###############################################################
#  Generated by:      Cadence Innovus 20.13-s083_1
#  OS:                Linux x86_64(Host ID caddy10)
#  Generated on:      Sun Jun 13 01:40:49 2021
#  Design:            user_proj_example
#  Command:           write_lef_abstract -specifyTopLayer 6 -PGPinLayers {5 6} -noCutObs -stripePin results/user_proj_example.lef
###############################################################

VERSION 5.8 ;

BUSBITCHARS "[]" ;
DIVIDERCHAR "/" ;

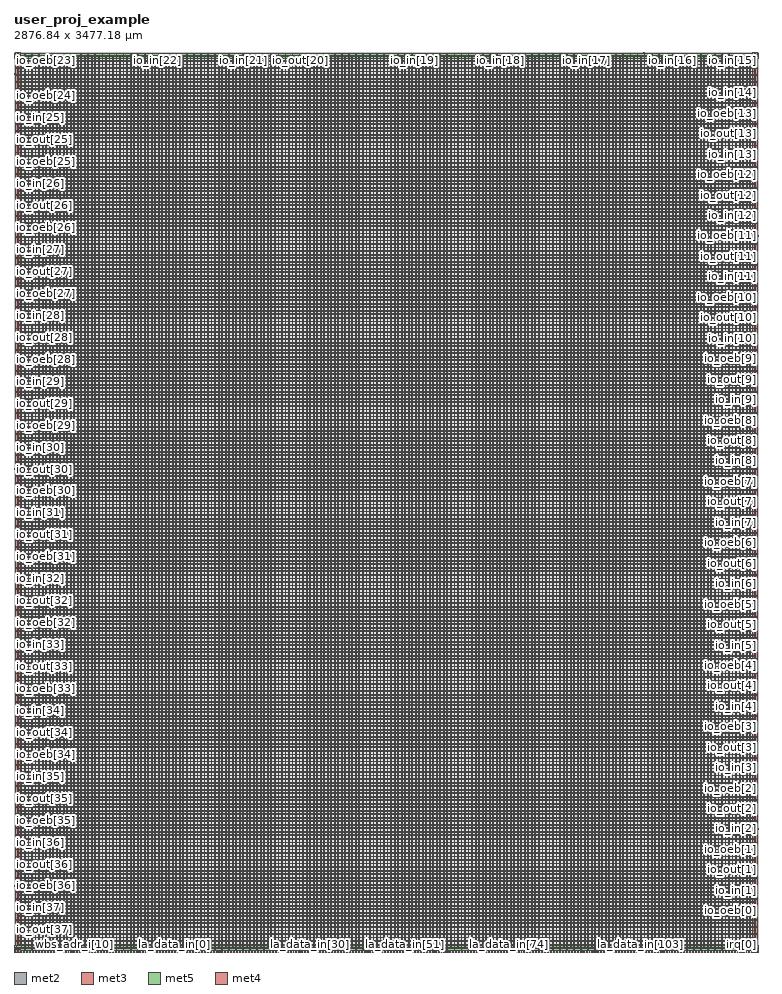
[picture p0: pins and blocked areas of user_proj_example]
MACRO user_proj_example
  CLASS BLOCK ;
  SIZE 2876.840000 BY 3477.180000 ;
  FOREIGN user_proj_example 0.000000 0.000000 ;
  ORIGIN 0 0 ;
  SYMMETRY X Y R90 ;
  PIN user_clock2
    DIRECTION INPUT ;
    USE SIGNAL ;
    PORT
      LAYER met2 ;
        RECT 2859.060000 0.000000 2859.200000 0.485000 ;
    END
  END user_clock2
  PIN wb_clk_i
    DIRECTION INPUT ;
    USE SIGNAL ;
    ANTENNAPARTIALMETALAREA 0.2744 LAYER met2  ;
    ANTENNAPARTIALMETALSIDEAREA 1.211 LAYER met2  ;
    ANTENNAPARTIALCUTAREA 0.04 LAYER via2  ;
    ANTENNAPARTIALMETALAREA 9.5028 LAYER met3  ;
    ANTENNAPARTIALMETALSIDEAREA 51.152 LAYER met3  ;
    ANTENNAMODEL OXIDE1 ;
    ANTENNAGATEAREA 0.576 LAYER met3  ;
    ANTENNAMAXAREACAR 24.1977 LAYER met3  ;
    ANTENNAMAXSIDEAREACAR 125.109 LAYER met3  ;
    ANTENNAMAXCUTCAR 0.158681 LAYER via3  ;
    PORT
      LAYER met2 ;
        RECT 0.620000 0.000000 0.760000 0.485000 ;
    END
  END wb_clk_i
  PIN wb_rst_i
    DIRECTION INPUT ;
    USE SIGNAL ;
    ANTENNAPARTIALMETALAREA 14.1803 LAYER met2  ;
    ANTENNAPARTIALMETALSIDEAREA 70.6755 LAYER met2  ;
    ANTENNAMODEL OXIDE1 ;
    ANTENNAGATEAREA 1.152 LAYER met2  ;
    ANTENNAMAXAREACAR 16.849 LAYER met2  ;
    ANTENNAMAXSIDEAREACAR 82.2422 LAYER met2  ;
    ANTENNAMAXCUTCAR 0.0446181 LAYER via2  ;
    PORT
      LAYER met2 ;
        RECT 6.140000 0.000000 6.280000 0.485000 ;
    END
  END wb_rst_i
  PIN wbs_stb_i
    DIRECTION INPUT ;
    USE SIGNAL ;
    ANTENNAPARTIALMETALAREA 12.5407 LAYER met2  ;
    ANTENNAPARTIALMETALSIDEAREA 62.3595 LAYER met2  ;
    ANTENNAMODEL OXIDE1 ;
    ANTENNAGATEAREA 0.747 LAYER met2  ;
    ANTENNAMAXAREACAR 51.6972 LAYER met2  ;
    ANTENNAMAXSIDEAREACAR 255.943 LAYER met2  ;
    ANTENNAMAXCUTCAR 0.407937 LAYER via2  ;
    PORT
      LAYER met2 ;
        RECT 23.620000 0.000000 23.760000 0.485000 ;
    END
  END wbs_stb_i
  PIN wbs_cyc_i
    DIRECTION INPUT ;
    USE SIGNAL ;
    PORT
      LAYER met2 ;
        RECT 18.100000 0.000000 18.240000 0.485000 ;
    END
  END wbs_cyc_i
  PIN wbs_we_i
    DIRECTION INPUT ;
    USE SIGNAL ;
    ANTENNAPARTIALMETALAREA 12.8503 LAYER met2  ;
    ANTENNAPARTIALMETALSIDEAREA 64.0255 LAYER met2  ;
    ANTENNAMODEL OXIDE1 ;
    ANTENNAGATEAREA 0.495 LAYER met2  ;
    ANTENNAMAXAREACAR 30.2657 LAYER met2  ;
    ANTENNAMAXSIDEAREACAR 149.204 LAYER met2  ;
    ANTENNAMAXCUTCAR 0.103838 LAYER via2  ;
    PORT
      LAYER met2 ;
        RECT 29.600000 0.000000 29.740000 0.485000 ;
    END
  END wbs_we_i
  PIN wbs_sel_i[3]
    DIRECTION INPUT ;
    USE SIGNAL ;
    PORT
      LAYER met2 ;
        RECT 122.980000 0.000000 123.120000 0.485000 ;
    END
  END wbs_sel_i[3]
  PIN wbs_sel_i[2]
    DIRECTION INPUT ;
    USE SIGNAL ;
    PORT
      LAYER met2 ;
        RECT 99.520000 0.000000 99.660000 0.485000 ;
    END
  END wbs_sel_i[2]
  PIN wbs_sel_i[1]
    DIRECTION INPUT ;
    USE SIGNAL ;
    PORT
      LAYER met2 ;
        RECT 76.060000 0.000000 76.200000 0.485000 ;
    END
  END wbs_sel_i[1]
  PIN wbs_sel_i[0]
    DIRECTION INPUT ;
    USE SIGNAL ;
    PORT
      LAYER met2 ;
        RECT 53.060000 0.000000 53.200000 0.485000 ;
    END
  END wbs_sel_i[0]
  PIN wbs_dat_i[31]
    DIRECTION INPUT ;
    USE SIGNAL ;
    ANTENNAPARTIALMETALAREA 9.9099 LAYER met2  ;
    ANTENNAPARTIALMETALSIDEAREA 49.3885 LAYER met2  ;
    ANTENNAPARTIALCUTAREA 0.04 LAYER via2  ;
    ANTENNAPARTIALMETALAREA 3.16 LAYER met3  ;
    ANTENNAPARTIALMETALSIDEAREA 17.32 LAYER met3  ;
    ANTENNAPARTIALCUTAREA 0.04 LAYER via3  ;
    ANTENNAPARTIALMETALAREA 72.1438 LAYER met4  ;
    ANTENNAPARTIALMETALSIDEAREA 381.112 LAYER met4  ;
    ANTENNAPARTIALCUTAREA 0.64 LAYER via4  ;
    ANTENNADIFFAREA 1.3041 LAYER met5  ;
    ANTENNAPARTIALMETALAREA 28.784 LAYER met5  ;
    ANTENNAPARTIALMETALSIDEAREA 58.536 LAYER met5  ;
    ANTENNAMODEL OXIDE1 ;
    ANTENNAGATEAREA 1.9926 LAYER met5  ;
    ANTENNAMAXAREACAR 130.13 LAYER met5  ;
    ANTENNAMAXSIDEAREACAR 622.528 LAYER met5  ;
    PORT
      LAYER met2 ;
        RECT 607.360000 0.000000 607.500000 0.485000 ;
    END
  END wbs_dat_i[31]
  PIN wbs_dat_i[30]
    DIRECTION INPUT ;
    USE SIGNAL ;
    ANTENNAPARTIALMETALAREA 6.1684 LAYER met2  ;
    ANTENNAPARTIALMETALSIDEAREA 30.681 LAYER met2  ;
    ANTENNAPARTIALCUTAREA 0.04 LAYER via2  ;
    ANTENNAPARTIALMETALAREA 0.952 LAYER met3  ;
    ANTENNAPARTIALMETALSIDEAREA 5.544 LAYER met3  ;
    ANTENNAPARTIALCUTAREA 0.04 LAYER via3  ;
    ANTENNAPARTIALMETALAREA 47.7568 LAYER met4  ;
    ANTENNAPARTIALMETALSIDEAREA 251.048 LAYER met4  ;
    ANTENNAPARTIALCUTAREA 0.64 LAYER via4  ;
    ANTENNADIFFAREA 0.8694 LAYER met5  ;
    ANTENNAPARTIALMETALAREA 32.128 LAYER met5  ;
    ANTENNAPARTIALMETALSIDEAREA 59.712 LAYER met5  ;
    ANTENNAMODEL OXIDE1 ;
    ANTENNAGATEAREA 1.5579 LAYER met5  ;
    ANTENNAMAXAREACAR 136.066 LAYER met5  ;
    ANTENNAMAXSIDEAREACAR 629.718 LAYER met5  ;
    PORT
      LAYER met2 ;
        RECT 589.880000 0.000000 590.020000 0.485000 ;
    END
  END wbs_dat_i[30]
  PIN wbs_dat_i[29]
    DIRECTION INPUT ;
    USE SIGNAL ;
    ANTENNAPARTIALMETALAREA 7.5558 LAYER met2  ;
    ANTENNAPARTIALMETALSIDEAREA 37.618 LAYER met2  ;
    ANTENNAPARTIALCUTAREA 0.04 LAYER via2  ;
    ANTENNAPARTIALMETALAREA 0.814 LAYER met3  ;
    ANTENNAPARTIALMETALSIDEAREA 4.808 LAYER met3  ;
    ANTENNAPARTIALCUTAREA 0.04 LAYER via3  ;
    ANTENNAPARTIALMETALAREA 4.6168 LAYER met4  ;
    ANTENNAPARTIALMETALSIDEAREA 20.968 LAYER met4  ;
    ANTENNAPARTIALCUTAREA 0.64 LAYER via4  ;
    ANTENNADIFFAREA 1.3041 LAYER met5  ;
    ANTENNAPARTIALMETALAREA 34.688 LAYER met5  ;
    ANTENNAPARTIALMETALSIDEAREA 67.392 LAYER met5  ;
    ANTENNAMODEL OXIDE1 ;
    ANTENNAGATEAREA 1.9926 LAYER met5  ;
    ANTENNAMAXAREACAR 122.263 LAYER met5  ;
    ANTENNAMAXSIDEAREACAR 568.279 LAYER met5  ;
    PORT
      LAYER met2 ;
        RECT 571.940000 0.000000 572.080000 0.485000 ;
    END
  END wbs_dat_i[29]
  PIN wbs_dat_i[28]
    DIRECTION INPUT ;
    USE SIGNAL ;
    ANTENNAPARTIALMETALAREA 9.9743 LAYER met2  ;
    ANTENNAPARTIALMETALSIDEAREA 49.7105 LAYER met2  ;
    ANTENNAPARTIALCUTAREA 0.04 LAYER via2  ;
    ANTENNAPARTIALMETALAREA 8.542 LAYER met3  ;
    ANTENNAPARTIALMETALSIDEAREA 46.024 LAYER met3  ;
    ANTENNAPARTIALCUTAREA 0.04 LAYER via3  ;
    ANTENNAPARTIALMETALAREA 31.7488 LAYER met4  ;
    ANTENNAPARTIALMETALSIDEAREA 165.672 LAYER met4  ;
    ANTENNAPARTIALCUTAREA 0.64 LAYER via4  ;
    ANTENNADIFFAREA 0.8694 LAYER met5  ;
    ANTENNAPARTIALMETALAREA 28.784 LAYER met5  ;
    ANTENNAPARTIALMETALSIDEAREA 58.536 LAYER met5  ;
    ANTENNAMODEL OXIDE1 ;
    ANTENNAGATEAREA 1.5579 LAYER met5  ;
    ANTENNAMAXAREACAR 82.9943 LAYER met5  ;
    ANTENNAMAXSIDEAREACAR 360.268 LAYER met5  ;
    PORT
      LAYER met2 ;
        RECT 554.460000 0.000000 554.600000 0.485000 ;
    END
  END wbs_dat_i[28]
  PIN wbs_dat_i[27]
    DIRECTION INPUT ;
    USE SIGNAL ;
    ANTENNAPARTIALMETALAREA 9.9099 LAYER met2  ;
    ANTENNAPARTIALMETALSIDEAREA 49.3885 LAYER met2  ;
    ANTENNAPARTIALCUTAREA 0.04 LAYER via2  ;
    ANTENNAPARTIALMETALAREA 1.297 LAYER met3  ;
    ANTENNAPARTIALMETALSIDEAREA 7.384 LAYER met3  ;
    ANTENNAPARTIALCUTAREA 0.04 LAYER via3  ;
    ANTENNAPARTIALMETALAREA 62.0944 LAYER met4  ;
    ANTENNAPARTIALMETALSIDEAREA 328.456 LAYER met4  ;
    ANTENNAPARTIALCUTAREA 0.64 LAYER via4  ;
    ANTENNADIFFAREA 1.3041 LAYER met5  ;
    ANTENNAPARTIALMETALAREA 81.904 LAYER met5  ;
    ANTENNAPARTIALMETALSIDEAREA 138.216 LAYER met5  ;
    ANTENNAMODEL OXIDE1 ;
    ANTENNAGATEAREA 1.9926 LAYER met5  ;
    ANTENNAMAXAREACAR 122.231 LAYER met5  ;
    ANTENNAMAXSIDEAREACAR 480.79 LAYER met5  ;
    PORT
      LAYER met2 ;
        RECT 536.980000 0.000000 537.120000 0.485000 ;
    END
  END wbs_dat_i[27]
  PIN wbs_dat_i[26]
    DIRECTION INPUT ;
    USE SIGNAL ;
    ANTENNAPARTIALMETALAREA 3.8612 LAYER met2  ;
    ANTENNAPARTIALMETALSIDEAREA 19.145 LAYER met2  ;
    ANTENNAPARTIALCUTAREA 0.04 LAYER via2  ;
    ANTENNAPARTIALMETALAREA 4.609 LAYER met3  ;
    ANTENNAPARTIALMETALSIDEAREA 25.048 LAYER met3  ;
    ANTENNAPARTIALCUTAREA 0.04 LAYER via3  ;
    ANTENNAPARTIALMETALAREA 65.3806 LAYER met4  ;
    ANTENNAPARTIALMETALSIDEAREA 345.512 LAYER met4  ;
    ANTENNAPARTIALCUTAREA 0.64 LAYER via4  ;
    ANTENNADIFFAREA 1.3041 LAYER met5  ;
    ANTENNAPARTIALMETALAREA 133.984 LAYER met5  ;
    ANTENNAPARTIALMETALSIDEAREA 208.656 LAYER met5  ;
    ANTENNAMODEL OXIDE1 ;
    ANTENNAGATEAREA 1.9926 LAYER met5  ;
    ANTENNAMAXAREACAR 191.53 LAYER met5  ;
    ANTENNAMAXSIDEAREACAR 743.382 LAYER met5  ;
    PORT
      LAYER met2 ;
        RECT 519.500000 0.000000 519.640000 0.485000 ;
    END
  END wbs_dat_i[26]
  PIN wbs_dat_i[25]
    DIRECTION INPUT ;
    USE SIGNAL ;
    ANTENNAPARTIALMETALAREA 7.791 LAYER met2  ;
    ANTENNAPARTIALMETALSIDEAREA 38.794 LAYER met2  ;
    ANTENNAPARTIALCUTAREA 0.04 LAYER via2  ;
    ANTENNAPARTIALMETALAREA 7.645 LAYER met3  ;
    ANTENNAPARTIALMETALSIDEAREA 41.24 LAYER met3  ;
    ANTENNAPARTIALCUTAREA 0.04 LAYER via3  ;
    ANTENNAPARTIALMETALAREA 40.4848 LAYER met4  ;
    ANTENNAPARTIALMETALSIDEAREA 212.264 LAYER met4  ;
    ANTENNAPARTIALCUTAREA 0.64 LAYER via4  ;
    ANTENNADIFFAREA 0.8694 LAYER met5  ;
    ANTENNAPARTIALMETALAREA 69.904 LAYER met5  ;
    ANTENNAPARTIALMETALSIDEAREA 124.056 LAYER met5  ;
    ANTENNAMODEL OXIDE1 ;
    ANTENNAGATEAREA 1.5579 LAYER met5  ;
    ANTENNAMAXAREACAR 131.547 LAYER met5  ;
    ANTENNAMAXSIDEAREACAR 523.396 LAYER met5  ;
    PORT
      LAYER met2 ;
        RECT 502.020000 0.000000 502.160000 0.485000 ;
    END
  END wbs_dat_i[25]
  PIN wbs_dat_i[24]
    DIRECTION INPUT ;
    USE SIGNAL ;
    ANTENNAPARTIALMETALAREA 10.738 LAYER met2  ;
    ANTENNAPARTIALMETALSIDEAREA 53.529 LAYER met2  ;
    ANTENNAPARTIALCUTAREA 0.04 LAYER via2  ;
    ANTENNAPARTIALMETALAREA 7.921 LAYER met3  ;
    ANTENNAPARTIALMETALSIDEAREA 42.712 LAYER met3  ;
    ANTENNAPARTIALCUTAREA 0.04 LAYER via3  ;
    ANTENNAPARTIALMETALAREA 50.5258 LAYER met4  ;
    ANTENNAPARTIALMETALSIDEAREA 265.816 LAYER met4  ;
    ANTENNAPARTIALCUTAREA 0.64 LAYER via4  ;
    ANTENNADIFFAREA 0.8694 LAYER met5  ;
    ANTENNAPARTIALMETALAREA 45.152 LAYER met5  ;
    ANTENNAPARTIALMETALSIDEAREA 86.928 LAYER met5  ;
    ANTENNAMODEL OXIDE1 ;
    ANTENNAGATEAREA 1.5579 LAYER met5  ;
    ANTENNAMAXAREACAR 113.719 LAYER met5  ;
    ANTENNAMAXSIDEAREACAR 490.9 LAYER met5  ;
    PORT
      LAYER met2 ;
        RECT 484.540000 0.000000 484.680000 0.485000 ;
    END
  END wbs_dat_i[24]
  PIN wbs_dat_i[23]
    DIRECTION INPUT ;
    USE SIGNAL ;
    ANTENNAPARTIALMETALAREA 7.053 LAYER met2  ;
    ANTENNAPARTIALMETALSIDEAREA 34.986 LAYER met2  ;
    ANTENNAPARTIALCUTAREA 0.04 LAYER via2  ;
    ANTENNAPARTIALMETALAREA 3.643 LAYER met3  ;
    ANTENNAPARTIALMETALSIDEAREA 19.896 LAYER met3  ;
    ANTENNAPARTIALCUTAREA 0.04 LAYER via3  ;
    ANTENNAPARTIALMETALAREA 70.4968 LAYER met4  ;
    ANTENNAPARTIALMETALSIDEAREA 372.328 LAYER met4  ;
    ANTENNAPARTIALCUTAREA 0.64 LAYER via4  ;
    ANTENNADIFFAREA 0.4347 LAYER met5  ;
    ANTENNAPARTIALMETALAREA 23.296 LAYER met5  ;
    ANTENNAPARTIALMETALSIDEAREA 46.464 LAYER met5  ;
    ANTENNAMODEL OXIDE1 ;
    ANTENNAGATEAREA 1.1232 LAYER met5  ;
    ANTENNAMAXAREACAR 170.738 LAYER met5  ;
    ANTENNAMAXSIDEAREACAR 789.227 LAYER met5  ;
    PORT
      LAYER met2 ;
        RECT 467.060000 0.000000 467.200000 0.485000 ;
    END
  END wbs_dat_i[23]
  PIN wbs_dat_i[22]
    DIRECTION INPUT ;
    USE SIGNAL ;
    ANTENNAPARTIALMETALAREA 3.2634 LAYER met2  ;
    ANTENNAPARTIALMETALSIDEAREA 16.156 LAYER met2  ;
    ANTENNAPARTIALCUTAREA 0.04 LAYER via2  ;
    ANTENNAPARTIALMETALAREA 22.894 LAYER met3  ;
    ANTENNAPARTIALMETALSIDEAREA 122.568 LAYER met3  ;
    ANTENNAPARTIALCUTAREA 0.04 LAYER via3  ;
    ANTENNAPARTIALMETALAREA 65.9218 LAYER met4  ;
    ANTENNAPARTIALMETALSIDEAREA 347.928 LAYER met4  ;
    ANTENNAPARTIALCUTAREA 0.64 LAYER via4  ;
    ANTENNADIFFAREA 0.8694 LAYER met5  ;
    ANTENNAPARTIALMETALAREA 107.84 LAYER met5  ;
    ANTENNAPARTIALMETALSIDEAREA 173.28 LAYER met5  ;
    ANTENNAMODEL OXIDE1 ;
    ANTENNAGATEAREA 1.5579 LAYER met5  ;
    ANTENNAMAXAREACAR 177.438 LAYER met5  ;
    ANTENNAMAXSIDEAREACAR 665.246 LAYER met5  ;
    PORT
      LAYER met2 ;
        RECT 449.580000 0.000000 449.720000 0.485000 ;
    END
  END wbs_dat_i[22]
  PIN wbs_dat_i[21]
    DIRECTION INPUT ;
    USE SIGNAL ;
    ANTENNAPARTIALMETALAREA 9.4976 LAYER met2  ;
    ANTENNAPARTIALMETALSIDEAREA 47.327 LAYER met2  ;
    ANTENNAPARTIALCUTAREA 0.04 LAYER via2  ;
    ANTENNAPARTIALMETALAREA 23.791 LAYER met3  ;
    ANTENNAPARTIALMETALSIDEAREA 127.352 LAYER met3  ;
    ANTENNAPARTIALCUTAREA 0.04 LAYER via3  ;
    ANTENNAPARTIALMETALAREA 16.9018 LAYER met4  ;
    ANTENNAPARTIALMETALSIDEAREA 86.488 LAYER met4  ;
    ANTENNAPARTIALCUTAREA 0.64 LAYER via4  ;
    ANTENNADIFFAREA 1.3041 LAYER met5  ;
    ANTENNAPARTIALMETALAREA 22.96 LAYER met5  ;
    ANTENNAPARTIALMETALSIDEAREA 45.96 LAYER met5  ;
    ANTENNAMODEL OXIDE1 ;
    ANTENNAGATEAREA 1.9926 LAYER met5  ;
    ANTENNAMAXAREACAR 93.4912 LAYER met5  ;
    ANTENNAMAXSIDEAREACAR 435.548 LAYER met5  ;
    PORT
      LAYER met2 ;
        RECT 432.100000 0.000000 432.240000 0.485000 ;
    END
  END wbs_dat_i[21]
  PIN wbs_dat_i[20]
    DIRECTION INPUT ;
    USE SIGNAL ;
    ANTENNAPARTIALMETALAREA 8.729 LAYER met2  ;
    ANTENNAPARTIALMETALSIDEAREA 43.484 LAYER met2  ;
    ANTENNAPARTIALCUTAREA 0.04 LAYER via2  ;
    ANTENNAPARTIALMETALAREA 30.277 LAYER met3  ;
    ANTENNAPARTIALMETALSIDEAREA 161.944 LAYER met3  ;
    ANTENNAPARTIALCUTAREA 0.04 LAYER via3  ;
    ANTENNAPARTIALMETALAREA 71.2126 LAYER met4  ;
    ANTENNAPARTIALMETALSIDEAREA 376.616 LAYER met4  ;
    ANTENNAPARTIALCUTAREA 0.64 LAYER via4  ;
    ANTENNADIFFAREA 0.8694 LAYER met5  ;
    ANTENNAPARTIALMETALAREA 38 LAYER met5  ;
    ANTENNAPARTIALMETALSIDEAREA 72.36 LAYER met5  ;
    ANTENNAMODEL OXIDE1 ;
    ANTENNAGATEAREA 1.5579 LAYER met5  ;
    ANTENNAMAXAREACAR 86.1611 LAYER met5  ;
    ANTENNAMAXSIDEAREACAR 348.053 LAYER met5  ;
    PORT
      LAYER met2 ;
        RECT 414.620000 0.000000 414.760000 0.485000 ;
    END
  END wbs_dat_i[20]
  PIN wbs_dat_i[19]
    DIRECTION INPUT ;
    USE SIGNAL ;
    ANTENNAPARTIALMETALAREA 5.0148 LAYER met2  ;
    ANTENNAPARTIALMETALSIDEAREA 24.913 LAYER met2  ;
    ANTENNAPARTIALCUTAREA 0.04 LAYER via2  ;
    ANTENNAPARTIALMETALAREA 45.802 LAYER met3  ;
    ANTENNAPARTIALMETALSIDEAREA 244.744 LAYER met3  ;
    ANTENNAPARTIALCUTAREA 0.04 LAYER via3  ;
    ANTENNAPARTIALMETALAREA 45.9508 LAYER met4  ;
    ANTENNAPARTIALMETALSIDEAREA 241.416 LAYER met4  ;
    ANTENNAPARTIALCUTAREA 0.64 LAYER via4  ;
    ANTENNADIFFAREA 1.3041 LAYER met5  ;
    ANTENNAPARTIALMETALAREA 7.44 LAYER met5  ;
    ANTENNAPARTIALMETALSIDEAREA 15 LAYER met5  ;
    ANTENNAMODEL OXIDE1 ;
    ANTENNAGATEAREA 1.9926 LAYER met5  ;
    ANTENNAMAXAREACAR 89.1782 LAYER met5  ;
    ANTENNAMAXSIDEAREACAR 442.671 LAYER met5  ;
    PORT
      LAYER met2 ;
        RECT 397.140000 0.000000 397.280000 0.485000 ;
    END
  END wbs_dat_i[19]
  PIN wbs_dat_i[18]
    DIRECTION INPUT ;
    USE SIGNAL ;
    ANTENNAPARTIALMETALAREA 2.5802 LAYER met2  ;
    ANTENNAPARTIALMETALSIDEAREA 12.74 LAYER met2  ;
    ANTENNAPARTIALCUTAREA 0.04 LAYER via2  ;
    ANTENNAPARTIALMETALAREA 22.135 LAYER met3  ;
    ANTENNAPARTIALMETALSIDEAREA 118.52 LAYER met3  ;
    ANTENNAPARTIALCUTAREA 0.04 LAYER via3  ;
    ANTENNAPARTIALMETALAREA 59.4928 LAYER met4  ;
    ANTENNAPARTIALMETALSIDEAREA 313.64 LAYER met4  ;
    ANTENNAPARTIALCUTAREA 0.64 LAYER via4  ;
    ANTENNADIFFAREA 1.3041 LAYER met5  ;
    ANTENNAPARTIALMETALAREA 258.384 LAYER met5  ;
    ANTENNAPARTIALMETALSIDEAREA 406.776 LAYER met5  ;
    ANTENNAMODEL OXIDE1 ;
    ANTENNAGATEAREA 1.9926 LAYER met5  ;
    ANTENNAMAXAREACAR 236.023 LAYER met5  ;
    ANTENNAMAXSIDEAREACAR 747.267 LAYER met5  ;
    PORT
      LAYER met2 ;
        RECT 379.660000 0.000000 379.800000 0.485000 ;
    END
  END wbs_dat_i[18]
  PIN wbs_dat_i[17]
    DIRECTION INPUT ;
    USE SIGNAL ;
    ANTENNAPARTIALMETALAREA 7.1918 LAYER met2  ;
    ANTENNAPARTIALMETALSIDEAREA 35.798 LAYER met2  ;
    ANTENNAPARTIALCUTAREA 0.04 LAYER via2  ;
    ANTENNAPARTIALMETALAREA 28.621 LAYER met3  ;
    ANTENNAPARTIALMETALSIDEAREA 153.112 LAYER met3  ;
    ANTENNAPARTIALCUTAREA 0.04 LAYER via3  ;
    ANTENNAPARTIALMETALAREA 41.2168 LAYER met4  ;
    ANTENNAPARTIALMETALSIDEAREA 216.168 LAYER met4  ;
    ANTENNAPARTIALCUTAREA 0.64 LAYER via4  ;
    ANTENNADIFFAREA 1.3041 LAYER met5  ;
    ANTENNAPARTIALMETALAREA 15.856 LAYER met5  ;
    ANTENNAPARTIALMETALSIDEAREA 31.464 LAYER met5  ;
    ANTENNAMODEL OXIDE1 ;
    ANTENNAGATEAREA 1.9926 LAYER met5  ;
    ANTENNAMAXAREACAR 112.744 LAYER met5  ;
    ANTENNAMAXSIDEAREACAR 556.147 LAYER met5  ;
    PORT
      LAYER met2 ;
        RECT 362.180000 0.000000 362.320000 0.485000 ;
    END
  END wbs_dat_i[17]
  PIN wbs_dat_i[16]
    DIRECTION INPUT ;
    USE SIGNAL ;
    ANTENNAPARTIALMETALAREA 4.2028 LAYER met2  ;
    ANTENNAPARTIALMETALSIDEAREA 20.853 LAYER met2  ;
    ANTENNAPARTIALCUTAREA 0.04 LAYER via2  ;
    ANTENNAPARTIALMETALAREA 61.603 LAYER met3  ;
    ANTENNAPARTIALMETALSIDEAREA 329.016 LAYER met3  ;
    ANTENNAPARTIALCUTAREA 0.04 LAYER via3  ;
    ANTENNAPARTIALMETALAREA 51.4168 LAYER met4  ;
    ANTENNAPARTIALMETALSIDEAREA 270.568 LAYER met4  ;
    ANTENNAPARTIALCUTAREA 0.64 LAYER via4  ;
    ANTENNADIFFAREA 1.3041 LAYER met5  ;
    ANTENNAPARTIALMETALAREA 15.856 LAYER met5  ;
    ANTENNAPARTIALMETALSIDEAREA 31.464 LAYER met5  ;
    ANTENNAMODEL OXIDE1 ;
    ANTENNAGATEAREA 1.9926 LAYER met5  ;
    ANTENNAMAXAREACAR 105.419 LAYER met5  ;
    ANTENNAMAXSIDEAREACAR 511.765 LAYER met5  ;
    PORT
      LAYER met2 ;
        RECT 344.700000 0.000000 344.840000 0.485000 ;
    END
  END wbs_dat_i[16]
  PIN wbs_dat_i[15]
    DIRECTION INPUT ;
    USE SIGNAL ;
    ANTENNAPARTIALMETALAREA 3.8612 LAYER met2  ;
    ANTENNAPARTIALMETALSIDEAREA 19.145 LAYER met2  ;
    ANTENNAPARTIALCUTAREA 0.04 LAYER via2  ;
    ANTENNAPARTIALMETALAREA 38.488 LAYER met3  ;
    ANTENNAPARTIALMETALSIDEAREA 205.736 LAYER met3  ;
    ANTENNAPARTIALCUTAREA 0.04 LAYER via3  ;
    ANTENNAPARTIALMETALAREA 90.9298 LAYER met4  ;
    ANTENNAPARTIALMETALSIDEAREA 481.304 LAYER met4  ;
    ANTENNAPARTIALCUTAREA 0.64 LAYER via4  ;
    ANTENNADIFFAREA 1.3041 LAYER met5  ;
    ANTENNAPARTIALMETALAREA 230.448 LAYER met5  ;
    ANTENNAPARTIALMETALSIDEAREA 364.872 LAYER met5  ;
    ANTENNAMODEL OXIDE1 ;
    ANTENNAGATEAREA 1.9926 LAYER met5  ;
    ANTENNAMAXAREACAR 213.099 LAYER met5  ;
    ANTENNAMAXSIDEAREACAR 679.011 LAYER met5  ;
    PORT
      LAYER met2 ;
        RECT 327.220000 0.000000 327.360000 0.485000 ;
    END
  END wbs_dat_i[15]
  PIN wbs_dat_i[14]
    DIRECTION INPUT ;
    USE SIGNAL ;
    ANTENNAPARTIALMETALAREA 8.302 LAYER met2  ;
    ANTENNAPARTIALMETALSIDEAREA 41.349 LAYER met2  ;
    ANTENNAPARTIALCUTAREA 0.04 LAYER via2  ;
    ANTENNAPARTIALMETALAREA 41.248 LAYER met3  ;
    ANTENNAPARTIALMETALSIDEAREA 220.456 LAYER met3  ;
    ANTENNAPARTIALCUTAREA 0.04 LAYER via3  ;
    ANTENNAPARTIALMETALAREA 83.8798 LAYER met4  ;
    ANTENNAPARTIALMETALSIDEAREA 443.704 LAYER met4  ;
    ANTENNAPARTIALCUTAREA 0.64 LAYER via4  ;
    ANTENNADIFFAREA 1.3041 LAYER met5  ;
    ANTENNAPARTIALMETALAREA 208.912 LAYER met5  ;
    ANTENNAPARTIALMETALSIDEAREA 328.728 LAYER met5  ;
    ANTENNAMODEL OXIDE1 ;
    ANTENNAGATEAREA 1.9926 LAYER met5  ;
    ANTENNAMAXAREACAR 174.787 LAYER met5  ;
    ANTENNAMAXSIDEAREACAR 516.392 LAYER met5  ;
    PORT
      LAYER met2 ;
        RECT 309.740000 0.000000 309.880000 0.485000 ;
    END
  END wbs_dat_i[14]
  PIN wbs_dat_i[13]
    DIRECTION INPUT ;
    USE SIGNAL ;
    ANTENNAPARTIALMETALAREA 7.5334 LAYER met2  ;
    ANTENNAPARTIALMETALSIDEAREA 37.506 LAYER met2  ;
    ANTENNAPARTIALCUTAREA 0.04 LAYER via2  ;
    ANTENNAPARTIALMETALAREA 54.565 LAYER met3  ;
    ANTENNAPARTIALMETALSIDEAREA 291.48 LAYER met3  ;
    ANTENNAPARTIALCUTAREA 0.04 LAYER via3  ;
    ANTENNAPARTIALMETALAREA 77.453 LAYER met4  ;
    ANTENNAPARTIALMETALSIDEAREA 410.344 LAYER met4  ;
    ANTENNAPARTIALCUTAREA 0.64 LAYER via4  ;
    ANTENNADIFFAREA 0.8694 LAYER met5  ;
    ANTENNAPARTIALMETALAREA 117.744 LAYER met5  ;
    ANTENNAPARTIALMETALSIDEAREA 191.976 LAYER met5  ;
    ANTENNAMODEL OXIDE1 ;
    ANTENNAGATEAREA 1.5579 LAYER met5  ;
    ANTENNAMAXAREACAR 192.091 LAYER met5  ;
    ANTENNAMAXSIDEAREACAR 715.65 LAYER met5  ;
    PORT
      LAYER met2 ;
        RECT 292.260000 0.000000 292.400000 0.485000 ;
    END
  END wbs_dat_i[13]
  PIN wbs_dat_i[12]
    DIRECTION INPUT ;
    USE SIGNAL ;
    ANTENNAPARTIALMETALAREA 3.5196 LAYER met2  ;
    ANTENNAPARTIALMETALSIDEAREA 17.437 LAYER met2  ;
    ANTENNAPARTIALCUTAREA 0.04 LAYER via2  ;
    ANTENNAPARTIALMETALAREA 63.121 LAYER met3  ;
    ANTENNAPARTIALMETALSIDEAREA 337.112 LAYER met3  ;
    ANTENNAPARTIALCUTAREA 0.04 LAYER via3  ;
    ANTENNAPARTIALMETALAREA 100.653 LAYER met4  ;
    ANTENNAPARTIALMETALSIDEAREA 533.16 LAYER met4  ;
    ANTENNAPARTIALCUTAREA 0.64 LAYER via4  ;
    ANTENNADIFFAREA 0.8694 LAYER met5  ;
    ANTENNAPARTIALMETALAREA 143.472 LAYER met5  ;
    ANTENNAPARTIALMETALSIDEAREA 230.568 LAYER met5  ;
    ANTENNAMODEL OXIDE1 ;
    ANTENNAGATEAREA 1.5579 LAYER met5  ;
    ANTENNAMAXAREACAR 183.925 LAYER met5  ;
    ANTENNAMAXSIDEAREACAR 613.988 LAYER met5  ;
    PORT
      LAYER met2 ;
        RECT 274.780000 0.000000 274.920000 0.485000 ;
    END
  END wbs_dat_i[12]
  PIN wbs_dat_i[11]
    DIRECTION INPUT ;
    USE SIGNAL ;
    ANTENNAPARTIALMETALAREA 5.933 LAYER met2  ;
    ANTENNAPARTIALMETALSIDEAREA 29.386 LAYER met2  ;
    ANTENNAPARTIALCUTAREA 0.04 LAYER via2  ;
    ANTENNAPARTIALMETALAREA 1.849 LAYER met3  ;
    ANTENNAPARTIALMETALSIDEAREA 10.328 LAYER met3  ;
    ANTENNAPARTIALCUTAREA 0.04 LAYER via3  ;
    ANTENNADIFFAREA 1.3041 LAYER met4  ;
    ANTENNAPARTIALMETALAREA 187.383 LAYER met4  ;
    ANTENNAPARTIALMETALSIDEAREA 1001.73 LAYER met4  ;
    ANTENNAMODEL OXIDE1 ;
    ANTENNAGATEAREA 1.9926 LAYER met4  ;
    ANTENNAMAXAREACAR 114.916 LAYER met4  ;
    ANTENNAMAXSIDEAREACAR 601.342 LAYER met4  ;
    ANTENNAMAXCUTCAR 0.377029 LAYER via4  ;
    PORT
      LAYER met2 ;
        RECT 257.300000 0.000000 257.440000 0.485000 ;
    END
  END wbs_dat_i[11]
  PIN wbs_dat_i[10]
    DIRECTION INPUT ;
    USE SIGNAL ;
    ANTENNAPARTIALMETALAREA 2.2386 LAYER met2  ;
    ANTENNAPARTIALMETALSIDEAREA 11.032 LAYER met2  ;
    ANTENNAPARTIALCUTAREA 0.04 LAYER via2  ;
    ANTENNAPARTIALMETALAREA 69.676 LAYER met3  ;
    ANTENNAPARTIALMETALSIDEAREA 372.072 LAYER met3  ;
    ANTENNAPARTIALCUTAREA 0.04 LAYER via3  ;
    ANTENNAPARTIALMETALAREA 113.096 LAYER met4  ;
    ANTENNAPARTIALMETALSIDEAREA 599.992 LAYER met4  ;
    ANTENNAPARTIALCUTAREA 0.64 LAYER via4  ;
    ANTENNADIFFAREA 0.4347 LAYER met5  ;
    ANTENNAPARTIALMETALAREA 107.712 LAYER met5  ;
    ANTENNAPARTIALMETALSIDEAREA 173.088 LAYER met5  ;
    ANTENNAMODEL OXIDE1 ;
    ANTENNAGATEAREA 1.1232 LAYER met5  ;
    ANTENNAMAXAREACAR 203.327 LAYER met5  ;
    ANTENNAMAXSIDEAREACAR 711.058 LAYER met5  ;
    PORT
      LAYER met2 ;
        RECT 239.820000 0.000000 239.960000 0.485000 ;
    END
  END wbs_dat_i[10]
  PIN wbs_dat_i[9]
    DIRECTION INPUT ;
    USE SIGNAL ;
    ANTENNAPARTIALMETALAREA 0.2744 LAYER met2  ;
    ANTENNAPARTIALMETALSIDEAREA 1.211 LAYER met2  ;
    ANTENNAPARTIALCUTAREA 0.04 LAYER via2  ;
    ANTENNAPARTIALMETALAREA 69.676 LAYER met3  ;
    ANTENNAPARTIALMETALSIDEAREA 372.072 LAYER met3  ;
    ANTENNAPARTIALCUTAREA 0.04 LAYER via3  ;
    ANTENNAPARTIALMETALAREA 76.9258 LAYER met4  ;
    ANTENNAPARTIALMETALSIDEAREA 406.616 LAYER met4  ;
    ANTENNAPARTIALCUTAREA 0.64 LAYER via4  ;
    ANTENNADIFFAREA 0.8694 LAYER met5  ;
    ANTENNAPARTIALMETALAREA 175.824 LAYER met5  ;
    ANTENNAPARTIALMETALSIDEAREA 275.256 LAYER met5  ;
    ANTENNAMODEL OXIDE1 ;
    ANTENNAGATEAREA 1.5579 LAYER met5  ;
    ANTENNAMAXAREACAR 210.38 LAYER met5  ;
    ANTENNAMAXSIDEAREACAR 674.009 LAYER met5  ;
    PORT
      LAYER met2 ;
        RECT 221.880000 0.000000 222.020000 0.485000 ;
    END
  END wbs_dat_i[9]
  PIN wbs_dat_i[8]
    DIRECTION INPUT ;
    USE SIGNAL ;
    ANTENNAPARTIALMETALAREA 25.4056 LAYER met2  ;
    ANTENNAPARTIALMETALSIDEAREA 126.749 LAYER met2  ;
    ANTENNAPARTIALCUTAREA 0.04 LAYER via2  ;
    ANTENNAPARTIALMETALAREA 1.504 LAYER met3  ;
    ANTENNAPARTIALMETALSIDEAREA 8.488 LAYER met3  ;
    ANTENNAPARTIALCUTAREA 0.04 LAYER via3  ;
    ANTENNAPARTIALMETALAREA 69.0808 LAYER met4  ;
    ANTENNAPARTIALMETALSIDEAREA 364.776 LAYER met4  ;
    ANTENNAPARTIALCUTAREA 0.64 LAYER via4  ;
    ANTENNADIFFAREA 0.4347 LAYER met5  ;
    ANTENNAPARTIALMETALAREA 20.752 LAYER met5  ;
    ANTENNAPARTIALMETALSIDEAREA 42.648 LAYER met5  ;
    ANTENNAMODEL OXIDE1 ;
    ANTENNAGATEAREA 1.1232 LAYER met5  ;
    ANTENNAMAXAREACAR 136.782 LAYER met5  ;
    ANTENNAMAXSIDEAREACAR 627.256 LAYER met5  ;
    PORT
      LAYER met2 ;
        RECT 204.400000 0.000000 204.540000 0.485000 ;
    END
  END wbs_dat_i[8]
  PIN wbs_dat_i[7]
    DIRECTION INPUT ;
    USE SIGNAL ;
    ANTENNAPARTIALMETALAREA 8.5384 LAYER met2  ;
    ANTENNAPARTIALMETALSIDEAREA 42.413 LAYER met2  ;
    ANTENNAPARTIALCUTAREA 0.04 LAYER via2  ;
    ANTENNAPARTIALMETALAREA 0.676 LAYER met3  ;
    ANTENNAPARTIALMETALSIDEAREA 4.072 LAYER met3  ;
    ANTENNAPARTIALCUTAREA 0.04 LAYER via3  ;
    ANTENNAPARTIALMETALAREA 109.41 LAYER met4  ;
    ANTENNAPARTIALMETALSIDEAREA 575.736 LAYER met4  ;
    ANTENNAPARTIALCUTAREA 1.28 LAYER via4  ;
    ANTENNADIFFAREA 0.8694 LAYER met5  ;
    ANTENNAPARTIALMETALAREA 123.632 LAYER met5  ;
    ANTENNAPARTIALMETALSIDEAREA 196.968 LAYER met5  ;
    ANTENNAMODEL OXIDE1 ;
    ANTENNAGATEAREA 1.5579 LAYER met5  ;
    ANTENNAMAXAREACAR 174.185 LAYER met5  ;
    ANTENNAMAXSIDEAREACAR 583.773 LAYER met5  ;
    PORT
      LAYER met2 ;
        RECT 186.920000 0.000000 187.060000 0.485000 ;
    END
  END wbs_dat_i[7]
  PIN wbs_dat_i[6]
    DIRECTION INPUT ;
    USE SIGNAL ;
    ANTENNAPARTIALMETALAREA 8.0874 LAYER met2  ;
    ANTENNAPARTIALMETALSIDEAREA 40.257 LAYER met2  ;
    ANTENNAPARTIALCUTAREA 0.04 LAYER via2  ;
    ANTENNAPARTIALMETALAREA 0.255 LAYER met3  ;
    ANTENNAPARTIALMETALSIDEAREA 1.808 LAYER met3  ;
    ANTENNAPARTIALCUTAREA 0.04 LAYER via3  ;
    ANTENNAPARTIALMETALAREA 63.9796 LAYER met4  ;
    ANTENNAPARTIALMETALSIDEAREA 338.04 LAYER met4  ;
    ANTENNAPARTIALCUTAREA 0.64 LAYER via4  ;
    ANTENNADIFFAREA 0.8694 LAYER met5  ;
    ANTENNAPARTIALMETALAREA 5.872 LAYER met5  ;
    ANTENNAPARTIALMETALSIDEAREA 12.648 LAYER met5  ;
    ANTENNAMODEL OXIDE1 ;
    ANTENNAGATEAREA 1.1919 LAYER met5  ;
    ANTENNAMAXAREACAR 47.7849 LAYER met5  ;
    ANTENNAMAXSIDEAREACAR 217.541 LAYER met5  ;
    PORT
      LAYER met2 ;
        RECT 169.440000 0.000000 169.580000 0.485000 ;
    END
  END wbs_dat_i[6]
  PIN wbs_dat_i[5]
    DIRECTION INPUT ;
    USE SIGNAL ;
    ANTENNAPARTIALMETALAREA 9.167 LAYER met2  ;
    ANTENNAPARTIALMETALSIDEAREA 45.556 LAYER met2  ;
    ANTENNAPARTIALCUTAREA 0.04 LAYER via2  ;
    ANTENNAPARTIALMETALAREA 0.4 LAYER met3  ;
    ANTENNAPARTIALMETALSIDEAREA 2.6 LAYER met3  ;
    ANTENNAPARTIALCUTAREA 0.04 LAYER via3  ;
    ANTENNAPARTIALMETALAREA 87.7306 LAYER met4  ;
    ANTENNAPARTIALMETALSIDEAREA 464.712 LAYER met4  ;
    ANTENNAPARTIALCUTAREA 0.64 LAYER via4  ;
    ANTENNAPARTIALMETALAREA 17.248 LAYER met5  ;
    ANTENNAPARTIALMETALSIDEAREA 29.712 LAYER met5  ;
    ANTENNAMODEL OXIDE1 ;
    ANTENNAGATEAREA 0.3225 LAYER met5  ;
    ANTENNAMAXAREACAR 148.151 LAYER met5  ;
    ANTENNAMAXSIDEAREACAR 568.086 LAYER met5  ;
    PORT
      LAYER met2 ;
        RECT 151.960000 0.000000 152.100000 0.485000 ;
    END
  END wbs_dat_i[5]
  PIN wbs_dat_i[4]
    DIRECTION INPUT ;
    USE SIGNAL ;
    ANTENNAPARTIALMETALAREA 1.9311 LAYER met2  ;
    ANTENNAPARTIALMETALSIDEAREA 9.3765 LAYER met2  ;
    ANTENNAPARTIALCUTAREA 0.04 LAYER via2  ;
    ANTENNAPARTIALMETALAREA 89.065 LAYER met3  ;
    ANTENNAPARTIALMETALSIDEAREA 475.48 LAYER met3  ;
    ANTENNAPARTIALCUTAREA 0.04 LAYER via3  ;
    ANTENNAPARTIALMETALAREA 82.4158 LAYER met4  ;
    ANTENNAPARTIALMETALSIDEAREA 435.896 LAYER met4  ;
    ANTENNAPARTIALCUTAREA 0.64 LAYER via4  ;
    ANTENNADIFFAREA 0.8694 LAYER met5  ;
    ANTENNAPARTIALMETALAREA 207.616 LAYER met5  ;
    ANTENNAPARTIALMETALSIDEAREA 319.104 LAYER met5  ;
    ANTENNAMODEL OXIDE1 ;
    ANTENNAGATEAREA 1.1919 LAYER met5  ;
    ANTENNAMAXAREACAR 251.22 LAYER met5  ;
    ANTENNAMAXSIDEAREACAR 647.485 LAYER met5  ;
    PORT
      LAYER met2 ;
        RECT 134.480000 0.000000 134.620000 0.485000 ;
    END
  END wbs_dat_i[4]
  PIN wbs_dat_i[3]
    DIRECTION INPUT ;
    USE SIGNAL ;
    ANTENNAPARTIALMETALAREA 1.897 LAYER met2  ;
    ANTENNAPARTIALMETALSIDEAREA 9.324 LAYER met2  ;
    ANTENNAPARTIALCUTAREA 0.04 LAYER via2  ;
    ANTENNAPARTIALMETALAREA 134.254 LAYER met3  ;
    ANTENNAPARTIALMETALSIDEAREA 716.488 LAYER met3  ;
    ANTENNAPARTIALCUTAREA 0.04 LAYER via3  ;
    ANTENNAPARTIALMETALAREA 98.2258 LAYER met4  ;
    ANTENNAPARTIALMETALSIDEAREA 520.216 LAYER met4  ;
    ANTENNAPARTIALCUTAREA 0.64 LAYER via4  ;
    ANTENNAPARTIALMETALAREA 10.368 LAYER met5  ;
    ANTENNAPARTIALMETALSIDEAREA 19.392 LAYER met5  ;
    ANTENNAMODEL OXIDE1 ;
    ANTENNAGATEAREA 0.3225 LAYER met5  ;
    ANTENNAMAXAREACAR 162.473 LAYER met5  ;
    ANTENNAMAXSIDEAREACAR 694.117 LAYER met5  ;
    PORT
      LAYER met2 ;
        RECT 111.020000 0.000000 111.160000 0.485000 ;
    END
  END wbs_dat_i[3]
  PIN wbs_dat_i[2]
    DIRECTION INPUT ;
    USE SIGNAL ;
    ANTENNAPARTIALMETALAREA 7.9604 LAYER met2  ;
    ANTENNAPARTIALMETALSIDEAREA 39.641 LAYER met2  ;
    ANTENNAPARTIALCUTAREA 0.04 LAYER via2  ;
    ANTENNAPARTIALMETALAREA 140.47 LAYER met3  ;
    ANTENNAPARTIALMETALSIDEAREA 749.64 LAYER met3  ;
    ANTENNAPARTIALCUTAREA 0.04 LAYER via3  ;
    ANTENNAPARTIALMETALAREA 39.3628 LAYER met4  ;
    ANTENNAPARTIALMETALSIDEAREA 206.28 LAYER met4  ;
    ANTENNAPARTIALCUTAREA 0.64 LAYER via4  ;
    ANTENNADIFFAREA 0.8694 LAYER met5  ;
    ANTENNAPARTIALMETALAREA 13.904 LAYER met5  ;
    ANTENNAPARTIALMETALSIDEAREA 28.536 LAYER met5  ;
    ANTENNAMODEL OXIDE1 ;
    ANTENNAGATEAREA 1.1919 LAYER met5  ;
    ANTENNAMAXAREACAR 76.2268 LAYER met5  ;
    ANTENNAMAXSIDEAREACAR 346.563 LAYER met5  ;
    PORT
      LAYER met2 ;
        RECT 88.020000 0.000000 88.160000 0.485000 ;
    END
  END wbs_dat_i[2]
  PIN wbs_dat_i[1]
    DIRECTION INPUT ;
    USE SIGNAL ;
    ANTENNAPARTIALMETALAREA 6.8502 LAYER met2  ;
    ANTENNAPARTIALMETALSIDEAREA 34.09 LAYER met2  ;
    ANTENNAPARTIALCUTAREA 0.04 LAYER via2  ;
    ANTENNAPARTIALMETALAREA 142.126 LAYER met3  ;
    ANTENNAPARTIALMETALSIDEAREA 758.472 LAYER met3  ;
    ANTENNAPARTIALCUTAREA 0.04 LAYER via3  ;
    ANTENNAPARTIALMETALAREA 41.5348 LAYER met4  ;
    ANTENNAPARTIALMETALSIDEAREA 217.864 LAYER met4  ;
    ANTENNAPARTIALCUTAREA 0.64 LAYER via4  ;
    ANTENNADIFFAREA 0.8694 LAYER met5  ;
    ANTENNAPARTIALMETALAREA 7.44 LAYER met5  ;
    ANTENNAPARTIALMETALSIDEAREA 15 LAYER met5  ;
    ANTENNAMODEL OXIDE1 ;
    ANTENNAGATEAREA 1.1919 LAYER met5  ;
    ANTENNAMAXAREACAR 82.714 LAYER met5  ;
    ANTENNAMAXSIDEAREACAR 397.012 LAYER met5  ;
    PORT
      LAYER met2 ;
        RECT 64.560000 0.000000 64.700000 0.485000 ;
    END
  END wbs_dat_i[1]
  PIN wbs_dat_i[0]
    DIRECTION INPUT ;
    USE SIGNAL ;
    ANTENNAPARTIALMETALAREA 11.0304 LAYER met2  ;
    ANTENNAPARTIALMETALSIDEAREA 54.873 LAYER met2  ;
    ANTENNAPARTIALCUTAREA 0.04 LAYER via2  ;
    ANTENNAPARTIALMETALAREA 13.993 LAYER met3  ;
    ANTENNAPARTIALMETALSIDEAREA 75.096 LAYER met3  ;
    ANTENNAPARTIALCUTAREA 0.04 LAYER via3  ;
    ANTENNAPARTIALMETALAREA 62.1508 LAYER met4  ;
    ANTENNAPARTIALMETALSIDEAREA 327.816 LAYER met4  ;
    ANTENNAPARTIALCUTAREA 0.64 LAYER via4  ;
    ANTENNAPARTIALMETALAREA 15.856 LAYER met5  ;
    ANTENNAPARTIALMETALSIDEAREA 31.464 LAYER met5  ;
    ANTENNAMODEL OXIDE1 ;
    ANTENNAGATEAREA 1.0385 LAYER met5  ;
    ANTENNAMAXAREACAR 112.99 LAYER met5  ;
    ANTENNAMAXSIDEAREACAR 517.471 LAYER met5  ;
    PORT
      LAYER met2 ;
        RECT 41.100000 0.000000 41.240000 0.485000 ;
    END
  END wbs_dat_i[0]
  PIN wbs_adr_i[31]
    DIRECTION INPUT ;
    USE SIGNAL ;
    ANTENNAPARTIALMETALAREA 5.9723 LAYER met2  ;
    ANTENNAPARTIALMETALSIDEAREA 29.7535 LAYER met2  ;
    ANTENNAMODEL OXIDE1 ;
    ANTENNAGATEAREA 0.2475 LAYER met2  ;
    ANTENNAMAXAREACAR 103.872 LAYER met2  ;
    ANTENNAMAXSIDEAREACAR 516.352 LAYER met2  ;
    ANTENNAMAXCUTCAR 0.207677 LAYER via2  ;
    PORT
      LAYER met2 ;
        RECT 601.380000 0.000000 601.520000 0.485000 ;
    END
  END wbs_adr_i[31]
  PIN wbs_adr_i[30]
    DIRECTION INPUT ;
    USE SIGNAL ;
    ANTENNAPARTIALMETALAREA 6.0267 LAYER met2  ;
    ANTENNAPARTIALMETALSIDEAREA 29.9075 LAYER met2  ;
    ANTENNAMODEL OXIDE1 ;
    ANTENNAGATEAREA 0.2475 LAYER met2  ;
    ANTENNAMAXAREACAR 47.8506 LAYER met2  ;
    ANTENNAMAXSIDEAREACAR 231.527 LAYER met2  ;
    ANTENNAMAXCUTCAR 0.207677 LAYER via2  ;
    PORT
      LAYER met2 ;
        RECT 583.900000 0.000000 584.040000 0.485000 ;
    END
  END wbs_adr_i[30]
  PIN wbs_adr_i[29]
    DIRECTION INPUT ;
    USE SIGNAL ;
    ANTENNAPARTIALMETALAREA 8.4111 LAYER met2  ;
    ANTENNAPARTIALMETALSIDEAREA 41.9475 LAYER met2  ;
    ANTENNAMODEL OXIDE1 ;
    ANTENNAGATEAREA 0.2475 LAYER met2  ;
    ANTENNAMAXAREACAR 53.9495 LAYER met2  ;
    ANTENNAMAXSIDEAREACAR 265.511 LAYER met2  ;
    ANTENNAMAXCUTCAR 0.207677 LAYER via2  ;
    PORT
      LAYER met2 ;
        RECT 566.420000 0.000000 566.560000 0.485000 ;
    END
  END wbs_adr_i[29]
  PIN wbs_adr_i[28]
    DIRECTION INPUT ;
    USE SIGNAL ;
    ANTENNAPARTIALMETALAREA 8.2515 LAYER met2  ;
    ANTENNAPARTIALMETALSIDEAREA 41.1495 LAYER met2  ;
    ANTENNAMODEL OXIDE1 ;
    ANTENNAGATEAREA 0.2475 LAYER met2  ;
    ANTENNAMAXAREACAR 42.943 LAYER met2  ;
    ANTENNAMAXSIDEAREACAR 209.58 LAYER met2  ;
    ANTENNAMAXCUTCAR 0.207677 LAYER via2  ;
    PORT
      LAYER met2 ;
        RECT 548.940000 0.000000 549.080000 0.485000 ;
    END
  END wbs_adr_i[28]
  PIN wbs_adr_i[27]
    DIRECTION INPUT ;
    USE SIGNAL ;
    ANTENNAPARTIALMETALAREA 7.8763 LAYER met2  ;
    ANTENNAPARTIALMETALSIDEAREA 39.2735 LAYER met2  ;
    ANTENNAMODEL OXIDE1 ;
    ANTENNAGATEAREA 0.2475 LAYER met2  ;
    ANTENNAMAXAREACAR 40.7297 LAYER met2  ;
    ANTENNAMAXSIDEAREACAR 195.588 LAYER met2  ;
    ANTENNAMAXCUTCAR 0.207677 LAYER via2  ;
    PORT
      LAYER met2 ;
        RECT 531.460000 0.000000 531.600000 0.485000 ;
    END
  END wbs_adr_i[27]
  PIN wbs_adr_i[26]
    DIRECTION INPUT ;
    USE SIGNAL ;
    ANTENNAPARTIALMETALAREA 4.8719 LAYER met2  ;
    ANTENNAPARTIALMETALSIDEAREA 24.2515 LAYER met2  ;
    ANTENNAMODEL OXIDE1 ;
    ANTENNAGATEAREA 0.2475 LAYER met2  ;
    ANTENNAMAXAREACAR 41.7119 LAYER met2  ;
    ANTENNAMAXSIDEAREACAR 205.552 LAYER met2  ;
    ANTENNAMAXCUTCAR 0.207677 LAYER via2  ;
    PORT
      LAYER met2 ;
        RECT 513.980000 0.000000 514.120000 0.485000 ;
    END
  END wbs_adr_i[26]
  PIN wbs_adr_i[25]
    DIRECTION INPUT ;
    USE SIGNAL ;
    ANTENNAPARTIALMETALAREA 4.9195 LAYER met2  ;
    ANTENNAPARTIALMETALSIDEAREA 24.4895 LAYER met2  ;
    ANTENNAMODEL OXIDE1 ;
    ANTENNAGATEAREA 0.2475 LAYER met2  ;
    ANTENNAMAXAREACAR 33.9589 LAYER met2  ;
    ANTENNAMAXSIDEAREACAR 162.545 LAYER met2  ;
    ANTENNAMAXCUTCAR 0.207677 LAYER via2  ;
    PORT
      LAYER met2 ;
        RECT 496.500000 0.000000 496.640000 0.485000 ;
    END
  END wbs_adr_i[25]
  PIN wbs_adr_i[24]
    DIRECTION INPUT ;
    USE SIGNAL ;
    ANTENNAPARTIALMETALAREA 5.0483 LAYER met2  ;
    ANTENNAPARTIALMETALSIDEAREA 25.1335 LAYER met2  ;
    ANTENNAMODEL OXIDE1 ;
    ANTENNAGATEAREA 0.2475 LAYER met2  ;
    ANTENNAMAXAREACAR 24.6497 LAYER met2  ;
    ANTENNAMAXSIDEAREACAR 116.586 LAYER met2  ;
    ANTENNAMAXCUTCAR 0.207677 LAYER via2  ;
    PORT
      LAYER met2 ;
        RECT 479.020000 0.000000 479.160000 0.485000 ;
    END
  END wbs_adr_i[24]
  PIN wbs_adr_i[23]
    DIRECTION INPUT ;
    USE SIGNAL ;
    ANTENNAPARTIALMETALAREA 4.8243 LAYER met2  ;
    ANTENNAPARTIALMETALSIDEAREA 24.0135 LAYER met2  ;
    ANTENNAMODEL OXIDE1 ;
    ANTENNAGATEAREA 0.2475 LAYER met2  ;
    ANTENNAMAXAREACAR 29.8097 LAYER met2  ;
    ANTENNAMAXSIDEAREACAR 142.077 LAYER met2  ;
    ANTENNAMAXCUTCAR 0.207677 LAYER via2  ;
    PORT
      LAYER met2 ;
        RECT 461.540000 0.000000 461.680000 0.485000 ;
    END
  END wbs_adr_i[23]
  PIN wbs_adr_i[22]
    DIRECTION INPUT ;
    USE SIGNAL ;
    ANTENNAPARTIALMETALAREA 5.2051 LAYER met2  ;
    ANTENNAPARTIALMETALSIDEAREA 25.9175 LAYER met2  ;
    ANTENNAMODEL OXIDE1 ;
    ANTENNAGATEAREA 0.2475 LAYER met2  ;
    ANTENNAMAXAREACAR 34.0792 LAYER met2  ;
    ANTENNAMAXSIDEAREACAR 163.733 LAYER met2  ;
    ANTENNAMAXCUTCAR 0.207677 LAYER via2  ;
    PORT
      LAYER met2 ;
        RECT 443.600000 0.000000 443.740000 0.485000 ;
    END
  END wbs_adr_i[22]
  PIN wbs_adr_i[21]
    DIRECTION INPUT ;
    USE SIGNAL ;
    ANTENNAPARTIALMETALAREA 5.2051 LAYER met2  ;
    ANTENNAPARTIALMETALSIDEAREA 25.9175 LAYER met2  ;
    ANTENNAMODEL OXIDE1 ;
    ANTENNAGATEAREA 0.2475 LAYER met2  ;
    ANTENNAMAXAREACAR 23.0836 LAYER met2  ;
    ANTENNAMAXSIDEAREACAR 108.954 LAYER met2  ;
    ANTENNAMAXCUTCAR 0.207677 LAYER via2  ;
    PORT
      LAYER met2 ;
        RECT 426.120000 0.000000 426.260000 0.485000 ;
    END
  END wbs_adr_i[21]
  PIN wbs_adr_i[20]
    DIRECTION INPUT ;
    USE SIGNAL ;
    ANTENNAPARTIALMETALAREA 5.3381 LAYER met2  ;
    ANTENNAPARTIALMETALSIDEAREA 26.5825 LAYER met2  ;
    ANTENNAMODEL OXIDE1 ;
    ANTENNAGATEAREA 0.2475 LAYER met2  ;
    ANTENNAMAXAREACAR 33.6365 LAYER met2  ;
    ANTENNAMAXSIDEAREACAR 160.933 LAYER met2  ;
    ANTENNAMAXCUTCAR 0.207677 LAYER via2  ;
    PORT
      LAYER met2 ;
        RECT 408.640000 0.000000 408.780000 0.485000 ;
    END
  END wbs_adr_i[20]
  PIN wbs_adr_i[19]
    DIRECTION INPUT ;
    USE SIGNAL ;
    ANTENNAPARTIALMETALAREA 7.6325 LAYER met2  ;
    ANTENNAPARTIALMETALSIDEAREA 37.9365 LAYER met2  ;
    ANTENNAMODEL OXIDE1 ;
    ANTENNAGATEAREA 0.2475 LAYER met2  ;
    ANTENNAMAXAREACAR 34.3103 LAYER met2  ;
    ANTENNAMAXSIDEAREACAR 164.412 LAYER met2  ;
    ANTENNAMAXCUTCAR 0.207677 LAYER via2  ;
    PORT
      LAYER met2 ;
        RECT 391.160000 0.000000 391.300000 0.485000 ;
    END
  END wbs_adr_i[19]
  PIN wbs_adr_i[18]
    DIRECTION INPUT ;
    USE SIGNAL ;
    ANTENNAPARTIALMETALAREA 7.6061 LAYER met2  ;
    ANTENNAPARTIALMETALSIDEAREA 37.9225 LAYER met2  ;
    ANTENNAMODEL OXIDE1 ;
    ANTENNAGATEAREA 0.2475 LAYER met2  ;
    ANTENNAMAXAREACAR 42.8263 LAYER met2  ;
    ANTENNAMAXSIDEAREACAR 209.103 LAYER met2  ;
    ANTENNAMAXCUTCAR 0.207677 LAYER via2  ;
    PORT
      LAYER met2 ;
        RECT 373.680000 0.000000 373.820000 0.485000 ;
    END
  END wbs_adr_i[18]
  PIN wbs_adr_i[17]
    DIRECTION INPUT ;
    USE SIGNAL ;
    ANTENNAPARTIALMETALAREA 6.8571 LAYER met2  ;
    ANTENNAPARTIALMETALSIDEAREA 34.1775 LAYER met2  ;
    ANTENNAMODEL OXIDE1 ;
    ANTENNAGATEAREA 0.2475 LAYER met2  ;
    ANTENNAMAXAREACAR 39.2365 LAYER met2  ;
    ANTENNAMAXSIDEAREACAR 188.933 LAYER met2  ;
    ANTENNAMAXCUTCAR 0.207677 LAYER via2  ;
    PORT
      LAYER met2 ;
        RECT 356.200000 0.000000 356.340000 0.485000 ;
    END
  END wbs_adr_i[17]
  PIN wbs_adr_i[16]
    DIRECTION INPUT ;
    USE SIGNAL ;
    ANTENNAPARTIALMETALAREA 6.7283 LAYER met2  ;
    ANTENNAPARTIALMETALSIDEAREA 33.5335 LAYER met2  ;
    ANTENNAMODEL OXIDE1 ;
    ANTENNAGATEAREA 0.2475 LAYER met2  ;
    ANTENNAMAXAREACAR 30.1366 LAYER met2  ;
    ANTENNAMAXSIDEAREACAR 144.02 LAYER met2  ;
    ANTENNAMAXCUTCAR 0.207677 LAYER via2  ;
    PORT
      LAYER met2 ;
        RECT 338.720000 0.000000 338.860000 0.485000 ;
    END
  END wbs_adr_i[16]
  PIN wbs_adr_i[15]
    DIRECTION INPUT ;
    USE SIGNAL ;
    ANTENNAPARTIALMETALAREA 6.9187 LAYER met2  ;
    ANTENNAPARTIALMETALSIDEAREA 34.4855 LAYER met2  ;
    ANTENNAMODEL OXIDE1 ;
    ANTENNAGATEAREA 0.2475 LAYER met2  ;
    ANTENNAMAXAREACAR 40.6824 LAYER met2  ;
    ANTENNAMAXSIDEAREACAR 200.404 LAYER met2  ;
    ANTENNAMAXCUTCAR 0.207677 LAYER via2  ;
    PORT
      LAYER met2 ;
        RECT 321.240000 0.000000 321.380000 0.485000 ;
    END
  END wbs_adr_i[15]
  PIN wbs_adr_i[14]
    DIRECTION INPUT ;
    USE SIGNAL ;
    ANTENNAPARTIALMETALAREA 6.8445 LAYER met2  ;
    ANTENNAPARTIALMETALSIDEAREA 34.1145 LAYER met2  ;
    ANTENNAMODEL OXIDE1 ;
    ANTENNAGATEAREA 0.2475 LAYER met2  ;
    ANTENNAMAXAREACAR 49.6368 LAYER met2  ;
    ANTENNAMAXSIDEAREACAR 243.156 LAYER met2  ;
    ANTENNAMAXCUTCAR 0.207677 LAYER via2  ;
    PORT
      LAYER met2 ;
        RECT 303.760000 0.000000 303.900000 0.485000 ;
    END
  END wbs_adr_i[14]
  PIN wbs_adr_i[13]
    DIRECTION INPUT ;
    USE SIGNAL ;
    ANTENNAPARTIALMETALAREA 6.3027 LAYER met2  ;
    ANTENNAPARTIALMETALSIDEAREA 31.4055 LAYER met2  ;
    ANTENNAMODEL OXIDE1 ;
    ANTENNAGATEAREA 0.2475 LAYER met2  ;
    ANTENNAMAXAREACAR 29.8949 LAYER met2  ;
    ANTENNAMAXSIDEAREACAR 147.442 LAYER met2  ;
    ANTENNAMAXCUTCAR 0.207677 LAYER via2  ;
    PORT
      LAYER met2 ;
        RECT 286.280000 0.000000 286.420000 0.485000 ;
    END
  END wbs_adr_i[13]
  PIN wbs_adr_i[12]
    DIRECTION INPUT ;
    USE SIGNAL ;
    ANTENNAPARTIALMETALAREA 5.9667 LAYER met2  ;
    ANTENNAPARTIALMETALSIDEAREA 29.7255 LAYER met2  ;
    ANTENNAMODEL OXIDE1 ;
    ANTENNAGATEAREA 0.2475 LAYER met2  ;
    ANTENNAMAXAREACAR 31.3228 LAYER met2  ;
    ANTENNAMAXSIDEAREACAR 150.853 LAYER met2  ;
    ANTENNAMAXCUTCAR 0.207677 LAYER via2  ;
    PORT
      LAYER met2 ;
        RECT 268.800000 0.000000 268.940000 0.485000 ;
    END
  END wbs_adr_i[12]
  PIN wbs_adr_i[11]
    DIRECTION INPUT ;
    USE SIGNAL ;
    ANTENNAPARTIALMETALAREA 5.6599 LAYER met2  ;
    ANTENNAPARTIALMETALSIDEAREA 28.0735 LAYER met2  ;
    ANTENNAMODEL OXIDE1 ;
    ANTENNAGATEAREA 0.2475 LAYER met2  ;
    ANTENNAMAXAREACAR 28.2352 LAYER met2  ;
    ANTENNAMAXSIDEAREACAR 134.036 LAYER met2  ;
    ANTENNAMAXCUTCAR 0.207677 LAYER via2  ;
    PORT
      LAYER met2 ;
        RECT 251.320000 0.000000 251.460000 0.485000 ;
    END
  END wbs_adr_i[11]
  PIN wbs_adr_i[10]
    DIRECTION INPUT ;
    USE SIGNAL ;
    ANTENNAPARTIALMETALAREA 6.1987 LAYER met2  ;
    ANTENNAPARTIALMETALSIDEAREA 30.6495 LAYER met2  ;
    ANTENNAMODEL OXIDE1 ;
    ANTENNAGATEAREA 0.2475 LAYER met2  ;
    ANTENNAMAXAREACAR 27.0598 LAYER met2  ;
    ANTENNAMAXSIDEAREACAR 129.317 LAYER met2  ;
    ANTENNAMAXCUTCAR 0.207677 LAYER via2  ;
    PORT
      LAYER met2 ;
        RECT 233.840000 0.000000 233.980000 0.485000 ;
    END
  END wbs_adr_i[10]
  PIN wbs_adr_i[9]
    DIRECTION INPUT ;
    USE SIGNAL ;
    ANTENNAPARTIALMETALAREA 4.4435 LAYER met2  ;
    ANTENNAPARTIALMETALSIDEAREA 22.1095 LAYER met2  ;
    ANTENNAMODEL OXIDE1 ;
    ANTENNAGATEAREA 0.2475 LAYER met2  ;
    ANTENNAMAXAREACAR 25.3442 LAYER met2  ;
    ANTENNAMAXSIDEAREACAR 119.984 LAYER met2  ;
    ANTENNAMAXCUTCAR 0.207677 LAYER via2  ;
    PORT
      LAYER met2 ;
        RECT 216.360000 0.000000 216.500000 0.485000 ;
    END
  END wbs_adr_i[9]
  PIN wbs_adr_i[8]
    DIRECTION INPUT ;
    USE SIGNAL ;
    ANTENNAPARTIALMETALAREA 4.4435 LAYER met2  ;
    ANTENNAPARTIALMETALSIDEAREA 22.1095 LAYER met2  ;
    ANTENNAMODEL OXIDE1 ;
    ANTENNAGATEAREA 0.2475 LAYER met2  ;
    ANTENNAMAXAREACAR 24.2975 LAYER met2  ;
    ANTENNAMAXSIDEAREACAR 114.238 LAYER met2  ;
    ANTENNAMAXCUTCAR 0.207677 LAYER via2  ;
    PORT
      LAYER met2 ;
        RECT 198.880000 0.000000 199.020000 0.485000 ;
    END
  END wbs_adr_i[8]
  PIN wbs_adr_i[7]
    DIRECTION INPUT ;
    USE SIGNAL ;
    ANTENNAPARTIALMETALAREA 4.5651 LAYER met2  ;
    ANTENNAPARTIALMETALSIDEAREA 22.5995 LAYER met2  ;
    ANTENNAMODEL OXIDE1 ;
    ANTENNAGATEAREA 0.2475 LAYER met2  ;
    ANTENNAMAXAREACAR 20.4141 LAYER met2  ;
    ANTENNAMAXSIDEAREACAR 95.204 LAYER met2  ;
    ANTENNAMAXCUTCAR 0.207677 LAYER via2  ;
    PORT
      LAYER met2 ;
        RECT 181.400000 0.000000 181.540000 0.485000 ;
    END
  END wbs_adr_i[7]
  PIN wbs_adr_i[6]
    DIRECTION INPUT ;
    USE SIGNAL ;
    ANTENNAPARTIALMETALAREA 4.7795 LAYER met2  ;
    ANTENNAPARTIALMETALSIDEAREA 23.7895 LAYER met2  ;
    ANTENNAMODEL OXIDE1 ;
    ANTENNAGATEAREA 0.2475 LAYER met2  ;
    ANTENNAMAXAREACAR 44.9362 LAYER met2  ;
    ANTENNAMAXSIDEAREACAR 219.653 LAYER met2  ;
    ANTENNAMAXCUTCAR 0.207677 LAYER via2  ;
    PORT
      LAYER met2 ;
        RECT 163.920000 0.000000 164.060000 0.485000 ;
    END
  END wbs_adr_i[6]
  PIN wbs_adr_i[5]
    DIRECTION INPUT ;
    USE SIGNAL ;
    ANTENNAPARTIALMETALAREA 7.8229 LAYER met2  ;
    ANTENNAPARTIALMETALSIDEAREA 38.8885 LAYER met2  ;
    ANTENNAMODEL OXIDE1 ;
    ANTENNAGATEAREA 0.2475 LAYER met2  ;
    ANTENNAMAXAREACAR 32.6853 LAYER met2  ;
    ANTENNAMAXSIDEAREACAR 160.214 LAYER met2  ;
    ANTENNAMAXCUTCAR 0.207677 LAYER via2  ;
    PORT
      LAYER met2 ;
        RECT 146.440000 0.000000 146.580000 0.485000 ;
    END
  END wbs_adr_i[5]
  PIN wbs_adr_i[4]
    DIRECTION INPUT ;
    USE SIGNAL ;
    ANTENNAPARTIALMETALAREA 17.9433 LAYER met2  ;
    ANTENNAPARTIALMETALSIDEAREA 89.3725 LAYER met2  ;
    ANTENNAMODEL OXIDE1 ;
    ANTENNAGATEAREA 0.495 LAYER met2  ;
    ANTENNAMAXAREACAR 39.7335 LAYER met2  ;
    ANTENNAMAXSIDEAREACAR 195.94 LAYER met2  ;
    ANTENNAMAXCUTCAR 0.298586 LAYER via2  ;
    PORT
      LAYER met2 ;
        RECT 128.960000 0.000000 129.100000 0.485000 ;
    END
  END wbs_adr_i[4]
  PIN wbs_adr_i[3]
    DIRECTION INPUT ;
    USE SIGNAL ;
    ANTENNAPARTIALMETALAREA 2.9218 LAYER met2  ;
    ANTENNAPARTIALMETALSIDEAREA 14.448 LAYER met2  ;
    ANTENNAPARTIALCUTAREA 0.04 LAYER via2  ;
    ANTENNAPARTIALMETALAREA 114.94 LAYER met3  ;
    ANTENNAPARTIALMETALSIDEAREA 613.48 LAYER met3  ;
    ANTENNAPARTIALCUTAREA 0.04 LAYER via3  ;
    ANTENNAPARTIALMETALAREA 70.8366 LAYER met4  ;
    ANTENNAPARTIALMETALSIDEAREA 378.736 LAYER met4  ;
    ANTENNAMODEL OXIDE1 ;
    ANTENNAGATEAREA 2.475 LAYER met4  ;
    ANTENNAMAXAREACAR 55.9655 LAYER met4  ;
    ANTENNAMAXSIDEAREACAR 297.417 LAYER met4  ;
    ANTENNAMAXCUTCAR 0.692525 LAYER via4  ;
    PORT
      LAYER met2 ;
        RECT 105.500000 0.000000 105.640000 0.485000 ;
    END
  END wbs_adr_i[3]
  PIN wbs_adr_i[2]
    DIRECTION INPUT ;
    USE SIGNAL ;
    ANTENNAPARTIALMETALAREA 5.8994 LAYER met2  ;
    ANTENNAPARTIALMETALSIDEAREA 29.218 LAYER met2  ;
    ANTENNAPARTIALCUTAREA 0.04 LAYER via2  ;
    ANTENNAPARTIALMETALAREA 0.745 LAYER met3  ;
    ANTENNAPARTIALMETALSIDEAREA 4.44 LAYER met3  ;
    ANTENNAPARTIALCUTAREA 0.04 LAYER via3  ;
    ANTENNAPARTIALMETALAREA 65.7378 LAYER met4  ;
    ANTENNAPARTIALMETALSIDEAREA 351.072 LAYER met4  ;
    ANTENNAMODEL OXIDE1 ;
    ANTENNAGATEAREA 2.15 LAYER met4  ;
    ANTENNAMAXAREACAR 35.9184 LAYER met4  ;
    ANTENNAMAXSIDEAREACAR 186.053 LAYER met4  ;
    ANTENNAMAXCUTCAR 0.114503 LAYER via4  ;
    PORT
      LAYER met2 ;
        RECT 82.040000 0.000000 82.180000 0.485000 ;
    END
  END wbs_adr_i[2]
  PIN wbs_adr_i[1]
    DIRECTION INPUT ;
    USE SIGNAL ;
    ANTENNAPARTIALMETALAREA 7.9739 LAYER met2  ;
    ANTENNAPARTIALMETALSIDEAREA 39.5255 LAYER met2  ;
    ANTENNAMODEL OXIDE1 ;
    ANTENNAGATEAREA 0.2475 LAYER met2  ;
    ANTENNAMAXAREACAR 35.5581 LAYER met2  ;
    ANTENNAMAXSIDEAREACAR 169.588 LAYER met2  ;
    ANTENNAMAXCUTCAR 0.207677 LAYER via2  ;
    PORT
      LAYER met2 ;
        RECT 58.580000 0.000000 58.720000 0.485000 ;
    END
  END wbs_adr_i[1]
  PIN wbs_adr_i[0]
    DIRECTION INPUT ;
    USE SIGNAL ;
    ANTENNAPARTIALMETALAREA 5.5171 LAYER met2  ;
    ANTENNAPARTIALMETALSIDEAREA 27.3595 LAYER met2  ;
    ANTENNAMODEL OXIDE1 ;
    ANTENNAGATEAREA 0.2475 LAYER met2  ;
    ANTENNAMAXAREACAR 23.844 LAYER met2  ;
    ANTENNAMAXSIDEAREACAR 113.988 LAYER met2  ;
    ANTENNAMAXCUTCAR 0.207677 LAYER via2  ;
    PORT
      LAYER met2 ;
        RECT 35.580000 0.000000 35.720000 0.485000 ;
    END
  END wbs_adr_i[0]
  PIN wbs_ack_o
    DIRECTION OUTPUT ;
    USE SIGNAL ;
    ANTENNADIFFAREA 0.429 LAYER met2  ;
    ANTENNAPARTIALMETALAREA 12.4879 LAYER met2  ;
    ANTENNAPARTIALMETALSIDEAREA 62.3315 LAYER met2  ;
    PORT
      LAYER met2 ;
        RECT 12.120000 0.000000 12.260000 0.485000 ;
    END
  END wbs_ack_o
  PIN wbs_dat_o[31]
    DIRECTION OUTPUT ;
    USE SIGNAL ;
    ANTENNADIFFAREA 0.429 LAYER met2  ;
    ANTENNAPARTIALMETALAREA 12.4191 LAYER met2  ;
    ANTENNAPARTIALMETALSIDEAREA 61.8695 LAYER met2  ;
    PORT
      LAYER met2 ;
        RECT 612.880000 0.000000 613.020000 0.485000 ;
    END
  END wbs_dat_o[31]
  PIN wbs_dat_o[30]
    DIRECTION OUTPUT ;
    USE SIGNAL ;
    ANTENNADIFFAREA 0.429 LAYER met2  ;
    ANTENNAPARTIALMETALAREA 12.0007 LAYER met2  ;
    ANTENNAPARTIALMETALSIDEAREA 59.8955 LAYER met2  ;
    PORT
      LAYER met2 ;
        RECT 595.400000 0.000000 595.540000 0.485000 ;
    END
  END wbs_dat_o[30]
  PIN wbs_dat_o[29]
    DIRECTION OUTPUT ;
    USE SIGNAL ;
    ANTENNADIFFAREA 0.429 LAYER met2  ;
    ANTENNAPARTIALMETALAREA 11.0123 LAYER met2  ;
    ANTENNAPARTIALMETALSIDEAREA 54.9535 LAYER met2  ;
    PORT
      LAYER met2 ;
        RECT 577.920000 0.000000 578.060000 0.485000 ;
    END
  END wbs_dat_o[29]
  PIN wbs_dat_o[28]
    DIRECTION OUTPUT ;
    USE SIGNAL ;
    ANTENNADIFFAREA 0.429 LAYER met2  ;
    ANTENNAPARTIALMETALAREA 11.8271 LAYER met2  ;
    ANTENNAPARTIALMETALSIDEAREA 59.0275 LAYER met2  ;
    PORT
      LAYER met2 ;
        RECT 560.440000 0.000000 560.580000 0.485000 ;
    END
  END wbs_dat_o[28]
  PIN wbs_dat_o[27]
    DIRECTION OUTPUT ;
    USE SIGNAL ;
    ANTENNADIFFAREA 0.429 LAYER met2  ;
    ANTENNAPARTIALMETALAREA 12.5619 LAYER met2  ;
    ANTENNAPARTIALMETALSIDEAREA 62.5835 LAYER met2  ;
    PORT
      LAYER met2 ;
        RECT 542.960000 0.000000 543.100000 0.485000 ;
    END
  END wbs_dat_o[27]
  PIN wbs_dat_o[26]
    DIRECTION OUTPUT ;
    USE SIGNAL ;
    ANTENNADIFFAREA 0.429 LAYER met2  ;
    ANTENNAPARTIALMETALAREA 14.0291 LAYER met2  ;
    ANTENNAPARTIALMETALSIDEAREA 69.9195 LAYER met2  ;
    PORT
      LAYER met2 ;
        RECT 525.480000 0.000000 525.620000 0.485000 ;
    END
  END wbs_dat_o[26]
  PIN wbs_dat_o[25]
    DIRECTION OUTPUT ;
    USE SIGNAL ;
    ANTENNADIFFAREA 0.429 LAYER met2  ;
    ANTENNAPARTIALMETALAREA 12.7593 LAYER met2  ;
    ANTENNAPARTIALMETALSIDEAREA 63.5705 LAYER met2  ;
    PORT
      LAYER met2 ;
        RECT 508.000000 0.000000 508.140000 0.485000 ;
    END
  END wbs_dat_o[25]
  PIN wbs_dat_o[24]
    DIRECTION OUTPUT ;
    USE SIGNAL ;
    ANTENNADIFFAREA 0.429 LAYER met2  ;
    ANTENNAPARTIALMETALAREA 12.8671 LAYER met2  ;
    ANTENNAPARTIALMETALSIDEAREA 64.1095 LAYER met2  ;
    PORT
      LAYER met2 ;
        RECT 490.520000 0.000000 490.660000 0.485000 ;
    END
  END wbs_dat_o[24]
  PIN wbs_dat_o[23]
    DIRECTION OUTPUT ;
    USE SIGNAL ;
    ANTENNADIFFAREA 0.429 LAYER met2  ;
    ANTENNAPARTIALMETALAREA 14.7368 LAYER met2  ;
    ANTENNAPARTIALMETALSIDEAREA 73.458 LAYER met2  ;
    PORT
      LAYER met2 ;
        RECT 473.040000 0.000000 473.180000 0.485000 ;
    END
  END wbs_dat_o[23]
  PIN wbs_dat_o[22]
    DIRECTION OUTPUT ;
    USE SIGNAL ;
    ANTENNADIFFAREA 0.429 LAYER met2  ;
    ANTENNAPARTIALMETALAREA 14.5807 LAYER met2  ;
    ANTENNAPARTIALMETALSIDEAREA 72.6775 LAYER met2  ;
    PORT
      LAYER met2 ;
        RECT 455.560000 0.000000 455.700000 0.485000 ;
    END
  END wbs_dat_o[22]
  PIN wbs_dat_o[21]
    DIRECTION OUTPUT ;
    USE SIGNAL ;
    ANTENNADIFFAREA 0.429 LAYER met2  ;
    ANTENNAPARTIALMETALAREA 14.0235 LAYER met2  ;
    ANTENNAPARTIALMETALSIDEAREA 69.8915 LAYER met2  ;
    PORT
      LAYER met2 ;
        RECT 438.080000 0.000000 438.220000 0.485000 ;
    END
  END wbs_dat_o[21]
  PIN wbs_dat_o[20]
    DIRECTION OUTPUT ;
    USE SIGNAL ;
    ANTENNADIFFAREA 0.429 LAYER met2  ;
    ANTENNAPARTIALMETALAREA 14.3343 LAYER met2  ;
    ANTENNAPARTIALMETALSIDEAREA 71.4455 LAYER met2  ;
    PORT
      LAYER met2 ;
        RECT 420.600000 0.000000 420.740000 0.485000 ;
    END
  END wbs_dat_o[20]
  PIN wbs_dat_o[19]
    DIRECTION OUTPUT ;
    USE SIGNAL ;
    ANTENNADIFFAREA 0.429 LAYER met2  ;
    ANTENNAPARTIALMETALAREA 13.0925 LAYER met2  ;
    ANTENNAPARTIALMETALSIDEAREA 65.2365 LAYER met2  ;
    PORT
      LAYER met2 ;
        RECT 403.120000 0.000000 403.260000 0.485000 ;
    END
  END wbs_dat_o[19]
  PIN wbs_dat_o[18]
    DIRECTION OUTPUT ;
    USE SIGNAL ;
    ANTENNADIFFAREA 0.429 LAYER met2  ;
    ANTENNAPARTIALMETALAREA 15.9037 LAYER met2  ;
    ANTENNAPARTIALMETALSIDEAREA 79.2925 LAYER met2  ;
    PORT
      LAYER met2 ;
        RECT 385.640000 0.000000 385.780000 0.485000 ;
    END
  END wbs_dat_o[18]
  PIN wbs_dat_o[17]
    DIRECTION OUTPUT ;
    USE SIGNAL ;
    ANTENNADIFFAREA 0.429 LAYER met2  ;
    ANTENNAPARTIALMETALAREA 16.0631 LAYER met2  ;
    ANTENNAPARTIALMETALSIDEAREA 79.9715 LAYER met2  ;
    PORT
      LAYER met2 ;
        RECT 368.160000 0.000000 368.300000 0.485000 ;
    END
  END wbs_dat_o[17]
  PIN wbs_dat_o[16]
    DIRECTION OUTPUT ;
    USE SIGNAL ;
    ANTENNAPARTIALMETALAREA 11.225 LAYER met2  ;
    ANTENNAPARTIALMETALSIDEAREA 55.846 LAYER met2  ;
    ANTENNAPARTIALCUTAREA 0.04 LAYER via2  ;
    ANTENNAPARTIALMETALAREA 0.331 LAYER met3  ;
    ANTENNAPARTIALMETALSIDEAREA 2.232 LAYER met3  ;
    ANTENNAPARTIALCUTAREA 0.04 LAYER via3  ;
    ANTENNADIFFAREA 0.429 LAYER met4  ;
    ANTENNAPARTIALMETALAREA 1.2168 LAYER met4  ;
    ANTENNAPARTIALMETALSIDEAREA 6.96 LAYER met4  ;
    PORT
      LAYER met2 ;
        RECT 350.680000 0.000000 350.820000 0.485000 ;
    END
  END wbs_dat_o[16]
  PIN wbs_dat_o[15]
    DIRECTION OUTPUT ;
    USE SIGNAL ;
    ANTENNADIFFAREA 0.429 LAYER met2  ;
    ANTENNAPARTIALMETALAREA 13.5263 LAYER met2  ;
    ANTENNAPARTIALMETALSIDEAREA 67.2875 LAYER met2  ;
    PORT
      LAYER met2 ;
        RECT 332.740000 0.000000 332.880000 0.485000 ;
    END
  END wbs_dat_o[15]
  PIN wbs_dat_o[14]
    DIRECTION OUTPUT ;
    USE SIGNAL ;
    ANTENNAPARTIALMETALAREA 0.7868 LAYER met2  ;
    ANTENNAPARTIALMETALSIDEAREA 3.773 LAYER met2  ;
    ANTENNAPARTIALCUTAREA 0.04 LAYER via2  ;
    ANTENNADIFFAREA 0.429 LAYER met3  ;
    ANTENNAPARTIALMETALAREA 78.3168 LAYER met3  ;
    ANTENNAPARTIALMETALSIDEAREA 418.16 LAYER met3  ;
    PORT
      LAYER met2 ;
        RECT 315.260000 0.000000 315.400000 0.485000 ;
    END
  END wbs_dat_o[14]
  PIN wbs_dat_o[13]
    DIRECTION OUTPUT ;
    USE SIGNAL ;
    ANTENNAPARTIALMETALAREA 0.4452 LAYER met2  ;
    ANTENNAPARTIALMETALSIDEAREA 2.065 LAYER met2  ;
    ANTENNAPARTIALCUTAREA 0.04 LAYER via2  ;
    ANTENNAPARTIALMETALAREA 85.312 LAYER met3  ;
    ANTENNAPARTIALMETALSIDEAREA 455.464 LAYER met3  ;
    ANTENNAPARTIALCUTAREA 0.04 LAYER via3  ;
    ANTENNADIFFAREA 0.429 LAYER met4  ;
    ANTENNAPARTIALMETALAREA 33.0828 LAYER met4  ;
    ANTENNAPARTIALMETALSIDEAREA 176.912 LAYER met4  ;
    PORT
      LAYER met2 ;
        RECT 297.780000 0.000000 297.920000 0.485000 ;
    END
  END wbs_dat_o[13]
  PIN wbs_dat_o[12]
    DIRECTION OUTPUT ;
    USE SIGNAL ;
    ANTENNAPARTIALMETALAREA 0.616 LAYER met2  ;
    ANTENNAPARTIALMETALSIDEAREA 2.919 LAYER met2  ;
    ANTENNAPARTIALCUTAREA 0.04 LAYER via2  ;
    ANTENNAPARTIALMETALAREA 90.811 LAYER met3  ;
    ANTENNAPARTIALMETALSIDEAREA 484.792 LAYER met3  ;
    ANTENNAPARTIALCUTAREA 0.04 LAYER via3  ;
    ANTENNADIFFAREA 0.429 LAYER met4  ;
    ANTENNAPARTIALMETALAREA 28.6908 LAYER met4  ;
    ANTENNAPARTIALMETALSIDEAREA 153.488 LAYER met4  ;
    PORT
      LAYER met2 ;
        RECT 280.300000 0.000000 280.440000 0.485000 ;
    END
  END wbs_dat_o[12]
  PIN wbs_dat_o[11]
    DIRECTION OUTPUT ;
    USE SIGNAL ;
    ANTENNAPARTIALMETALAREA 1.022 LAYER met2  ;
    ANTENNAPARTIALMETALSIDEAREA 4.949 LAYER met2  ;
    ANTENNAPARTIALCUTAREA 0.04 LAYER via2  ;
    ANTENNADIFFAREA 0.429 LAYER met3  ;
    ANTENNAPARTIALMETALAREA 86.1348 LAYER met3  ;
    ANTENNAPARTIALMETALSIDEAREA 459.856 LAYER met3  ;
    PORT
      LAYER met2 ;
        RECT 262.820000 0.000000 262.960000 0.485000 ;
    END
  END wbs_dat_o[11]
  PIN wbs_dat_o[10]
    DIRECTION OUTPUT ;
    USE SIGNAL ;
    ANTENNAPARTIALMETALAREA 0.1099 LAYER met2  ;
    ANTENNAPARTIALMETALSIDEAREA 0.3885 LAYER met2  ;
    ANTENNAPARTIALCUTAREA 0.04 LAYER via2  ;
    ANTENNAPARTIALMETALAREA 92.638 LAYER met3  ;
    ANTENNAPARTIALMETALSIDEAREA 494.536 LAYER met3  ;
    ANTENNAPARTIALCUTAREA 0.04 LAYER via3  ;
    ANTENNADIFFAREA 0.429 LAYER met4  ;
    ANTENNAPARTIALMETALAREA 29.9958 LAYER met4  ;
    ANTENNAPARTIALMETALSIDEAREA 160.448 LAYER met4  ;
    PORT
      LAYER met2 ;
        RECT 245.340000 0.000000 245.480000 0.485000 ;
    END
  END wbs_dat_o[10]
  PIN wbs_dat_o[9]
    DIRECTION OUTPUT ;
    USE SIGNAL ;
    ANTENNADIFFAREA 0.429 LAYER met2  ;
    ANTENNAPARTIALMETALAREA 14.5947 LAYER met2  ;
    ANTENNAPARTIALMETALSIDEAREA 72.7475 LAYER met2  ;
    PORT
      LAYER met2 ;
        RECT 227.860000 0.000000 228.000000 0.485000 ;
    END
  END wbs_dat_o[9]
  PIN wbs_dat_o[8]
    DIRECTION OUTPUT ;
    USE SIGNAL ;
    ANTENNADIFFAREA 0.429 LAYER met2  ;
    ANTENNAPARTIALMETALAREA 15.7595 LAYER met2  ;
    ANTENNAPARTIALMETALSIDEAREA 78.5715 LAYER met2  ;
    PORT
      LAYER met2 ;
        RECT 210.380000 0.000000 210.520000 0.485000 ;
    END
  END wbs_dat_o[8]
  PIN wbs_dat_o[7]
    DIRECTION OUTPUT ;
    USE SIGNAL ;
    ANTENNADIFFAREA 0.429 LAYER met2  ;
    ANTENNAPARTIALMETALAREA 14.6801 LAYER met2  ;
    ANTENNAPARTIALMETALSIDEAREA 73.1745 LAYER met2  ;
    PORT
      LAYER met2 ;
        RECT 192.900000 0.000000 193.040000 0.485000 ;
    END
  END wbs_dat_o[7]
  PIN wbs_dat_o[6]
    DIRECTION OUTPUT ;
    USE SIGNAL ;
    ANTENNAPARTIALMETALAREA 1.1074 LAYER met2  ;
    ANTENNAPARTIALMETALSIDEAREA 5.376 LAYER met2  ;
    ANTENNAPARTIALCUTAREA 0.04 LAYER via2  ;
    ANTENNADIFFAREA 0.429 LAYER met3  ;
    ANTENNAPARTIALMETALAREA 130.802 LAYER met3  ;
    ANTENNAPARTIALMETALSIDEAREA 698.08 LAYER met3  ;
    PORT
      LAYER met2 ;
        RECT 175.420000 0.000000 175.560000 0.485000 ;
    END
  END wbs_dat_o[6]
  PIN wbs_dat_o[5]
    DIRECTION OUTPUT ;
    USE SIGNAL ;
    ANTENNAPARTIALMETALAREA 1.47 LAYER met2  ;
    ANTENNAPARTIALMETALSIDEAREA 7.189 LAYER met2  ;
    ANTENNAPARTIALCUTAREA 0.04 LAYER via2  ;
    ANTENNADIFFAREA 0.429 LAYER met3  ;
    ANTENNAPARTIALMETALAREA 109.001 LAYER met3  ;
    ANTENNAPARTIALMETALSIDEAREA 581.808 LAYER met3  ;
    PORT
      LAYER met2 ;
        RECT 157.940000 0.000000 158.080000 0.485000 ;
    END
  END wbs_dat_o[5]
  PIN wbs_dat_o[4]
    DIRECTION OUTPUT ;
    USE SIGNAL ;
    ANTENNAPARTIALMETALAREA 1.2992 LAYER met2  ;
    ANTENNAPARTIALMETALSIDEAREA 6.335 LAYER met2  ;
    ANTENNAPARTIALCUTAREA 0.04 LAYER via2  ;
    ANTENNAPARTIALMETALAREA 137.683 LAYER met3  ;
    ANTENNAPARTIALMETALSIDEAREA 734.776 LAYER met3  ;
    ANTENNAPARTIALCUTAREA 0.04 LAYER via3  ;
    ANTENNADIFFAREA 0.429 LAYER met4  ;
    ANTENNAPARTIALMETALAREA 29.6298 LAYER met4  ;
    ANTENNAPARTIALMETALSIDEAREA 158.496 LAYER met4  ;
    PORT
      LAYER met2 ;
        RECT 140.460000 0.000000 140.600000 0.485000 ;
    END
  END wbs_dat_o[4]
  PIN wbs_dat_o[3]
    DIRECTION OUTPUT ;
    USE SIGNAL ;
    ANTENNADIFFAREA 0.429 LAYER met2  ;
    ANTENNAPARTIALMETALAREA 14.9683 LAYER met2  ;
    ANTENNAPARTIALMETALSIDEAREA 74.4975 LAYER met2  ;
    PORT
      LAYER met2 ;
        RECT 117.000000 0.000000 117.140000 0.485000 ;
    END
  END wbs_dat_o[3]
  PIN wbs_dat_o[2]
    DIRECTION OUTPUT ;
    USE SIGNAL ;
    ANTENNADIFFAREA 0.429 LAYER met2  ;
    ANTENNAPARTIALMETALAREA 15.0441 LAYER met2  ;
    ANTENNAPARTIALMETALSIDEAREA 74.9945 LAYER met2  ;
    PORT
      LAYER met2 ;
        RECT 93.540000 0.000000 93.680000 0.485000 ;
    END
  END wbs_dat_o[2]
  PIN wbs_dat_o[1]
    DIRECTION OUTPUT ;
    USE SIGNAL ;
    ANTENNAPARTIALMETALAREA 1.6408 LAYER met2  ;
    ANTENNAPARTIALMETALSIDEAREA 8.043 LAYER met2  ;
    ANTENNAPARTIALCUTAREA 0.04 LAYER via2  ;
    ANTENNAPARTIALMETALAREA 161.653 LAYER met3  ;
    ANTENNAPARTIALMETALSIDEAREA 862.616 LAYER met3  ;
    ANTENNAPARTIALCUTAREA 0.04 LAYER via3  ;
    ANTENNADIFFAREA 0.429 LAYER met4  ;
    ANTENNAPARTIALMETALAREA 28.1418 LAYER met4  ;
    ANTENNAPARTIALMETALSIDEAREA 150.56 LAYER met4  ;
    PORT
      LAYER met2 ;
        RECT 70.540000 0.000000 70.680000 0.485000 ;
    END
  END wbs_dat_o[1]
  PIN wbs_dat_o[0]
    DIRECTION OUTPUT ;
    USE SIGNAL ;
    ANTENNADIFFAREA 0.429 LAYER met2  ;
    ANTENNAPARTIALMETALAREA 13.8499 LAYER met2  ;
    ANTENNAPARTIALMETALSIDEAREA 69.0235 LAYER met2  ;
    PORT
      LAYER met2 ;
        RECT 47.080000 0.000000 47.220000 0.485000 ;
    END
  END wbs_dat_o[0]
  PIN la_data_in[127]
    DIRECTION INPUT ;
    USE SIGNAL ;
    PORT
      LAYER met2 ;
        RECT 2841.580000 0.000000 2841.720000 0.485000 ;
    END
  END la_data_in[127]
  PIN la_data_in[126]
    DIRECTION INPUT ;
    USE SIGNAL ;
    PORT
      LAYER met2 ;
        RECT 2824.100000 0.000000 2824.240000 0.485000 ;
    END
  END la_data_in[126]
  PIN la_data_in[125]
    DIRECTION INPUT ;
    USE SIGNAL ;
    PORT
      LAYER met2 ;
        RECT 2806.620000 0.000000 2806.760000 0.485000 ;
    END
  END la_data_in[125]
  PIN la_data_in[124]
    DIRECTION INPUT ;
    USE SIGNAL ;
    PORT
      LAYER met2 ;
        RECT 2789.140000 0.000000 2789.280000 0.485000 ;
    END
  END la_data_in[124]
  PIN la_data_in[123]
    DIRECTION INPUT ;
    USE SIGNAL ;
    PORT
      LAYER met2 ;
        RECT 2771.660000 0.000000 2771.800000 0.485000 ;
    END
  END la_data_in[123]
  PIN la_data_in[122]
    DIRECTION INPUT ;
    USE SIGNAL ;
    PORT
      LAYER met2 ;
        RECT 2754.180000 0.000000 2754.320000 0.485000 ;
    END
  END la_data_in[122]
  PIN la_data_in[121]
    DIRECTION INPUT ;
    USE SIGNAL ;
    PORT
      LAYER met2 ;
        RECT 2736.700000 0.000000 2736.840000 0.485000 ;
    END
  END la_data_in[121]
  PIN la_data_in[120]
    DIRECTION INPUT ;
    USE SIGNAL ;
    PORT
      LAYER met2 ;
        RECT 2719.220000 0.000000 2719.360000 0.485000 ;
    END
  END la_data_in[120]
  PIN la_data_in[119]
    DIRECTION INPUT ;
    USE SIGNAL ;
    PORT
      LAYER met2 ;
        RECT 2701.740000 0.000000 2701.880000 0.485000 ;
    END
  END la_data_in[119]
  PIN la_data_in[118]
    DIRECTION INPUT ;
    USE SIGNAL ;
    PORT
      LAYER met2 ;
        RECT 2684.260000 0.000000 2684.400000 0.485000 ;
    END
  END la_data_in[118]
  PIN la_data_in[117]
    DIRECTION INPUT ;
    USE SIGNAL ;
    PORT
      LAYER met2 ;
        RECT 2666.780000 0.000000 2666.920000 0.485000 ;
    END
  END la_data_in[117]
  PIN la_data_in[116]
    DIRECTION INPUT ;
    USE SIGNAL ;
    PORT
      LAYER met2 ;
        RECT 2649.300000 0.000000 2649.440000 0.485000 ;
    END
  END la_data_in[116]
  PIN la_data_in[115]
    DIRECTION INPUT ;
    USE SIGNAL ;
    PORT
      LAYER met2 ;
        RECT 2631.820000 0.000000 2631.960000 0.485000 ;
    END
  END la_data_in[115]
  PIN la_data_in[114]
    DIRECTION INPUT ;
    USE SIGNAL ;
    PORT
      LAYER met2 ;
        RECT 2614.340000 0.000000 2614.480000 0.485000 ;
    END
  END la_data_in[114]
  PIN la_data_in[113]
    DIRECTION INPUT ;
    USE SIGNAL ;
    PORT
      LAYER met2 ;
        RECT 2596.860000 0.000000 2597.000000 0.485000 ;
    END
  END la_data_in[113]
  PIN la_data_in[112]
    DIRECTION INPUT ;
    USE SIGNAL ;
    PORT
      LAYER met2 ;
        RECT 2579.380000 0.000000 2579.520000 0.485000 ;
    END
  END la_data_in[112]
  PIN la_data_in[111]
    DIRECTION INPUT ;
    USE SIGNAL ;
    PORT
      LAYER met2 ;
        RECT 2561.900000 0.000000 2562.040000 0.485000 ;
    END
  END la_data_in[111]
  PIN la_data_in[110]
    DIRECTION INPUT ;
    USE SIGNAL ;
    PORT
      LAYER met2 ;
        RECT 2544.420000 0.000000 2544.560000 0.485000 ;
    END
  END la_data_in[110]
  PIN la_data_in[109]
    DIRECTION INPUT ;
    USE SIGNAL ;
    PORT
      LAYER met2 ;
        RECT 2526.480000 0.000000 2526.620000 0.485000 ;
    END
  END la_data_in[109]
  PIN la_data_in[108]
    DIRECTION INPUT ;
    USE SIGNAL ;
    PORT
      LAYER met2 ;
        RECT 2509.000000 0.000000 2509.140000 0.485000 ;
    END
  END la_data_in[108]
  PIN la_data_in[107]
    DIRECTION INPUT ;
    USE SIGNAL ;
    PORT
      LAYER met2 ;
        RECT 2491.520000 0.000000 2491.660000 0.485000 ;
    END
  END la_data_in[107]
  PIN la_data_in[106]
    DIRECTION INPUT ;
    USE SIGNAL ;
    PORT
      LAYER met2 ;
        RECT 2474.040000 0.000000 2474.180000 0.485000 ;
    END
  END la_data_in[106]
  PIN la_data_in[105]
    DIRECTION INPUT ;
    USE SIGNAL ;
    PORT
      LAYER met2 ;
        RECT 2456.560000 0.000000 2456.700000 0.485000 ;
    END
  END la_data_in[105]
  PIN la_data_in[104]
    DIRECTION INPUT ;
    USE SIGNAL ;
    PORT
      LAYER met2 ;
        RECT 2439.080000 0.000000 2439.220000 0.485000 ;
    END
  END la_data_in[104]
  PIN la_data_in[103]
    DIRECTION INPUT ;
    USE SIGNAL ;
    PORT
      LAYER met2 ;
        RECT 2421.600000 0.000000 2421.740000 0.485000 ;
    END
  END la_data_in[103]
  PIN la_data_in[102]
    DIRECTION INPUT ;
    USE SIGNAL ;
    PORT
      LAYER met2 ;
        RECT 2404.120000 0.000000 2404.260000 0.485000 ;
    END
  END la_data_in[102]
  PIN la_data_in[101]
    DIRECTION INPUT ;
    USE SIGNAL ;
    PORT
      LAYER met2 ;
        RECT 2386.640000 0.000000 2386.780000 0.485000 ;
    END
  END la_data_in[101]
  PIN la_data_in[100]
    DIRECTION INPUT ;
    USE SIGNAL ;
    PORT
      LAYER met2 ;
        RECT 2369.160000 0.000000 2369.300000 0.485000 ;
    END
  END la_data_in[100]
  PIN la_data_in[99]
    DIRECTION INPUT ;
    USE SIGNAL ;
    PORT
      LAYER met2 ;
        RECT 2351.680000 0.000000 2351.820000 0.485000 ;
    END
  END la_data_in[99]
  PIN la_data_in[98]
    DIRECTION INPUT ;
    USE SIGNAL ;
    PORT
      LAYER met2 ;
        RECT 2334.200000 0.000000 2334.340000 0.485000 ;
    END
  END la_data_in[98]
  PIN la_data_in[97]
    DIRECTION INPUT ;
    USE SIGNAL ;
    PORT
      LAYER met2 ;
        RECT 2316.720000 0.000000 2316.860000 0.485000 ;
    END
  END la_data_in[97]
  PIN la_data_in[96]
    DIRECTION INPUT ;
    USE SIGNAL ;
    PORT
      LAYER met2 ;
        RECT 2299.240000 0.000000 2299.380000 0.485000 ;
    END
  END la_data_in[96]
  PIN la_data_in[95]
    DIRECTION INPUT ;
    USE SIGNAL ;
    PORT
      LAYER met2 ;
        RECT 2281.760000 0.000000 2281.900000 0.485000 ;
    END
  END la_data_in[95]
  PIN la_data_in[94]
    DIRECTION INPUT ;
    USE SIGNAL ;
    PORT
      LAYER met2 ;
        RECT 2264.280000 0.000000 2264.420000 0.485000 ;
    END
  END la_data_in[94]
  PIN la_data_in[93]
    DIRECTION INPUT ;
    USE SIGNAL ;
    PORT
      LAYER met2 ;
        RECT 2246.800000 0.000000 2246.940000 0.485000 ;
    END
  END la_data_in[93]
  PIN la_data_in[92]
    DIRECTION INPUT ;
    USE SIGNAL ;
    PORT
      LAYER met2 ;
        RECT 2229.320000 0.000000 2229.460000 0.485000 ;
    END
  END la_data_in[92]
  PIN la_data_in[91]
    DIRECTION INPUT ;
    USE SIGNAL ;
    PORT
      LAYER met2 ;
        RECT 2211.840000 0.000000 2211.980000 0.485000 ;
    END
  END la_data_in[91]
  PIN la_data_in[90]
    DIRECTION INPUT ;
    USE SIGNAL ;
    PORT
      LAYER met2 ;
        RECT 2194.360000 0.000000 2194.500000 0.485000 ;
    END
  END la_data_in[90]
  PIN la_data_in[89]
    DIRECTION INPUT ;
    USE SIGNAL ;
    PORT
      LAYER met2 ;
        RECT 2176.420000 0.000000 2176.560000 0.485000 ;
    END
  END la_data_in[89]
  PIN la_data_in[88]
    DIRECTION INPUT ;
    USE SIGNAL ;
    PORT
      LAYER met2 ;
        RECT 2158.940000 0.000000 2159.080000 0.485000 ;
    END
  END la_data_in[88]
  PIN la_data_in[87]
    DIRECTION INPUT ;
    USE SIGNAL ;
    PORT
      LAYER met2 ;
        RECT 2141.460000 0.000000 2141.600000 0.485000 ;
    END
  END la_data_in[87]
  PIN la_data_in[86]
    DIRECTION INPUT ;
    USE SIGNAL ;
    PORT
      LAYER met2 ;
        RECT 2123.980000 0.000000 2124.120000 0.485000 ;
    END
  END la_data_in[86]
  PIN la_data_in[85]
    DIRECTION INPUT ;
    USE SIGNAL ;
    PORT
      LAYER met2 ;
        RECT 2106.500000 0.000000 2106.640000 0.485000 ;
    END
  END la_data_in[85]
  PIN la_data_in[84]
    DIRECTION INPUT ;
    USE SIGNAL ;
    PORT
      LAYER met2 ;
        RECT 2089.020000 0.000000 2089.160000 0.485000 ;
    END
  END la_data_in[84]
  PIN la_data_in[83]
    DIRECTION INPUT ;
    USE SIGNAL ;
    PORT
      LAYER met2 ;
        RECT 2071.540000 0.000000 2071.680000 0.485000 ;
    END
  END la_data_in[83]
  PIN la_data_in[82]
    DIRECTION INPUT ;
    USE SIGNAL ;
    PORT
      LAYER met2 ;
        RECT 2054.060000 0.000000 2054.200000 0.485000 ;
    END
  END la_data_in[82]
  PIN la_data_in[81]
    DIRECTION INPUT ;
    USE SIGNAL ;
    PORT
      LAYER met2 ;
        RECT 2036.580000 0.000000 2036.720000 0.485000 ;
    END
  END la_data_in[81]
  PIN la_data_in[80]
    DIRECTION INPUT ;
    USE SIGNAL ;
    PORT
      LAYER met2 ;
        RECT 2019.100000 0.000000 2019.240000 0.485000 ;
    END
  END la_data_in[80]
  PIN la_data_in[79]
    DIRECTION INPUT ;
    USE SIGNAL ;
    PORT
      LAYER met2 ;
        RECT 2001.620000 0.000000 2001.760000 0.485000 ;
    END
  END la_data_in[79]
  PIN la_data_in[78]
    DIRECTION INPUT ;
    USE SIGNAL ;
    PORT
      LAYER met2 ;
        RECT 1984.140000 0.000000 1984.280000 0.485000 ;
    END
  END la_data_in[78]
  PIN la_data_in[77]
    DIRECTION INPUT ;
    USE SIGNAL ;
    PORT
      LAYER met2 ;
        RECT 1966.660000 0.000000 1966.800000 0.485000 ;
    END
  END la_data_in[77]
  PIN la_data_in[76]
    DIRECTION INPUT ;
    USE SIGNAL ;
    PORT
      LAYER met2 ;
        RECT 1949.180000 0.000000 1949.320000 0.485000 ;
    END
  END la_data_in[76]
  PIN la_data_in[75]
    DIRECTION INPUT ;
    USE SIGNAL ;
    PORT
      LAYER met2 ;
        RECT 1931.700000 0.000000 1931.840000 0.485000 ;
    END
  END la_data_in[75]
  PIN la_data_in[74]
    DIRECTION INPUT ;
    USE SIGNAL ;
    PORT
      LAYER met2 ;
        RECT 1914.220000 0.000000 1914.360000 0.485000 ;
    END
  END la_data_in[74]
  PIN la_data_in[73]
    DIRECTION INPUT ;
    USE SIGNAL ;
    PORT
      LAYER met2 ;
        RECT 1896.740000 0.000000 1896.880000 0.485000 ;
    END
  END la_data_in[73]
  PIN la_data_in[72]
    DIRECTION INPUT ;
    USE SIGNAL ;
    PORT
      LAYER met2 ;
        RECT 1879.260000 0.000000 1879.400000 0.485000 ;
    END
  END la_data_in[72]
  PIN la_data_in[71]
    DIRECTION INPUT ;
    USE SIGNAL ;
    PORT
      LAYER met2 ;
        RECT 1861.780000 0.000000 1861.920000 0.485000 ;
    END
  END la_data_in[71]
  PIN la_data_in[70]
    DIRECTION INPUT ;
    USE SIGNAL ;
    PORT
      LAYER met2 ;
        RECT 1844.300000 0.000000 1844.440000 0.485000 ;
    END
  END la_data_in[70]
  PIN la_data_in[69]
    DIRECTION INPUT ;
    USE SIGNAL ;
    PORT
      LAYER met2 ;
        RECT 1826.360000 0.000000 1826.500000 0.485000 ;
    END
  END la_data_in[69]
  PIN la_data_in[68]
    DIRECTION INPUT ;
    USE SIGNAL ;
    PORT
      LAYER met2 ;
        RECT 1808.880000 0.000000 1809.020000 0.485000 ;
    END
  END la_data_in[68]
  PIN la_data_in[67]
    DIRECTION INPUT ;
    USE SIGNAL ;
    PORT
      LAYER met2 ;
        RECT 1791.400000 0.000000 1791.540000 0.485000 ;
    END
  END la_data_in[67]
  PIN la_data_in[66]
    DIRECTION INPUT ;
    USE SIGNAL ;
    PORT
      LAYER met2 ;
        RECT 1773.920000 0.000000 1774.060000 0.485000 ;
    END
  END la_data_in[66]
  PIN la_data_in[65]
    DIRECTION INPUT ;
    USE SIGNAL ;
    PORT
      LAYER met2 ;
        RECT 1756.440000 0.000000 1756.580000 0.485000 ;
    END
  END la_data_in[65]
  PIN la_data_in[64]
    DIRECTION INPUT ;
    USE SIGNAL ;
    PORT
      LAYER met2 ;
        RECT 1738.960000 0.000000 1739.100000 0.485000 ;
    END
  END la_data_in[64]
  PIN la_data_in[63]
    DIRECTION INPUT ;
    USE SIGNAL ;
    PORT
      LAYER met2 ;
        RECT 1721.480000 0.000000 1721.620000 0.485000 ;
    END
  END la_data_in[63]
  PIN la_data_in[62]
    DIRECTION INPUT ;
    USE SIGNAL ;
    PORT
      LAYER met2 ;
        RECT 1704.000000 0.000000 1704.140000 0.485000 ;
    END
  END la_data_in[62]
  PIN la_data_in[61]
    DIRECTION INPUT ;
    USE SIGNAL ;
    PORT
      LAYER met2 ;
        RECT 1686.520000 0.000000 1686.660000 0.485000 ;
    END
  END la_data_in[61]
  PIN la_data_in[60]
    DIRECTION INPUT ;
    USE SIGNAL ;
    PORT
      LAYER met2 ;
        RECT 1669.040000 0.000000 1669.180000 0.485000 ;
    END
  END la_data_in[60]
  PIN la_data_in[59]
    DIRECTION INPUT ;
    USE SIGNAL ;
    PORT
      LAYER met2 ;
        RECT 1651.560000 0.000000 1651.700000 0.485000 ;
    END
  END la_data_in[59]
  PIN la_data_in[58]
    DIRECTION INPUT ;
    USE SIGNAL ;
    PORT
      LAYER met2 ;
        RECT 1634.080000 0.000000 1634.220000 0.485000 ;
    END
  END la_data_in[58]
  PIN la_data_in[57]
    DIRECTION INPUT ;
    USE SIGNAL ;
    PORT
      LAYER met2 ;
        RECT 1616.600000 0.000000 1616.740000 0.485000 ;
    END
  END la_data_in[57]
  PIN la_data_in[56]
    DIRECTION INPUT ;
    USE SIGNAL ;
    PORT
      LAYER met2 ;
        RECT 1599.120000 0.000000 1599.260000 0.485000 ;
    END
  END la_data_in[56]
  PIN la_data_in[55]
    DIRECTION INPUT ;
    USE SIGNAL ;
    PORT
      LAYER met2 ;
        RECT 1581.640000 0.000000 1581.780000 0.485000 ;
    END
  END la_data_in[55]
  PIN la_data_in[54]
    DIRECTION INPUT ;
    USE SIGNAL ;
    PORT
      LAYER met2 ;
        RECT 1564.160000 0.000000 1564.300000 0.485000 ;
    END
  END la_data_in[54]
  PIN la_data_in[53]
    DIRECTION INPUT ;
    USE SIGNAL ;
    PORT
      LAYER met2 ;
        RECT 1546.680000 0.000000 1546.820000 0.485000 ;
    END
  END la_data_in[53]
  PIN la_data_in[52]
    DIRECTION INPUT ;
    USE SIGNAL ;
    PORT
      LAYER met2 ;
        RECT 1529.200000 0.000000 1529.340000 0.485000 ;
    END
  END la_data_in[52]
  PIN la_data_in[51]
    DIRECTION INPUT ;
    USE SIGNAL ;
    PORT
      LAYER met2 ;
        RECT 1511.720000 0.000000 1511.860000 0.485000 ;
    END
  END la_data_in[51]
  PIN la_data_in[50]
    DIRECTION INPUT ;
    USE SIGNAL ;
    PORT
      LAYER met2 ;
        RECT 1493.780000 0.000000 1493.920000 0.485000 ;
    END
  END la_data_in[50]
  PIN la_data_in[49]
    DIRECTION INPUT ;
    USE SIGNAL ;
    PORT
      LAYER met2 ;
        RECT 1476.300000 0.000000 1476.440000 0.485000 ;
    END
  END la_data_in[49]
  PIN la_data_in[48]
    DIRECTION INPUT ;
    USE SIGNAL ;
    PORT
      LAYER met2 ;
        RECT 1458.820000 0.000000 1458.960000 0.485000 ;
    END
  END la_data_in[48]
  PIN la_data_in[47]
    DIRECTION INPUT ;
    USE SIGNAL ;
    PORT
      LAYER met2 ;
        RECT 1441.340000 0.000000 1441.480000 0.485000 ;
    END
  END la_data_in[47]
  PIN la_data_in[46]
    DIRECTION INPUT ;
    USE SIGNAL ;
    PORT
      LAYER met2 ;
        RECT 1423.860000 0.000000 1424.000000 0.485000 ;
    END
  END la_data_in[46]
  PIN la_data_in[45]
    DIRECTION INPUT ;
    USE SIGNAL ;
    PORT
      LAYER met2 ;
        RECT 1406.380000 0.000000 1406.520000 0.485000 ;
    END
  END la_data_in[45]
  PIN la_data_in[44]
    DIRECTION INPUT ;
    USE SIGNAL ;
    PORT
      LAYER met2 ;
        RECT 1388.900000 0.000000 1389.040000 0.485000 ;
    END
  END la_data_in[44]
  PIN la_data_in[43]
    DIRECTION INPUT ;
    USE SIGNAL ;
    PORT
      LAYER met2 ;
        RECT 1371.420000 0.000000 1371.560000 0.485000 ;
    END
  END la_data_in[43]
  PIN la_data_in[42]
    DIRECTION INPUT ;
    USE SIGNAL ;
    PORT
      LAYER met2 ;
        RECT 1353.940000 0.000000 1354.080000 0.485000 ;
    END
  END la_data_in[42]
  PIN la_data_in[41]
    DIRECTION INPUT ;
    USE SIGNAL ;
    PORT
      LAYER met2 ;
        RECT 1336.460000 0.000000 1336.600000 0.485000 ;
    END
  END la_data_in[41]
  PIN la_data_in[40]
    DIRECTION INPUT ;
    USE SIGNAL ;
    PORT
      LAYER met2 ;
        RECT 1318.980000 0.000000 1319.120000 0.485000 ;
    END
  END la_data_in[40]
  PIN la_data_in[39]
    DIRECTION INPUT ;
    USE SIGNAL ;
    PORT
      LAYER met2 ;
        RECT 1301.500000 0.000000 1301.640000 0.485000 ;
    END
  END la_data_in[39]
  PIN la_data_in[38]
    DIRECTION INPUT ;
    USE SIGNAL ;
    PORT
      LAYER met2 ;
        RECT 1284.020000 0.000000 1284.160000 0.485000 ;
    END
  END la_data_in[38]
  PIN la_data_in[37]
    DIRECTION INPUT ;
    USE SIGNAL ;
    PORT
      LAYER met2 ;
        RECT 1266.540000 0.000000 1266.680000 0.485000 ;
    END
  END la_data_in[37]
  PIN la_data_in[36]
    DIRECTION INPUT ;
    USE SIGNAL ;
    PORT
      LAYER met2 ;
        RECT 1249.060000 0.000000 1249.200000 0.485000 ;
    END
  END la_data_in[36]
  PIN la_data_in[35]
    DIRECTION INPUT ;
    USE SIGNAL ;
    PORT
      LAYER met2 ;
        RECT 1231.580000 0.000000 1231.720000 0.485000 ;
    END
  END la_data_in[35]
  PIN la_data_in[34]
    DIRECTION INPUT ;
    USE SIGNAL ;
    PORT
      LAYER met2 ;
        RECT 1214.100000 0.000000 1214.240000 0.485000 ;
    END
  END la_data_in[34]
  PIN la_data_in[33]
    DIRECTION INPUT ;
    USE SIGNAL ;
    PORT
      LAYER met2 ;
        RECT 1196.620000 0.000000 1196.760000 0.485000 ;
    END
  END la_data_in[33]
  PIN la_data_in[32]
    DIRECTION INPUT ;
    USE SIGNAL ;
    PORT
      LAYER met2 ;
        RECT 1179.140000 0.000000 1179.280000 0.485000 ;
    END
  END la_data_in[32]
  PIN la_data_in[31]
    DIRECTION INPUT ;
    USE SIGNAL ;
    PORT
      LAYER met2 ;
        RECT 1161.660000 0.000000 1161.800000 0.485000 ;
    END
  END la_data_in[31]
  PIN la_data_in[30]
    DIRECTION INPUT ;
    USE SIGNAL ;
    PORT
      LAYER met2 ;
        RECT 1143.720000 0.000000 1143.860000 0.485000 ;
    END
  END la_data_in[30]
  PIN la_data_in[29]
    DIRECTION INPUT ;
    USE SIGNAL ;
    PORT
      LAYER met2 ;
        RECT 1126.240000 0.000000 1126.380000 0.485000 ;
    END
  END la_data_in[29]
  PIN la_data_in[28]
    DIRECTION INPUT ;
    USE SIGNAL ;
    PORT
      LAYER met2 ;
        RECT 1108.760000 0.000000 1108.900000 0.485000 ;
    END
  END la_data_in[28]
  PIN la_data_in[27]
    DIRECTION INPUT ;
    USE SIGNAL ;
    PORT
      LAYER met2 ;
        RECT 1091.280000 0.000000 1091.420000 0.485000 ;
    END
  END la_data_in[27]
  PIN la_data_in[26]
    DIRECTION INPUT ;
    USE SIGNAL ;
    PORT
      LAYER met2 ;
        RECT 1073.800000 0.000000 1073.940000 0.485000 ;
    END
  END la_data_in[26]
  PIN la_data_in[25]
    DIRECTION INPUT ;
    USE SIGNAL ;
    PORT
      LAYER met2 ;
        RECT 1056.320000 0.000000 1056.460000 0.485000 ;
    END
  END la_data_in[25]
  PIN la_data_in[24]
    DIRECTION INPUT ;
    USE SIGNAL ;
    PORT
      LAYER met2 ;
        RECT 1038.840000 0.000000 1038.980000 0.485000 ;
    END
  END la_data_in[24]
  PIN la_data_in[23]
    DIRECTION INPUT ;
    USE SIGNAL ;
    PORT
      LAYER met2 ;
        RECT 1021.360000 0.000000 1021.500000 0.485000 ;
    END
  END la_data_in[23]
  PIN la_data_in[22]
    DIRECTION INPUT ;
    USE SIGNAL ;
    PORT
      LAYER met2 ;
        RECT 1003.880000 0.000000 1004.020000 0.485000 ;
    END
  END la_data_in[22]
  PIN la_data_in[21]
    DIRECTION INPUT ;
    USE SIGNAL ;
    PORT
      LAYER met2 ;
        RECT 986.400000 0.000000 986.540000 0.485000 ;
    END
  END la_data_in[21]
  PIN la_data_in[20]
    DIRECTION INPUT ;
    USE SIGNAL ;
    PORT
      LAYER met2 ;
        RECT 968.920000 0.000000 969.060000 0.485000 ;
    END
  END la_data_in[20]
  PIN la_data_in[19]
    DIRECTION INPUT ;
    USE SIGNAL ;
    PORT
      LAYER met2 ;
        RECT 951.440000 0.000000 951.580000 0.485000 ;
    END
  END la_data_in[19]
  PIN la_data_in[18]
    DIRECTION INPUT ;
    USE SIGNAL ;
    PORT
      LAYER met2 ;
        RECT 933.960000 0.000000 934.100000 0.485000 ;
    END
  END la_data_in[18]
  PIN la_data_in[17]
    DIRECTION INPUT ;
    USE SIGNAL ;
    PORT
      LAYER met2 ;
        RECT 916.480000 0.000000 916.620000 0.485000 ;
    END
  END la_data_in[17]
  PIN la_data_in[16]
    DIRECTION INPUT ;
    USE SIGNAL ;
    PORT
      LAYER met2 ;
        RECT 899.000000 0.000000 899.140000 0.485000 ;
    END
  END la_data_in[16]
  PIN la_data_in[15]
    DIRECTION INPUT ;
    USE SIGNAL ;
    PORT
      LAYER met2 ;
        RECT 881.520000 0.000000 881.660000 0.485000 ;
    END
  END la_data_in[15]
  PIN la_data_in[14]
    DIRECTION INPUT ;
    USE SIGNAL ;
    PORT
      LAYER met2 ;
        RECT 864.040000 0.000000 864.180000 0.485000 ;
    END
  END la_data_in[14]
  PIN la_data_in[13]
    DIRECTION INPUT ;
    USE SIGNAL ;
    PORT
      LAYER met2 ;
        RECT 846.560000 0.000000 846.700000 0.485000 ;
    END
  END la_data_in[13]
  PIN la_data_in[12]
    DIRECTION INPUT ;
    USE SIGNAL ;
    PORT
      LAYER met2 ;
        RECT 829.080000 0.000000 829.220000 0.485000 ;
    END
  END la_data_in[12]
  PIN la_data_in[11]
    DIRECTION INPUT ;
    USE SIGNAL ;
    PORT
      LAYER met2 ;
        RECT 811.600000 0.000000 811.740000 0.485000 ;
    END
  END la_data_in[11]
  PIN la_data_in[10]
    DIRECTION INPUT ;
    USE SIGNAL ;
    PORT
      LAYER met2 ;
        RECT 793.660000 0.000000 793.800000 0.485000 ;
    END
  END la_data_in[10]
  PIN la_data_in[9]
    DIRECTION INPUT ;
    USE SIGNAL ;
    PORT
      LAYER met2 ;
        RECT 776.180000 0.000000 776.320000 0.485000 ;
    END
  END la_data_in[9]
  PIN la_data_in[8]
    DIRECTION INPUT ;
    USE SIGNAL ;
    PORT
      LAYER met2 ;
        RECT 758.700000 0.000000 758.840000 0.485000 ;
    END
  END la_data_in[8]
  PIN la_data_in[7]
    DIRECTION INPUT ;
    USE SIGNAL ;
    PORT
      LAYER met2 ;
        RECT 741.220000 0.000000 741.360000 0.485000 ;
    END
  END la_data_in[7]
  PIN la_data_in[6]
    DIRECTION INPUT ;
    USE SIGNAL ;
    PORT
      LAYER met2 ;
        RECT 723.740000 0.000000 723.880000 0.485000 ;
    END
  END la_data_in[6]
  PIN la_data_in[5]
    DIRECTION INPUT ;
    USE SIGNAL ;
    PORT
      LAYER met2 ;
        RECT 706.260000 0.000000 706.400000 0.485000 ;
    END
  END la_data_in[5]
  PIN la_data_in[4]
    DIRECTION INPUT ;
    USE SIGNAL ;
    PORT
      LAYER met2 ;
        RECT 688.780000 0.000000 688.920000 0.485000 ;
    END
  END la_data_in[4]
  PIN la_data_in[3]
    DIRECTION INPUT ;
    USE SIGNAL ;
    PORT
      LAYER met2 ;
        RECT 671.300000 0.000000 671.440000 0.485000 ;
    END
  END la_data_in[3]
  PIN la_data_in[2]
    DIRECTION INPUT ;
    USE SIGNAL ;
    PORT
      LAYER met2 ;
        RECT 653.820000 0.000000 653.960000 0.485000 ;
    END
  END la_data_in[2]
  PIN la_data_in[1]
    DIRECTION INPUT ;
    USE SIGNAL ;
    PORT
      LAYER met2 ;
        RECT 636.340000 0.000000 636.480000 0.485000 ;
    END
  END la_data_in[1]
  PIN la_data_in[0]
    DIRECTION INPUT ;
    USE SIGNAL ;
    PORT
      LAYER met2 ;
        RECT 618.860000 0.000000 619.000000 0.485000 ;
    END
  END la_data_in[0]
  PIN la_data_out[127]
    DIRECTION OUTPUT ;
    USE SIGNAL ;
    ANTENNADIFFAREA 0.43675 LAYER met2  ;
    ANTENNAPARTIALMETALAREA 4.4911 LAYER met2  ;
    ANTENNAPARTIALMETALSIDEAREA 22.3475 LAYER met2  ;
    PORT
      LAYER met2 ;
        RECT 2847.560000 0.000000 2847.700000 0.485000 ;
    END
  END la_data_out[127]
  PIN la_data_out[126]
    DIRECTION OUTPUT ;
    USE SIGNAL ;
    ANTENNADIFFAREA 0.43675 LAYER met2  ;
    ANTENNAPARTIALMETALAREA 4.7655 LAYER met2  ;
    ANTENNAPARTIALMETALSIDEAREA 23.7195 LAYER met2  ;
    PORT
      LAYER met2 ;
        RECT 2830.080000 0.000000 2830.220000 0.485000 ;
    END
  END la_data_out[126]
  PIN la_data_out[125]
    DIRECTION OUTPUT ;
    USE SIGNAL ;
    ANTENNADIFFAREA 0.43675 LAYER met2  ;
    ANTENNAPARTIALMETALAREA 4.4435 LAYER met2  ;
    ANTENNAPARTIALMETALSIDEAREA 22.1095 LAYER met2  ;
    PORT
      LAYER met2 ;
        RECT 2812.600000 0.000000 2812.740000 0.485000 ;
    END
  END la_data_out[125]
  PIN la_data_out[124]
    DIRECTION OUTPUT ;
    USE SIGNAL ;
    ANTENNADIFFAREA 0.43675 LAYER met2  ;
    ANTENNAPARTIALMETALAREA 4.4435 LAYER met2  ;
    ANTENNAPARTIALMETALSIDEAREA 22.1095 LAYER met2  ;
    PORT
      LAYER met2 ;
        RECT 2795.120000 0.000000 2795.260000 0.485000 ;
    END
  END la_data_out[124]
  PIN la_data_out[123]
    DIRECTION OUTPUT ;
    USE SIGNAL ;
    ANTENNADIFFAREA 0.43675 LAYER met2  ;
    ANTENNAPARTIALMETALAREA 4.5079 LAYER met2  ;
    ANTENNAPARTIALMETALSIDEAREA 22.4315 LAYER met2  ;
    PORT
      LAYER met2 ;
        RECT 2777.640000 0.000000 2777.780000 0.485000 ;
    END
  END la_data_out[123]
  PIN la_data_out[122]
    DIRECTION OUTPUT ;
    USE SIGNAL ;
    ANTENNADIFFAREA 0.43675 LAYER met2  ;
    ANTENNAPARTIALMETALAREA 4.4435 LAYER met2  ;
    ANTENNAPARTIALMETALSIDEAREA 22.1095 LAYER met2  ;
    PORT
      LAYER met2 ;
        RECT 2760.160000 0.000000 2760.300000 0.485000 ;
    END
  END la_data_out[122]
  PIN la_data_out[121]
    DIRECTION OUTPUT ;
    USE SIGNAL ;
    ANTENNADIFFAREA 0.43675 LAYER met2  ;
    ANTENNAPARTIALMETALAREA 4.4435 LAYER met2  ;
    ANTENNAPARTIALMETALSIDEAREA 22.1095 LAYER met2  ;
    PORT
      LAYER met2 ;
        RECT 2742.680000 0.000000 2742.820000 0.485000 ;
    END
  END la_data_out[121]
  PIN la_data_out[120]
    DIRECTION OUTPUT ;
    USE SIGNAL ;
    ANTENNADIFFAREA 0.43675 LAYER met2  ;
    ANTENNAPARTIALMETALAREA 4.4435 LAYER met2  ;
    ANTENNAPARTIALMETALSIDEAREA 22.1095 LAYER met2  ;
    PORT
      LAYER met2 ;
        RECT 2725.200000 0.000000 2725.340000 0.485000 ;
    END
  END la_data_out[120]
  PIN la_data_out[119]
    DIRECTION OUTPUT ;
    USE SIGNAL ;
    ANTENNADIFFAREA 0.43675 LAYER met2  ;
    ANTENNAPARTIALMETALAREA 4.79 LAYER met2  ;
    ANTENNAPARTIALMETALSIDEAREA 23.842 LAYER met2  ;
    PORT
      LAYER met2 ;
        RECT 2707.720000 0.000000 2707.860000 0.485000 ;
    END
  END la_data_out[119]
  PIN la_data_out[118]
    DIRECTION OUTPUT ;
    USE SIGNAL ;
    ANTENNADIFFAREA 0.43675 LAYER met2  ;
    ANTENNAPARTIALMETALAREA 4.4435 LAYER met2  ;
    ANTENNAPARTIALMETALSIDEAREA 22.1095 LAYER met2  ;
    PORT
      LAYER met2 ;
        RECT 2690.240000 0.000000 2690.380000 0.485000 ;
    END
  END la_data_out[118]
  PIN la_data_out[117]
    DIRECTION OUTPUT ;
    USE SIGNAL ;
    ANTENNADIFFAREA 0.43675 LAYER met2  ;
    ANTENNAPARTIALMETALAREA 4.4435 LAYER met2  ;
    ANTENNAPARTIALMETALSIDEAREA 22.1095 LAYER met2  ;
    PORT
      LAYER met2 ;
        RECT 2672.760000 0.000000 2672.900000 0.485000 ;
    END
  END la_data_out[117]
  PIN la_data_out[116]
    DIRECTION OUTPUT ;
    USE SIGNAL ;
    ANTENNADIFFAREA 0.43675 LAYER met2  ;
    ANTENNAPARTIALMETALAREA 4.5079 LAYER met2  ;
    ANTENNAPARTIALMETALSIDEAREA 22.4315 LAYER met2  ;
    PORT
      LAYER met2 ;
        RECT 2655.280000 0.000000 2655.420000 0.485000 ;
    END
  END la_data_out[116]
  PIN la_data_out[115]
    DIRECTION OUTPUT ;
    USE SIGNAL ;
    ANTENNADIFFAREA 0.43675 LAYER met2  ;
    ANTENNAPARTIALMETALAREA 4.4435 LAYER met2  ;
    ANTENNAPARTIALMETALSIDEAREA 22.1095 LAYER met2  ;
    PORT
      LAYER met2 ;
        RECT 2637.340000 0.000000 2637.480000 0.485000 ;
    END
  END la_data_out[115]
  PIN la_data_out[114]
    DIRECTION OUTPUT ;
    USE SIGNAL ;
    ANTENNADIFFAREA 0.43675 LAYER met2  ;
    ANTENNAPARTIALMETALAREA 4.4435 LAYER met2  ;
    ANTENNAPARTIALMETALSIDEAREA 22.1095 LAYER met2  ;
    PORT
      LAYER met2 ;
        RECT 2619.860000 0.000000 2620.000000 0.485000 ;
    END
  END la_data_out[114]
  PIN la_data_out[113]
    DIRECTION OUTPUT ;
    USE SIGNAL ;
    ANTENNADIFFAREA 0.43675 LAYER met2  ;
    ANTENNAPARTIALMETALAREA 4.4435 LAYER met2  ;
    ANTENNAPARTIALMETALSIDEAREA 22.1095 LAYER met2  ;
    PORT
      LAYER met2 ;
        RECT 2602.380000 0.000000 2602.520000 0.485000 ;
    END
  END la_data_out[113]
  PIN la_data_out[112]
    DIRECTION OUTPUT ;
    USE SIGNAL ;
    ANTENNADIFFAREA 0.43675 LAYER met2  ;
    ANTENNAPARTIALMETALAREA 4.6612 LAYER met2  ;
    ANTENNAPARTIALMETALSIDEAREA 23.198 LAYER met2  ;
    PORT
      LAYER met2 ;
        RECT 2584.900000 0.000000 2585.040000 0.485000 ;
    END
  END la_data_out[112]
  PIN la_data_out[111]
    DIRECTION OUTPUT ;
    USE SIGNAL ;
    ANTENNADIFFAREA 0.43675 LAYER met2  ;
    ANTENNAPARTIALMETALAREA 4.4435 LAYER met2  ;
    ANTENNAPARTIALMETALSIDEAREA 22.1095 LAYER met2  ;
    PORT
      LAYER met2 ;
        RECT 2567.420000 0.000000 2567.560000 0.485000 ;
    END
  END la_data_out[111]
  PIN la_data_out[110]
    DIRECTION OUTPUT ;
    USE SIGNAL ;
    ANTENNADIFFAREA 0.43675 LAYER met2  ;
    ANTENNAPARTIALMETALAREA 4.4435 LAYER met2  ;
    ANTENNAPARTIALMETALSIDEAREA 22.1095 LAYER met2  ;
    PORT
      LAYER met2 ;
        RECT 2549.940000 0.000000 2550.080000 0.485000 ;
    END
  END la_data_out[110]
  PIN la_data_out[109]
    DIRECTION OUTPUT ;
    USE SIGNAL ;
    ANTENNADIFFAREA 0.43675 LAYER met2  ;
    ANTENNAPARTIALMETALAREA 4.5968 LAYER met2  ;
    ANTENNAPARTIALMETALSIDEAREA 22.876 LAYER met2  ;
    PORT
      LAYER met2 ;
        RECT 2532.460000 0.000000 2532.600000 0.485000 ;
    END
  END la_data_out[109]
  PIN la_data_out[108]
    DIRECTION OUTPUT ;
    USE SIGNAL ;
    ANTENNADIFFAREA 0.43675 LAYER met2  ;
    ANTENNAPARTIALMETALAREA 4.4435 LAYER met2  ;
    ANTENNAPARTIALMETALSIDEAREA 22.1095 LAYER met2  ;
    PORT
      LAYER met2 ;
        RECT 2514.980000 0.000000 2515.120000 0.485000 ;
    END
  END la_data_out[108]
  PIN la_data_out[107]
    DIRECTION OUTPUT ;
    USE SIGNAL ;
    ANTENNADIFFAREA 0.43675 LAYER met2  ;
    ANTENNAPARTIALMETALAREA 4.4435 LAYER met2  ;
    ANTENNAPARTIALMETALSIDEAREA 22.1095 LAYER met2  ;
    PORT
      LAYER met2 ;
        RECT 2497.500000 0.000000 2497.640000 0.485000 ;
    END
  END la_data_out[107]
  PIN la_data_out[106]
    DIRECTION OUTPUT ;
    USE SIGNAL ;
    ANTENNADIFFAREA 0.43675 LAYER met2  ;
    ANTENNAPARTIALMETALAREA 4.4435 LAYER met2  ;
    ANTENNAPARTIALMETALSIDEAREA 22.1095 LAYER met2  ;
    PORT
      LAYER met2 ;
        RECT 2480.020000 0.000000 2480.160000 0.485000 ;
    END
  END la_data_out[106]
  PIN la_data_out[105]
    DIRECTION OUTPUT ;
    USE SIGNAL ;
    ANTENNADIFFAREA 0.43675 LAYER met2  ;
    ANTENNAPARTIALMETALAREA 4.6367 LAYER met2  ;
    ANTENNAPARTIALMETALSIDEAREA 23.0755 LAYER met2  ;
    PORT
      LAYER met2 ;
        RECT 2462.540000 0.000000 2462.680000 0.485000 ;
    END
  END la_data_out[105]
  PIN la_data_out[104]
    DIRECTION OUTPUT ;
    USE SIGNAL ;
    ANTENNADIFFAREA 0.43675 LAYER met2  ;
    ANTENNAPARTIALMETALAREA 4.4435 LAYER met2  ;
    ANTENNAPARTIALMETALSIDEAREA 22.1095 LAYER met2  ;
    PORT
      LAYER met2 ;
        RECT 2445.060000 0.000000 2445.200000 0.485000 ;
    END
  END la_data_out[104]
  PIN la_data_out[103]
    DIRECTION OUTPUT ;
    USE SIGNAL ;
    ANTENNADIFFAREA 0.43675 LAYER met2  ;
    ANTENNAPARTIALMETALAREA 4.4435 LAYER met2  ;
    ANTENNAPARTIALMETALSIDEAREA 22.1095 LAYER met2  ;
    PORT
      LAYER met2 ;
        RECT 2427.580000 0.000000 2427.720000 0.485000 ;
    END
  END la_data_out[103]
  PIN la_data_out[102]
    DIRECTION OUTPUT ;
    USE SIGNAL ;
    ANTENNADIFFAREA 0.43675 LAYER met2  ;
    ANTENNAPARTIALMETALAREA 4.5723 LAYER met2  ;
    ANTENNAPARTIALMETALSIDEAREA 22.7535 LAYER met2  ;
    PORT
      LAYER met2 ;
        RECT 2410.100000 0.000000 2410.240000 0.485000 ;
    END
  END la_data_out[102]
  PIN la_data_out[101]
    DIRECTION OUTPUT ;
    USE SIGNAL ;
    ANTENNADIFFAREA 0.43675 LAYER met2  ;
    ANTENNAPARTIALMETALAREA 4.4435 LAYER met2  ;
    ANTENNAPARTIALMETALSIDEAREA 22.1095 LAYER met2  ;
    PORT
      LAYER met2 ;
        RECT 2392.620000 0.000000 2392.760000 0.485000 ;
    END
  END la_data_out[101]
  PIN la_data_out[100]
    DIRECTION OUTPUT ;
    USE SIGNAL ;
    ANTENNADIFFAREA 0.43675 LAYER met2  ;
    ANTENNAPARTIALMETALAREA 4.4435 LAYER met2  ;
    ANTENNAPARTIALMETALSIDEAREA 22.1095 LAYER met2  ;
    PORT
      LAYER met2 ;
        RECT 2375.140000 0.000000 2375.280000 0.485000 ;
    END
  END la_data_out[100]
  PIN la_data_out[99]
    DIRECTION OUTPUT ;
    USE SIGNAL ;
    ANTENNADIFFAREA 0.43675 LAYER met2  ;
    ANTENNAPARTIALMETALAREA 4.4435 LAYER met2  ;
    ANTENNAPARTIALMETALSIDEAREA 22.1095 LAYER met2  ;
    PORT
      LAYER met2 ;
        RECT 2357.660000 0.000000 2357.800000 0.485000 ;
    END
  END la_data_out[99]
  PIN la_data_out[98]
    DIRECTION OUTPUT ;
    USE SIGNAL ;
    ANTENNADIFFAREA 0.43675 LAYER met2  ;
    ANTENNAPARTIALMETALAREA 4.6612 LAYER met2  ;
    ANTENNAPARTIALMETALSIDEAREA 23.198 LAYER met2  ;
    PORT
      LAYER met2 ;
        RECT 2340.180000 0.000000 2340.320000 0.485000 ;
    END
  END la_data_out[98]
  PIN la_data_out[97]
    DIRECTION OUTPUT ;
    USE SIGNAL ;
    ANTENNADIFFAREA 0.43675 LAYER met2  ;
    ANTENNAPARTIALMETALAREA 4.4435 LAYER met2  ;
    ANTENNAPARTIALMETALSIDEAREA 22.1095 LAYER met2  ;
    PORT
      LAYER met2 ;
        RECT 2322.700000 0.000000 2322.840000 0.485000 ;
    END
  END la_data_out[97]
  PIN la_data_out[96]
    DIRECTION OUTPUT ;
    USE SIGNAL ;
    ANTENNADIFFAREA 0.43675 LAYER met2  ;
    ANTENNAPARTIALMETALAREA 4.4435 LAYER met2  ;
    ANTENNAPARTIALMETALSIDEAREA 22.1095 LAYER met2  ;
    PORT
      LAYER met2 ;
        RECT 2305.220000 0.000000 2305.360000 0.485000 ;
    END
  END la_data_out[96]
  PIN la_data_out[95]
    DIRECTION OUTPUT ;
    USE SIGNAL ;
    ANTENNADIFFAREA 0.43675 LAYER met2  ;
    ANTENNAPARTIALMETALAREA 4.6612 LAYER met2  ;
    ANTENNAPARTIALMETALSIDEAREA 23.198 LAYER met2  ;
    PORT
      LAYER met2 ;
        RECT 2287.280000 0.000000 2287.420000 0.485000 ;
    END
  END la_data_out[95]
  PIN la_data_out[94]
    DIRECTION OUTPUT ;
    USE SIGNAL ;
    ANTENNADIFFAREA 0.43675 LAYER met2  ;
    ANTENNAPARTIALMETALAREA 4.4435 LAYER met2  ;
    ANTENNAPARTIALMETALSIDEAREA 22.1095 LAYER met2  ;
    PORT
      LAYER met2 ;
        RECT 2269.800000 0.000000 2269.940000 0.485000 ;
    END
  END la_data_out[94]
  PIN la_data_out[93]
    DIRECTION OUTPUT ;
    USE SIGNAL ;
    ANTENNADIFFAREA 0.43675 LAYER met2  ;
    ANTENNAPARTIALMETALAREA 4.4435 LAYER met2  ;
    ANTENNAPARTIALMETALSIDEAREA 22.1095 LAYER met2  ;
    PORT
      LAYER met2 ;
        RECT 2252.320000 0.000000 2252.460000 0.485000 ;
    END
  END la_data_out[93]
  PIN la_data_out[92]
    DIRECTION OUTPUT ;
    USE SIGNAL ;
    ANTENNADIFFAREA 0.43675 LAYER met2  ;
    ANTENNAPARTIALMETALAREA 4.4435 LAYER met2  ;
    ANTENNAPARTIALMETALSIDEAREA 22.1095 LAYER met2  ;
    PORT
      LAYER met2 ;
        RECT 2234.840000 0.000000 2234.980000 0.485000 ;
    END
  END la_data_out[92]
  PIN la_data_out[91]
    DIRECTION OUTPUT ;
    USE SIGNAL ;
    ANTENNADIFFAREA 0.43675 LAYER met2  ;
    ANTENNAPARTIALMETALAREA 4.5723 LAYER met2  ;
    ANTENNAPARTIALMETALSIDEAREA 22.7535 LAYER met2  ;
    PORT
      LAYER met2 ;
        RECT 2217.360000 0.000000 2217.500000 0.485000 ;
    END
  END la_data_out[91]
  PIN la_data_out[90]
    DIRECTION OUTPUT ;
    USE SIGNAL ;
    ANTENNADIFFAREA 0.43675 LAYER met2  ;
    ANTENNAPARTIALMETALAREA 4.4435 LAYER met2  ;
    ANTENNAPARTIALMETALSIDEAREA 22.1095 LAYER met2  ;
    PORT
      LAYER met2 ;
        RECT 2199.880000 0.000000 2200.020000 0.485000 ;
    END
  END la_data_out[90]
  PIN la_data_out[89]
    DIRECTION OUTPUT ;
    USE SIGNAL ;
    ANTENNADIFFAREA 0.43675 LAYER met2  ;
    ANTENNAPARTIALMETALAREA 4.4435 LAYER met2  ;
    ANTENNAPARTIALMETALSIDEAREA 22.1095 LAYER met2  ;
    PORT
      LAYER met2 ;
        RECT 2182.400000 0.000000 2182.540000 0.485000 ;
    END
  END la_data_out[89]
  PIN la_data_out[88]
    DIRECTION OUTPUT ;
    USE SIGNAL ;
    ANTENNADIFFAREA 0.43675 LAYER met2  ;
    ANTENNAPARTIALMETALAREA 4.6367 LAYER met2  ;
    ANTENNAPARTIALMETALSIDEAREA 23.0755 LAYER met2  ;
    PORT
      LAYER met2 ;
        RECT 2164.920000 0.000000 2165.060000 0.485000 ;
    END
  END la_data_out[88]
  PIN la_data_out[87]
    DIRECTION OUTPUT ;
    USE SIGNAL ;
    ANTENNADIFFAREA 0.43675 LAYER met2  ;
    ANTENNAPARTIALMETALAREA 4.4435 LAYER met2  ;
    ANTENNAPARTIALMETALSIDEAREA 22.1095 LAYER met2  ;
    PORT
      LAYER met2 ;
        RECT 2147.440000 0.000000 2147.580000 0.485000 ;
    END
  END la_data_out[87]
  PIN la_data_out[86]
    DIRECTION OUTPUT ;
    USE SIGNAL ;
    ANTENNADIFFAREA 0.43675 LAYER met2  ;
    ANTENNAPARTIALMETALAREA 4.4435 LAYER met2  ;
    ANTENNAPARTIALMETALSIDEAREA 22.1095 LAYER met2  ;
    PORT
      LAYER met2 ;
        RECT 2129.960000 0.000000 2130.100000 0.485000 ;
    END
  END la_data_out[86]
  PIN la_data_out[85]
    DIRECTION OUTPUT ;
    USE SIGNAL ;
    ANTENNADIFFAREA 0.43675 LAYER met2  ;
    ANTENNAPARTIALMETALAREA 4.4435 LAYER met2  ;
    ANTENNAPARTIALMETALSIDEAREA 22.1095 LAYER met2  ;
    PORT
      LAYER met2 ;
        RECT 2112.480000 0.000000 2112.620000 0.485000 ;
    END
  END la_data_out[85]
  PIN la_data_out[84]
    DIRECTION OUTPUT ;
    USE SIGNAL ;
    ANTENNADIFFAREA 0.43675 LAYER met2  ;
    ANTENNAPARTIALMETALAREA 4.5723 LAYER met2  ;
    ANTENNAPARTIALMETALSIDEAREA 22.7535 LAYER met2  ;
    PORT
      LAYER met2 ;
        RECT 2095.000000 0.000000 2095.140000 0.485000 ;
    END
  END la_data_out[84]
  PIN la_data_out[83]
    DIRECTION OUTPUT ;
    USE SIGNAL ;
    ANTENNADIFFAREA 0.43675 LAYER met2  ;
    ANTENNAPARTIALMETALAREA 4.4435 LAYER met2  ;
    ANTENNAPARTIALMETALSIDEAREA 22.1095 LAYER met2  ;
    PORT
      LAYER met2 ;
        RECT 2077.520000 0.000000 2077.660000 0.485000 ;
    END
  END la_data_out[83]
  PIN la_data_out[82]
    DIRECTION OUTPUT ;
    USE SIGNAL ;
    ANTENNADIFFAREA 0.43675 LAYER met2  ;
    ANTENNAPARTIALMETALAREA 4.4435 LAYER met2  ;
    ANTENNAPARTIALMETALSIDEAREA 22.1095 LAYER met2  ;
    PORT
      LAYER met2 ;
        RECT 2060.040000 0.000000 2060.180000 0.485000 ;
    END
  END la_data_out[82]
  PIN la_data_out[81]
    DIRECTION OUTPUT ;
    USE SIGNAL ;
    ANTENNADIFFAREA 0.43675 LAYER met2  ;
    ANTENNAPARTIALMETALAREA 4.6367 LAYER met2  ;
    ANTENNAPARTIALMETALSIDEAREA 23.0755 LAYER met2  ;
    PORT
      LAYER met2 ;
        RECT 2042.560000 0.000000 2042.700000 0.485000 ;
    END
  END la_data_out[81]
  PIN la_data_out[80]
    DIRECTION OUTPUT ;
    USE SIGNAL ;
    ANTENNADIFFAREA 0.43675 LAYER met2  ;
    ANTENNAPARTIALMETALAREA 4.4435 LAYER met2  ;
    ANTENNAPARTIALMETALSIDEAREA 22.1095 LAYER met2  ;
    PORT
      LAYER met2 ;
        RECT 2025.080000 0.000000 2025.220000 0.485000 ;
    END
  END la_data_out[80]
  PIN la_data_out[79]
    DIRECTION OUTPUT ;
    USE SIGNAL ;
    ANTENNADIFFAREA 0.43675 LAYER met2  ;
    ANTENNAPARTIALMETALAREA 4.4435 LAYER met2  ;
    ANTENNAPARTIALMETALSIDEAREA 22.1095 LAYER met2  ;
    PORT
      LAYER met2 ;
        RECT 2007.600000 0.000000 2007.740000 0.485000 ;
    END
  END la_data_out[79]
  PIN la_data_out[78]
    DIRECTION OUTPUT ;
    USE SIGNAL ;
    ANTENNADIFFAREA 0.43675 LAYER met2  ;
    ANTENNAPARTIALMETALAREA 4.4435 LAYER met2  ;
    ANTENNAPARTIALMETALSIDEAREA 22.1095 LAYER met2  ;
    PORT
      LAYER met2 ;
        RECT 1990.120000 0.000000 1990.260000 0.485000 ;
    END
  END la_data_out[78]
  PIN la_data_out[77]
    DIRECTION OUTPUT ;
    USE SIGNAL ;
    ANTENNADIFFAREA 0.43675 LAYER met2  ;
    ANTENNAPARTIALMETALAREA 4.5723 LAYER met2  ;
    ANTENNAPARTIALMETALSIDEAREA 22.7535 LAYER met2  ;
    PORT
      LAYER met2 ;
        RECT 1972.640000 0.000000 1972.780000 0.485000 ;
    END
  END la_data_out[77]
  PIN la_data_out[76]
    DIRECTION OUTPUT ;
    USE SIGNAL ;
    ANTENNADIFFAREA 0.43675 LAYER met2  ;
    ANTENNAPARTIALMETALAREA 4.4435 LAYER met2  ;
    ANTENNAPARTIALMETALSIDEAREA 22.1095 LAYER met2  ;
    PORT
      LAYER met2 ;
        RECT 1954.700000 0.000000 1954.840000 0.485000 ;
    END
  END la_data_out[76]
  PIN la_data_out[75]
    DIRECTION OUTPUT ;
    USE SIGNAL ;
    ANTENNADIFFAREA 0.43675 LAYER met2  ;
    ANTENNAPARTIALMETALAREA 4.4435 LAYER met2  ;
    ANTENNAPARTIALMETALSIDEAREA 22.1095 LAYER met2  ;
    PORT
      LAYER met2 ;
        RECT 1937.220000 0.000000 1937.360000 0.485000 ;
    END
  END la_data_out[75]
  PIN la_data_out[74]
    DIRECTION OUTPUT ;
    USE SIGNAL ;
    ANTENNADIFFAREA 0.43675 LAYER met2  ;
    ANTENNAPARTIALMETALAREA 4.6367 LAYER met2  ;
    ANTENNAPARTIALMETALSIDEAREA 23.0755 LAYER met2  ;
    PORT
      LAYER met2 ;
        RECT 1919.740000 0.000000 1919.880000 0.485000 ;
    END
  END la_data_out[74]
  PIN la_data_out[73]
    DIRECTION OUTPUT ;
    USE SIGNAL ;
    ANTENNADIFFAREA 0.43675 LAYER met2  ;
    ANTENNAPARTIALMETALAREA 4.4435 LAYER met2  ;
    ANTENNAPARTIALMETALSIDEAREA 22.1095 LAYER met2  ;
    PORT
      LAYER met2 ;
        RECT 1902.260000 0.000000 1902.400000 0.485000 ;
    END
  END la_data_out[73]
  PIN la_data_out[72]
    DIRECTION OUTPUT ;
    USE SIGNAL ;
    ANTENNADIFFAREA 0.43675 LAYER met2  ;
    ANTENNAPARTIALMETALAREA 4.4435 LAYER met2  ;
    ANTENNAPARTIALMETALSIDEAREA 22.1095 LAYER met2  ;
    PORT
      LAYER met2 ;
        RECT 1884.780000 0.000000 1884.920000 0.485000 ;
    END
  END la_data_out[72]
  PIN la_data_out[71]
    DIRECTION OUTPUT ;
    USE SIGNAL ;
    ANTENNADIFFAREA 0.43675 LAYER met2  ;
    ANTENNAPARTIALMETALAREA 4.4435 LAYER met2  ;
    ANTENNAPARTIALMETALSIDEAREA 22.1095 LAYER met2  ;
    PORT
      LAYER met2 ;
        RECT 1867.300000 0.000000 1867.440000 0.485000 ;
    END
  END la_data_out[71]
  PIN la_data_out[70]
    DIRECTION OUTPUT ;
    USE SIGNAL ;
    ANTENNADIFFAREA 0.43675 LAYER met2  ;
    ANTENNAPARTIALMETALAREA 4.5968 LAYER met2  ;
    ANTENNAPARTIALMETALSIDEAREA 22.876 LAYER met2  ;
    PORT
      LAYER met2 ;
        RECT 1849.820000 0.000000 1849.960000 0.485000 ;
    END
  END la_data_out[70]
  PIN la_data_out[69]
    DIRECTION OUTPUT ;
    USE SIGNAL ;
    ANTENNADIFFAREA 0.43675 LAYER met2  ;
    ANTENNAPARTIALMETALAREA 4.4435 LAYER met2  ;
    ANTENNAPARTIALMETALSIDEAREA 22.1095 LAYER met2  ;
    PORT
      LAYER met2 ;
        RECT 1832.340000 0.000000 1832.480000 0.485000 ;
    END
  END la_data_out[69]
  PIN la_data_out[68]
    DIRECTION OUTPUT ;
    USE SIGNAL ;
    ANTENNADIFFAREA 0.43675 LAYER met2  ;
    ANTENNAPARTIALMETALAREA 4.4435 LAYER met2  ;
    ANTENNAPARTIALMETALSIDEAREA 22.1095 LAYER met2  ;
    PORT
      LAYER met2 ;
        RECT 1814.860000 0.000000 1815.000000 0.485000 ;
    END
  END la_data_out[68]
  PIN la_data_out[67]
    DIRECTION OUTPUT ;
    USE SIGNAL ;
    ANTENNADIFFAREA 0.43675 LAYER met2  ;
    ANTENNAPARTIALMETALAREA 4.6612 LAYER met2  ;
    ANTENNAPARTIALMETALSIDEAREA 23.198 LAYER met2  ;
    PORT
      LAYER met2 ;
        RECT 1797.380000 0.000000 1797.520000 0.485000 ;
    END
  END la_data_out[67]
  PIN la_data_out[66]
    DIRECTION OUTPUT ;
    USE SIGNAL ;
    ANTENNADIFFAREA 0.43675 LAYER met2  ;
    ANTENNAPARTIALMETALAREA 4.4435 LAYER met2  ;
    ANTENNAPARTIALMETALSIDEAREA 22.1095 LAYER met2  ;
    PORT
      LAYER met2 ;
        RECT 1779.900000 0.000000 1780.040000 0.485000 ;
    END
  END la_data_out[66]
  PIN la_data_out[65]
    DIRECTION OUTPUT ;
    USE SIGNAL ;
    ANTENNADIFFAREA 0.43675 LAYER met2  ;
    ANTENNAPARTIALMETALAREA 4.4435 LAYER met2  ;
    ANTENNAPARTIALMETALSIDEAREA 22.1095 LAYER met2  ;
    PORT
      LAYER met2 ;
        RECT 1762.420000 0.000000 1762.560000 0.485000 ;
    END
  END la_data_out[65]
  PIN la_data_out[64]
    DIRECTION OUTPUT ;
    USE SIGNAL ;
    ANTENNADIFFAREA 0.43675 LAYER met2  ;
    ANTENNAPARTIALMETALAREA 4.4435 LAYER met2  ;
    ANTENNAPARTIALMETALSIDEAREA 22.1095 LAYER met2  ;
    PORT
      LAYER met2 ;
        RECT 1744.940000 0.000000 1745.080000 0.485000 ;
    END
  END la_data_out[64]
  PIN la_data_out[63]
    DIRECTION OUTPUT ;
    USE SIGNAL ;
    ANTENNADIFFAREA 0.43675 LAYER met2  ;
    ANTENNAPARTIALMETALAREA 4.5723 LAYER met2  ;
    ANTENNAPARTIALMETALSIDEAREA 22.7535 LAYER met2  ;
    PORT
      LAYER met2 ;
        RECT 1727.460000 0.000000 1727.600000 0.485000 ;
    END
  END la_data_out[63]
  PIN la_data_out[62]
    DIRECTION OUTPUT ;
    USE SIGNAL ;
    ANTENNADIFFAREA 0.43675 LAYER met2  ;
    ANTENNAPARTIALMETALAREA 4.4435 LAYER met2  ;
    ANTENNAPARTIALMETALSIDEAREA 22.1095 LAYER met2  ;
    PORT
      LAYER met2 ;
        RECT 1709.980000 0.000000 1710.120000 0.485000 ;
    END
  END la_data_out[62]
  PIN la_data_out[61]
    DIRECTION OUTPUT ;
    USE SIGNAL ;
    ANTENNADIFFAREA 0.43675 LAYER met2  ;
    ANTENNAPARTIALMETALAREA 4.4435 LAYER met2  ;
    ANTENNAPARTIALMETALSIDEAREA 22.1095 LAYER met2  ;
    PORT
      LAYER met2 ;
        RECT 1692.500000 0.000000 1692.640000 0.485000 ;
    END
  END la_data_out[61]
  PIN la_data_out[60]
    DIRECTION OUTPUT ;
    USE SIGNAL ;
    ANTENNADIFFAREA 0.43675 LAYER met2  ;
    ANTENNAPARTIALMETALAREA 4.6367 LAYER met2  ;
    ANTENNAPARTIALMETALSIDEAREA 23.0755 LAYER met2  ;
    PORT
      LAYER met2 ;
        RECT 1675.020000 0.000000 1675.160000 0.485000 ;
    END
  END la_data_out[60]
  PIN la_data_out[59]
    DIRECTION OUTPUT ;
    USE SIGNAL ;
    ANTENNADIFFAREA 0.43675 LAYER met2  ;
    ANTENNAPARTIALMETALAREA 4.4435 LAYER met2  ;
    ANTENNAPARTIALMETALSIDEAREA 22.1095 LAYER met2  ;
    PORT
      LAYER met2 ;
        RECT 1657.540000 0.000000 1657.680000 0.485000 ;
    END
  END la_data_out[59]
  PIN la_data_out[58]
    DIRECTION OUTPUT ;
    USE SIGNAL ;
    ANTENNADIFFAREA 0.43675 LAYER met2  ;
    ANTENNAPARTIALMETALAREA 4.4435 LAYER met2  ;
    ANTENNAPARTIALMETALSIDEAREA 22.1095 LAYER met2  ;
    PORT
      LAYER met2 ;
        RECT 1640.060000 0.000000 1640.200000 0.485000 ;
    END
  END la_data_out[58]
  PIN la_data_out[57]
    DIRECTION OUTPUT ;
    USE SIGNAL ;
    ANTENNADIFFAREA 0.43675 LAYER met2  ;
    ANTENNAPARTIALMETALAREA 4.4435 LAYER met2  ;
    ANTENNAPARTIALMETALSIDEAREA 22.1095 LAYER met2  ;
    PORT
      LAYER met2 ;
        RECT 1622.580000 0.000000 1622.720000 0.485000 ;
    END
  END la_data_out[57]
  PIN la_data_out[56]
    DIRECTION OUTPUT ;
    USE SIGNAL ;
    ANTENNADIFFAREA 0.43675 LAYER met2  ;
    ANTENNAPARTIALMETALAREA 4.5079 LAYER met2  ;
    ANTENNAPARTIALMETALSIDEAREA 22.4315 LAYER met2  ;
    PORT
      LAYER met2 ;
        RECT 1604.640000 0.000000 1604.780000 0.485000 ;
    END
  END la_data_out[56]
  PIN la_data_out[55]
    DIRECTION OUTPUT ;
    USE SIGNAL ;
    ANTENNADIFFAREA 0.43675 LAYER met2  ;
    ANTENNAPARTIALMETALAREA 4.4435 LAYER met2  ;
    ANTENNAPARTIALMETALSIDEAREA 22.1095 LAYER met2  ;
    PORT
      LAYER met2 ;
        RECT 1587.160000 0.000000 1587.300000 0.485000 ;
    END
  END la_data_out[55]
  PIN la_data_out[54]
    DIRECTION OUTPUT ;
    USE SIGNAL ;
    ANTENNADIFFAREA 0.43675 LAYER met2  ;
    ANTENNAPARTIALMETALAREA 4.4435 LAYER met2  ;
    ANTENNAPARTIALMETALSIDEAREA 22.1095 LAYER met2  ;
    PORT
      LAYER met2 ;
        RECT 1569.680000 0.000000 1569.820000 0.485000 ;
    END
  END la_data_out[54]
  PIN la_data_out[53]
    DIRECTION OUTPUT ;
    USE SIGNAL ;
    ANTENNADIFFAREA 0.43675 LAYER met2  ;
    ANTENNAPARTIALMETALAREA 4.7011 LAYER met2  ;
    ANTENNAPARTIALMETALSIDEAREA 23.3975 LAYER met2  ;
    PORT
      LAYER met2 ;
        RECT 1552.200000 0.000000 1552.340000 0.485000 ;
    END
  END la_data_out[53]
  PIN la_data_out[52]
    DIRECTION OUTPUT ;
    USE SIGNAL ;
    ANTENNADIFFAREA 0.43675 LAYER met2  ;
    ANTENNAPARTIALMETALAREA 4.4435 LAYER met2  ;
    ANTENNAPARTIALMETALSIDEAREA 22.1095 LAYER met2  ;
    PORT
      LAYER met2 ;
        RECT 1534.720000 0.000000 1534.860000 0.485000 ;
    END
  END la_data_out[52]
  PIN la_data_out[51]
    DIRECTION OUTPUT ;
    USE SIGNAL ;
    ANTENNADIFFAREA 0.43675 LAYER met2  ;
    ANTENNAPARTIALMETALAREA 4.4435 LAYER met2  ;
    ANTENNAPARTIALMETALSIDEAREA 22.1095 LAYER met2  ;
    PORT
      LAYER met2 ;
        RECT 1517.240000 0.000000 1517.380000 0.485000 ;
    END
  END la_data_out[51]
  PIN la_data_out[50]
    DIRECTION OUTPUT ;
    USE SIGNAL ;
    ANTENNADIFFAREA 0.43675 LAYER met2  ;
    ANTENNAPARTIALMETALAREA 4.4435 LAYER met2  ;
    ANTENNAPARTIALMETALSIDEAREA 22.1095 LAYER met2  ;
    PORT
      LAYER met2 ;
        RECT 1499.760000 0.000000 1499.900000 0.485000 ;
    END
  END la_data_out[50]
  PIN la_data_out[49]
    DIRECTION OUTPUT ;
    USE SIGNAL ;
    ANTENNADIFFAREA 0.43675 LAYER met2  ;
    ANTENNAPARTIALMETALAREA 4.5079 LAYER met2  ;
    ANTENNAPARTIALMETALSIDEAREA 22.4315 LAYER met2  ;
    PORT
      LAYER met2 ;
        RECT 1482.280000 0.000000 1482.420000 0.485000 ;
    END
  END la_data_out[49]
  PIN la_data_out[48]
    DIRECTION OUTPUT ;
    USE SIGNAL ;
    ANTENNADIFFAREA 0.43675 LAYER met2  ;
    ANTENNAPARTIALMETALAREA 4.4435 LAYER met2  ;
    ANTENNAPARTIALMETALSIDEAREA 22.1095 LAYER met2  ;
    PORT
      LAYER met2 ;
        RECT 1464.800000 0.000000 1464.940000 0.485000 ;
    END
  END la_data_out[48]
  PIN la_data_out[47]
    DIRECTION OUTPUT ;
    USE SIGNAL ;
    ANTENNADIFFAREA 0.43675 LAYER met2  ;
    ANTENNAPARTIALMETALAREA 4.4435 LAYER met2  ;
    ANTENNAPARTIALMETALSIDEAREA 22.1095 LAYER met2  ;
    PORT
      LAYER met2 ;
        RECT 1447.320000 0.000000 1447.460000 0.485000 ;
    END
  END la_data_out[47]
  PIN la_data_out[46]
    DIRECTION OUTPUT ;
    USE SIGNAL ;
    ANTENNADIFFAREA 0.43675 LAYER met2  ;
    ANTENNAPARTIALMETALAREA 4.7256 LAYER met2  ;
    ANTENNAPARTIALMETALSIDEAREA 23.52 LAYER met2  ;
    PORT
      LAYER met2 ;
        RECT 1429.840000 0.000000 1429.980000 0.485000 ;
    END
  END la_data_out[46]
  PIN la_data_out[45]
    DIRECTION OUTPUT ;
    USE SIGNAL ;
    ANTENNADIFFAREA 0.43675 LAYER met2  ;
    ANTENNAPARTIALMETALAREA 4.4435 LAYER met2  ;
    ANTENNAPARTIALMETALSIDEAREA 22.1095 LAYER met2  ;
    PORT
      LAYER met2 ;
        RECT 1412.360000 0.000000 1412.500000 0.485000 ;
    END
  END la_data_out[45]
  PIN la_data_out[44]
    DIRECTION OUTPUT ;
    USE SIGNAL ;
    ANTENNADIFFAREA 0.43675 LAYER met2  ;
    ANTENNAPARTIALMETALAREA 4.4435 LAYER met2  ;
    ANTENNAPARTIALMETALSIDEAREA 22.1095 LAYER met2  ;
    PORT
      LAYER met2 ;
        RECT 1394.880000 0.000000 1395.020000 0.485000 ;
    END
  END la_data_out[44]
  PIN la_data_out[43]
    DIRECTION OUTPUT ;
    USE SIGNAL ;
    ANTENNADIFFAREA 0.43675 LAYER met2  ;
    ANTENNAPARTIALMETALAREA 4.4435 LAYER met2  ;
    ANTENNAPARTIALMETALSIDEAREA 22.1095 LAYER met2  ;
    PORT
      LAYER met2 ;
        RECT 1377.400000 0.000000 1377.540000 0.485000 ;
    END
  END la_data_out[43]
  PIN la_data_out[42]
    DIRECTION OUTPUT ;
    USE SIGNAL ;
    ANTENNADIFFAREA 0.43675 LAYER met2  ;
    ANTENNAPARTIALMETALAREA 4.5079 LAYER met2  ;
    ANTENNAPARTIALMETALSIDEAREA 22.4315 LAYER met2  ;
    PORT
      LAYER met2 ;
        RECT 1359.920000 0.000000 1360.060000 0.485000 ;
    END
  END la_data_out[42]
  PIN la_data_out[41]
    DIRECTION OUTPUT ;
    USE SIGNAL ;
    ANTENNADIFFAREA 0.43675 LAYER met2  ;
    ANTENNAPARTIALMETALAREA 4.4435 LAYER met2  ;
    ANTENNAPARTIALMETALSIDEAREA 22.1095 LAYER met2  ;
    PORT
      LAYER met2 ;
        RECT 1342.440000 0.000000 1342.580000 0.485000 ;
    END
  END la_data_out[41]
  PIN la_data_out[40]
    DIRECTION OUTPUT ;
    USE SIGNAL ;
    ANTENNADIFFAREA 0.43675 LAYER met2  ;
    ANTENNAPARTIALMETALAREA 4.4435 LAYER met2  ;
    ANTENNAPARTIALMETALSIDEAREA 22.1095 LAYER met2  ;
    PORT
      LAYER met2 ;
        RECT 1324.960000 0.000000 1325.100000 0.485000 ;
    END
  END la_data_out[40]
  PIN la_data_out[39]
    DIRECTION OUTPUT ;
    USE SIGNAL ;
    ANTENNADIFFAREA 0.43675 LAYER met2  ;
    ANTENNAPARTIALMETALAREA 4.7011 LAYER met2  ;
    ANTENNAPARTIALMETALSIDEAREA 23.3975 LAYER met2  ;
    PORT
      LAYER met2 ;
        RECT 1307.480000 0.000000 1307.620000 0.485000 ;
    END
  END la_data_out[39]
  PIN la_data_out[38]
    DIRECTION OUTPUT ;
    USE SIGNAL ;
    ANTENNADIFFAREA 0.43675 LAYER met2  ;
    ANTENNAPARTIALMETALAREA 4.4435 LAYER met2  ;
    ANTENNAPARTIALMETALSIDEAREA 22.1095 LAYER met2  ;
    PORT
      LAYER met2 ;
        RECT 1290.000000 0.000000 1290.140000 0.485000 ;
    END
  END la_data_out[38]
  PIN la_data_out[37]
    DIRECTION OUTPUT ;
    USE SIGNAL ;
    ANTENNADIFFAREA 0.43675 LAYER met2  ;
    ANTENNAPARTIALMETALAREA 4.4435 LAYER met2  ;
    ANTENNAPARTIALMETALSIDEAREA 22.1095 LAYER met2  ;
    PORT
      LAYER met2 ;
        RECT 1272.520000 0.000000 1272.660000 0.485000 ;
    END
  END la_data_out[37]
  PIN la_data_out[36]
    DIRECTION OUTPUT ;
    USE SIGNAL ;
    ANTENNADIFFAREA 0.43675 LAYER met2  ;
    ANTENNAPARTIALMETALAREA 4.5079 LAYER met2  ;
    ANTENNAPARTIALMETALSIDEAREA 22.4315 LAYER met2  ;
    PORT
      LAYER met2 ;
        RECT 1254.580000 0.000000 1254.720000 0.485000 ;
    END
  END la_data_out[36]
  PIN la_data_out[35]
    DIRECTION OUTPUT ;
    USE SIGNAL ;
    ANTENNADIFFAREA 0.43675 LAYER met2  ;
    ANTENNAPARTIALMETALAREA 4.4435 LAYER met2  ;
    ANTENNAPARTIALMETALSIDEAREA 22.1095 LAYER met2  ;
    PORT
      LAYER met2 ;
        RECT 1237.100000 0.000000 1237.240000 0.485000 ;
    END
  END la_data_out[35]
  PIN la_data_out[34]
    DIRECTION OUTPUT ;
    USE SIGNAL ;
    ANTENNADIFFAREA 0.43675 LAYER met2  ;
    ANTENNAPARTIALMETALAREA 4.4435 LAYER met2  ;
    ANTENNAPARTIALMETALSIDEAREA 22.1095 LAYER met2  ;
    PORT
      LAYER met2 ;
        RECT 1219.620000 0.000000 1219.760000 0.485000 ;
    END
  END la_data_out[34]
  PIN la_data_out[33]
    DIRECTION OUTPUT ;
    USE SIGNAL ;
    ANTENNADIFFAREA 0.43675 LAYER met2  ;
    ANTENNAPARTIALMETALAREA 4.4435 LAYER met2  ;
    ANTENNAPARTIALMETALSIDEAREA 22.1095 LAYER met2  ;
    PORT
      LAYER met2 ;
        RECT 1202.140000 0.000000 1202.280000 0.485000 ;
    END
  END la_data_out[33]
  PIN la_data_out[32]
    DIRECTION OUTPUT ;
    USE SIGNAL ;
    ANTENNADIFFAREA 0.43675 LAYER met2  ;
    ANTENNAPARTIALMETALAREA 4.7256 LAYER met2  ;
    ANTENNAPARTIALMETALSIDEAREA 23.52 LAYER met2  ;
    PORT
      LAYER met2 ;
        RECT 1184.660000 0.000000 1184.800000 0.485000 ;
    END
  END la_data_out[32]
  PIN la_data_out[31]
    DIRECTION OUTPUT ;
    USE SIGNAL ;
    ANTENNADIFFAREA 0.43675 LAYER met2  ;
    ANTENNAPARTIALMETALAREA 4.4435 LAYER met2  ;
    ANTENNAPARTIALMETALSIDEAREA 22.1095 LAYER met2  ;
    PORT
      LAYER met2 ;
        RECT 1167.180000 0.000000 1167.320000 0.485000 ;
    END
  END la_data_out[31]
  PIN la_data_out[30]
    DIRECTION OUTPUT ;
    USE SIGNAL ;
    ANTENNADIFFAREA 0.43675 LAYER met2  ;
    ANTENNAPARTIALMETALAREA 4.4435 LAYER met2  ;
    ANTENNAPARTIALMETALSIDEAREA 22.1095 LAYER met2  ;
    PORT
      LAYER met2 ;
        RECT 1149.700000 0.000000 1149.840000 0.485000 ;
    END
  END la_data_out[30]
  PIN la_data_out[29]
    DIRECTION OUTPUT ;
    USE SIGNAL ;
    ANTENNADIFFAREA 0.43675 LAYER met2  ;
    ANTENNAPARTIALMETALAREA 4.5079 LAYER met2  ;
    ANTENNAPARTIALMETALSIDEAREA 22.4315 LAYER met2  ;
    PORT
      LAYER met2 ;
        RECT 1132.220000 0.000000 1132.360000 0.485000 ;
    END
  END la_data_out[29]
  PIN la_data_out[28]
    DIRECTION OUTPUT ;
    USE SIGNAL ;
    ANTENNADIFFAREA 0.43675 LAYER met2  ;
    ANTENNAPARTIALMETALAREA 4.4435 LAYER met2  ;
    ANTENNAPARTIALMETALSIDEAREA 22.1095 LAYER met2  ;
    PORT
      LAYER met2 ;
        RECT 1114.740000 0.000000 1114.880000 0.485000 ;
    END
  END la_data_out[28]
  PIN la_data_out[27]
    DIRECTION OUTPUT ;
    USE SIGNAL ;
    ANTENNADIFFAREA 0.43675 LAYER met2  ;
    ANTENNAPARTIALMETALAREA 4.4435 LAYER met2  ;
    ANTENNAPARTIALMETALSIDEAREA 22.1095 LAYER met2  ;
    PORT
      LAYER met2 ;
        RECT 1097.260000 0.000000 1097.400000 0.485000 ;
    END
  END la_data_out[27]
  PIN la_data_out[26]
    DIRECTION OUTPUT ;
    USE SIGNAL ;
    ANTENNADIFFAREA 0.43675 LAYER met2  ;
    ANTENNAPARTIALMETALAREA 4.4435 LAYER met2  ;
    ANTENNAPARTIALMETALSIDEAREA 22.1095 LAYER met2  ;
    PORT
      LAYER met2 ;
        RECT 1079.780000 0.000000 1079.920000 0.485000 ;
    END
  END la_data_out[26]
  PIN la_data_out[25]
    DIRECTION OUTPUT ;
    USE SIGNAL ;
    ANTENNADIFFAREA 0.43675 LAYER met2  ;
    ANTENNAPARTIALMETALAREA 4.7256 LAYER met2  ;
    ANTENNAPARTIALMETALSIDEAREA 23.52 LAYER met2  ;
    PORT
      LAYER met2 ;
        RECT 1062.300000 0.000000 1062.440000 0.485000 ;
    END
  END la_data_out[25]
  PIN la_data_out[24]
    DIRECTION OUTPUT ;
    USE SIGNAL ;
    ANTENNADIFFAREA 0.43675 LAYER met2  ;
    ANTENNAPARTIALMETALAREA 4.4435 LAYER met2  ;
    ANTENNAPARTIALMETALSIDEAREA 22.1095 LAYER met2  ;
    PORT
      LAYER met2 ;
        RECT 1044.820000 0.000000 1044.960000 0.485000 ;
    END
  END la_data_out[24]
  PIN la_data_out[23]
    DIRECTION OUTPUT ;
    USE SIGNAL ;
    ANTENNADIFFAREA 0.43675 LAYER met2  ;
    ANTENNAPARTIALMETALAREA 4.4435 LAYER met2  ;
    ANTENNAPARTIALMETALSIDEAREA 22.1095 LAYER met2  ;
    PORT
      LAYER met2 ;
        RECT 1027.340000 0.000000 1027.480000 0.485000 ;
    END
  END la_data_out[23]
  PIN la_data_out[22]
    DIRECTION OUTPUT ;
    USE SIGNAL ;
    ANTENNADIFFAREA 0.43675 LAYER met2  ;
    ANTENNAPARTIALMETALAREA 4.5079 LAYER met2  ;
    ANTENNAPARTIALMETALSIDEAREA 22.4315 LAYER met2  ;
    PORT
      LAYER met2 ;
        RECT 1009.860000 0.000000 1010.000000 0.485000 ;
    END
  END la_data_out[22]
  PIN la_data_out[21]
    DIRECTION OUTPUT ;
    USE SIGNAL ;
    ANTENNADIFFAREA 0.43675 LAYER met2  ;
    ANTENNAPARTIALMETALAREA 4.4435 LAYER met2  ;
    ANTENNAPARTIALMETALSIDEAREA 22.1095 LAYER met2  ;
    PORT
      LAYER met2 ;
        RECT 992.380000 0.000000 992.520000 0.485000 ;
    END
  END la_data_out[21]
  PIN la_data_out[20]
    DIRECTION OUTPUT ;
    USE SIGNAL ;
    ANTENNADIFFAREA 0.43675 LAYER met2  ;
    ANTENNAPARTIALMETALAREA 4.4435 LAYER met2  ;
    ANTENNAPARTIALMETALSIDEAREA 22.1095 LAYER met2  ;
    PORT
      LAYER met2 ;
        RECT 974.900000 0.000000 975.040000 0.485000 ;
    END
  END la_data_out[20]
  PIN la_data_out[19]
    DIRECTION OUTPUT ;
    USE SIGNAL ;
    ANTENNADIFFAREA 0.43675 LAYER met2  ;
    ANTENNAPARTIALMETALAREA 4.4435 LAYER met2  ;
    ANTENNAPARTIALMETALSIDEAREA 22.1095 LAYER met2  ;
    PORT
      LAYER met2 ;
        RECT 957.420000 0.000000 957.560000 0.485000 ;
    END
  END la_data_out[19]
  PIN la_data_out[18]
    DIRECTION OUTPUT ;
    USE SIGNAL ;
    ANTENNADIFFAREA 0.43675 LAYER met2  ;
    ANTENNAPARTIALMETALAREA 4.79 LAYER met2  ;
    ANTENNAPARTIALMETALSIDEAREA 23.842 LAYER met2  ;
    PORT
      LAYER met2 ;
        RECT 939.940000 0.000000 940.080000 0.485000 ;
    END
  END la_data_out[18]
  PIN la_data_out[17]
    DIRECTION OUTPUT ;
    USE SIGNAL ;
    ANTENNADIFFAREA 0.43675 LAYER met2  ;
    ANTENNAPARTIALMETALAREA 4.4435 LAYER met2  ;
    ANTENNAPARTIALMETALSIDEAREA 22.1095 LAYER met2  ;
    PORT
      LAYER met2 ;
        RECT 922.460000 0.000000 922.600000 0.485000 ;
    END
  END la_data_out[17]
  PIN la_data_out[16]
    DIRECTION OUTPUT ;
    USE SIGNAL ;
    ANTENNADIFFAREA 0.43675 LAYER met2  ;
    ANTENNAPARTIALMETALAREA 4.4435 LAYER met2  ;
    ANTENNAPARTIALMETALSIDEAREA 22.1095 LAYER met2  ;
    PORT
      LAYER met2 ;
        RECT 904.520000 0.000000 904.660000 0.485000 ;
    END
  END la_data_out[16]
  PIN la_data_out[15]
    DIRECTION OUTPUT ;
    USE SIGNAL ;
    ANTENNADIFFAREA 0.43675 LAYER met2  ;
    ANTENNAPARTIALMETALAREA 4.5079 LAYER met2  ;
    ANTENNAPARTIALMETALSIDEAREA 22.4315 LAYER met2  ;
    PORT
      LAYER met2 ;
        RECT 887.040000 0.000000 887.180000 0.485000 ;
    END
  END la_data_out[15]
  PIN la_data_out[14]
    DIRECTION OUTPUT ;
    USE SIGNAL ;
    ANTENNADIFFAREA 0.43675 LAYER met2  ;
    ANTENNAPARTIALMETALAREA 4.4435 LAYER met2  ;
    ANTENNAPARTIALMETALSIDEAREA 22.1095 LAYER met2  ;
    PORT
      LAYER met2 ;
        RECT 869.560000 0.000000 869.700000 0.485000 ;
    END
  END la_data_out[14]
  PIN la_data_out[13]
    DIRECTION OUTPUT ;
    USE SIGNAL ;
    ANTENNADIFFAREA 0.43675 LAYER met2  ;
    ANTENNAPARTIALMETALAREA 4.4435 LAYER met2  ;
    ANTENNAPARTIALMETALSIDEAREA 22.1095 LAYER met2  ;
    PORT
      LAYER met2 ;
        RECT 852.080000 0.000000 852.220000 0.485000 ;
    END
  END la_data_out[13]
  PIN la_data_out[12]
    DIRECTION OUTPUT ;
    USE SIGNAL ;
    ANTENNADIFFAREA 0.43675 LAYER met2  ;
    ANTENNAPARTIALMETALAREA 4.4435 LAYER met2  ;
    ANTENNAPARTIALMETALSIDEAREA 22.1095 LAYER met2  ;
    PORT
      LAYER met2 ;
        RECT 834.600000 0.000000 834.740000 0.485000 ;
    END
  END la_data_out[12]
  PIN la_data_out[11]
    DIRECTION OUTPUT ;
    USE SIGNAL ;
    ANTENNADIFFAREA 0.43675 LAYER met2  ;
    ANTENNAPARTIALMETALAREA 4.7256 LAYER met2  ;
    ANTENNAPARTIALMETALSIDEAREA 23.52 LAYER met2  ;
    PORT
      LAYER met2 ;
        RECT 817.120000 0.000000 817.260000 0.485000 ;
    END
  END la_data_out[11]
  PIN la_data_out[10]
    DIRECTION OUTPUT ;
    USE SIGNAL ;
    ANTENNADIFFAREA 0.43675 LAYER met2  ;
    ANTENNAPARTIALMETALAREA 4.4435 LAYER met2  ;
    ANTENNAPARTIALMETALSIDEAREA 22.1095 LAYER met2  ;
    PORT
      LAYER met2 ;
        RECT 799.640000 0.000000 799.780000 0.485000 ;
    END
  END la_data_out[10]
  PIN la_data_out[9]
    DIRECTION OUTPUT ;
    USE SIGNAL ;
    ANTENNADIFFAREA 0.43675 LAYER met2  ;
    ANTENNAPARTIALMETALAREA 4.4435 LAYER met2  ;
    ANTENNAPARTIALMETALSIDEAREA 22.1095 LAYER met2  ;
    PORT
      LAYER met2 ;
        RECT 782.160000 0.000000 782.300000 0.485000 ;
    END
  END la_data_out[9]
  PIN la_data_out[8]
    DIRECTION OUTPUT ;
    USE SIGNAL ;
    ANTENNADIFFAREA 0.43675 LAYER met2  ;
    ANTENNAPARTIALMETALAREA 4.8887 LAYER met2  ;
    ANTENNAPARTIALMETALSIDEAREA 24.3355 LAYER met2  ;
    PORT
      LAYER met2 ;
        RECT 764.680000 0.000000 764.820000 0.485000 ;
    END
  END la_data_out[8]
  PIN la_data_out[7]
    DIRECTION OUTPUT ;
    USE SIGNAL ;
    ANTENNADIFFAREA 0.43675 LAYER met2  ;
    ANTENNAPARTIALMETALAREA 4.4435 LAYER met2  ;
    ANTENNAPARTIALMETALSIDEAREA 22.1095 LAYER met2  ;
    PORT
      LAYER met2 ;
        RECT 747.200000 0.000000 747.340000 0.485000 ;
    END
  END la_data_out[7]
  PIN la_data_out[6]
    DIRECTION OUTPUT ;
    USE SIGNAL ;
    ANTENNADIFFAREA 0.43675 LAYER met2  ;
    ANTENNAPARTIALMETALAREA 4.4435 LAYER met2  ;
    ANTENNAPARTIALMETALSIDEAREA 22.1095 LAYER met2  ;
    PORT
      LAYER met2 ;
        RECT 729.720000 0.000000 729.860000 0.485000 ;
    END
  END la_data_out[6]
  PIN la_data_out[5]
    DIRECTION OUTPUT ;
    USE SIGNAL ;
    ANTENNADIFFAREA 0.43675 LAYER met2  ;
    ANTENNAPARTIALMETALAREA 4.4435 LAYER met2  ;
    ANTENNAPARTIALMETALSIDEAREA 22.1095 LAYER met2  ;
    PORT
      LAYER met2 ;
        RECT 712.240000 0.000000 712.380000 0.485000 ;
    END
  END la_data_out[5]
  PIN la_data_out[4]
    DIRECTION OUTPUT ;
    USE SIGNAL ;
    ANTENNADIFFAREA 0.43675 LAYER met2  ;
    ANTENNAPARTIALMETALAREA 4.7256 LAYER met2  ;
    ANTENNAPARTIALMETALSIDEAREA 23.52 LAYER met2  ;
    PORT
      LAYER met2 ;
        RECT 694.760000 0.000000 694.900000 0.485000 ;
    END
  END la_data_out[4]
  PIN la_data_out[3]
    DIRECTION OUTPUT ;
    USE SIGNAL ;
    ANTENNADIFFAREA 0.43675 LAYER met2  ;
    ANTENNAPARTIALMETALAREA 4.4435 LAYER met2  ;
    ANTENNAPARTIALMETALSIDEAREA 22.1095 LAYER met2  ;
    PORT
      LAYER met2 ;
        RECT 677.280000 0.000000 677.420000 0.485000 ;
    END
  END la_data_out[3]
  PIN la_data_out[2]
    DIRECTION OUTPUT ;
    USE SIGNAL ;
    ANTENNADIFFAREA 0.43675 LAYER met2  ;
    ANTENNAPARTIALMETALAREA 4.4435 LAYER met2  ;
    ANTENNAPARTIALMETALSIDEAREA 22.1095 LAYER met2  ;
    PORT
      LAYER met2 ;
        RECT 659.800000 0.000000 659.940000 0.485000 ;
    END
  END la_data_out[2]
  PIN la_data_out[1]
    DIRECTION OUTPUT ;
    USE SIGNAL ;
    ANTENNADIFFAREA 0.43675 LAYER met2  ;
    ANTENNAPARTIALMETALAREA 4.5079 LAYER met2  ;
    ANTENNAPARTIALMETALSIDEAREA 22.4315 LAYER met2  ;
    PORT
      LAYER met2 ;
        RECT 642.320000 0.000000 642.460000 0.485000 ;
    END
  END la_data_out[1]
  PIN la_data_out[0]
    DIRECTION OUTPUT ;
    USE SIGNAL ;
    ANTENNADIFFAREA 0.43675 LAYER met2  ;
    ANTENNAPARTIALMETALAREA 4.4435 LAYER met2  ;
    ANTENNAPARTIALMETALSIDEAREA 22.1095 LAYER met2  ;
    PORT
      LAYER met2 ;
        RECT 624.840000 0.000000 624.980000 0.485000 ;
    END
  END la_data_out[0]
  PIN la_oenb[127]
    DIRECTION INPUT ;
    USE SIGNAL ;
    PORT
      LAYER met2 ;
        RECT 2853.540000 0.000000 2853.680000 0.485000 ;
    END
  END la_oenb[127]
  PIN la_oenb[126]
    DIRECTION INPUT ;
    USE SIGNAL ;
    PORT
      LAYER met2 ;
        RECT 2836.060000 0.000000 2836.200000 0.485000 ;
    END
  END la_oenb[126]
  PIN la_oenb[125]
    DIRECTION INPUT ;
    USE SIGNAL ;
    PORT
      LAYER met2 ;
        RECT 2818.580000 0.000000 2818.720000 0.485000 ;
    END
  END la_oenb[125]
  PIN la_oenb[124]
    DIRECTION INPUT ;
    USE SIGNAL ;
    PORT
      LAYER met2 ;
        RECT 2801.100000 0.000000 2801.240000 0.485000 ;
    END
  END la_oenb[124]
  PIN la_oenb[123]
    DIRECTION INPUT ;
    USE SIGNAL ;
    PORT
      LAYER met2 ;
        RECT 2783.620000 0.000000 2783.760000 0.485000 ;
    END
  END la_oenb[123]
  PIN la_oenb[122]
    DIRECTION INPUT ;
    USE SIGNAL ;
    PORT
      LAYER met2 ;
        RECT 2766.140000 0.000000 2766.280000 0.485000 ;
    END
  END la_oenb[122]
  PIN la_oenb[121]
    DIRECTION INPUT ;
    USE SIGNAL ;
    PORT
      LAYER met2 ;
        RECT 2748.200000 0.000000 2748.340000 0.485000 ;
    END
  END la_oenb[121]
  PIN la_oenb[120]
    DIRECTION INPUT ;
    USE SIGNAL ;
    PORT
      LAYER met2 ;
        RECT 2730.720000 0.000000 2730.860000 0.485000 ;
    END
  END la_oenb[120]
  PIN la_oenb[119]
    DIRECTION INPUT ;
    USE SIGNAL ;
    PORT
      LAYER met2 ;
        RECT 2713.240000 0.000000 2713.380000 0.485000 ;
    END
  END la_oenb[119]
  PIN la_oenb[118]
    DIRECTION INPUT ;
    USE SIGNAL ;
    PORT
      LAYER met2 ;
        RECT 2695.760000 0.000000 2695.900000 0.485000 ;
    END
  END la_oenb[118]
  PIN la_oenb[117]
    DIRECTION INPUT ;
    USE SIGNAL ;
    PORT
      LAYER met2 ;
        RECT 2678.280000 0.000000 2678.420000 0.485000 ;
    END
  END la_oenb[117]
  PIN la_oenb[116]
    DIRECTION INPUT ;
    USE SIGNAL ;
    PORT
      LAYER met2 ;
        RECT 2660.800000 0.000000 2660.940000 0.485000 ;
    END
  END la_oenb[116]
  PIN la_oenb[115]
    DIRECTION INPUT ;
    USE SIGNAL ;
    PORT
      LAYER met2 ;
        RECT 2643.320000 0.000000 2643.460000 0.485000 ;
    END
  END la_oenb[115]
  PIN la_oenb[114]
    DIRECTION INPUT ;
    USE SIGNAL ;
    PORT
      LAYER met2 ;
        RECT 2625.840000 0.000000 2625.980000 0.485000 ;
    END
  END la_oenb[114]
  PIN la_oenb[113]
    DIRECTION INPUT ;
    USE SIGNAL ;
    PORT
      LAYER met2 ;
        RECT 2608.360000 0.000000 2608.500000 0.485000 ;
    END
  END la_oenb[113]
  PIN la_oenb[112]
    DIRECTION INPUT ;
    USE SIGNAL ;
    PORT
      LAYER met2 ;
        RECT 2590.880000 0.000000 2591.020000 0.485000 ;
    END
  END la_oenb[112]
  PIN la_oenb[111]
    DIRECTION INPUT ;
    USE SIGNAL ;
    PORT
      LAYER met2 ;
        RECT 2573.400000 0.000000 2573.540000 0.485000 ;
    END
  END la_oenb[111]
  PIN la_oenb[110]
    DIRECTION INPUT ;
    USE SIGNAL ;
    PORT
      LAYER met2 ;
        RECT 2555.920000 0.000000 2556.060000 0.485000 ;
    END
  END la_oenb[110]
  PIN la_oenb[109]
    DIRECTION INPUT ;
    USE SIGNAL ;
    PORT
      LAYER met2 ;
        RECT 2538.440000 0.000000 2538.580000 0.485000 ;
    END
  END la_oenb[109]
  PIN la_oenb[108]
    DIRECTION INPUT ;
    USE SIGNAL ;
    PORT
      LAYER met2 ;
        RECT 2520.960000 0.000000 2521.100000 0.485000 ;
    END
  END la_oenb[108]
  PIN la_oenb[107]
    DIRECTION INPUT ;
    USE SIGNAL ;
    PORT
      LAYER met2 ;
        RECT 2503.480000 0.000000 2503.620000 0.485000 ;
    END
  END la_oenb[107]
  PIN la_oenb[106]
    DIRECTION INPUT ;
    USE SIGNAL ;
    PORT
      LAYER met2 ;
        RECT 2486.000000 0.000000 2486.140000 0.485000 ;
    END
  END la_oenb[106]
  PIN la_oenb[105]
    DIRECTION INPUT ;
    USE SIGNAL ;
    PORT
      LAYER met2 ;
        RECT 2468.520000 0.000000 2468.660000 0.485000 ;
    END
  END la_oenb[105]
  PIN la_oenb[104]
    DIRECTION INPUT ;
    USE SIGNAL ;
    PORT
      LAYER met2 ;
        RECT 2451.040000 0.000000 2451.180000 0.485000 ;
    END
  END la_oenb[104]
  PIN la_oenb[103]
    DIRECTION INPUT ;
    USE SIGNAL ;
    PORT
      LAYER met2 ;
        RECT 2433.560000 0.000000 2433.700000 0.485000 ;
    END
  END la_oenb[103]
  PIN la_oenb[102]
    DIRECTION INPUT ;
    USE SIGNAL ;
    PORT
      LAYER met2 ;
        RECT 2415.620000 0.000000 2415.760000 0.485000 ;
    END
  END la_oenb[102]
  PIN la_oenb[101]
    DIRECTION INPUT ;
    USE SIGNAL ;
    PORT
      LAYER met2 ;
        RECT 2398.140000 0.000000 2398.280000 0.485000 ;
    END
  END la_oenb[101]
  PIN la_oenb[100]
    DIRECTION INPUT ;
    USE SIGNAL ;
    PORT
      LAYER met2 ;
        RECT 2380.660000 0.000000 2380.800000 0.485000 ;
    END
  END la_oenb[100]
  PIN la_oenb[99]
    DIRECTION INPUT ;
    USE SIGNAL ;
    PORT
      LAYER met2 ;
        RECT 2363.180000 0.000000 2363.320000 0.485000 ;
    END
  END la_oenb[99]
  PIN la_oenb[98]
    DIRECTION INPUT ;
    USE SIGNAL ;
    PORT
      LAYER met2 ;
        RECT 2345.700000 0.000000 2345.840000 0.485000 ;
    END
  END la_oenb[98]
  PIN la_oenb[97]
    DIRECTION INPUT ;
    USE SIGNAL ;
    PORT
      LAYER met2 ;
        RECT 2328.220000 0.000000 2328.360000 0.485000 ;
    END
  END la_oenb[97]
  PIN la_oenb[96]
    DIRECTION INPUT ;
    USE SIGNAL ;
    PORT
      LAYER met2 ;
        RECT 2310.740000 0.000000 2310.880000 0.485000 ;
    END
  END la_oenb[96]
  PIN la_oenb[95]
    DIRECTION INPUT ;
    USE SIGNAL ;
    PORT
      LAYER met2 ;
        RECT 2293.260000 0.000000 2293.400000 0.485000 ;
    END
  END la_oenb[95]
  PIN la_oenb[94]
    DIRECTION INPUT ;
    USE SIGNAL ;
    PORT
      LAYER met2 ;
        RECT 2275.780000 0.000000 2275.920000 0.485000 ;
    END
  END la_oenb[94]
  PIN la_oenb[93]
    DIRECTION INPUT ;
    USE SIGNAL ;
    PORT
      LAYER met2 ;
        RECT 2258.300000 0.000000 2258.440000 0.485000 ;
    END
  END la_oenb[93]
  PIN la_oenb[92]
    DIRECTION INPUT ;
    USE SIGNAL ;
    PORT
      LAYER met2 ;
        RECT 2240.820000 0.000000 2240.960000 0.485000 ;
    END
  END la_oenb[92]
  PIN la_oenb[91]
    DIRECTION INPUT ;
    USE SIGNAL ;
    PORT
      LAYER met2 ;
        RECT 2223.340000 0.000000 2223.480000 0.485000 ;
    END
  END la_oenb[91]
  PIN la_oenb[90]
    DIRECTION INPUT ;
    USE SIGNAL ;
    PORT
      LAYER met2 ;
        RECT 2205.860000 0.000000 2206.000000 0.485000 ;
    END
  END la_oenb[90]
  PIN la_oenb[89]
    DIRECTION INPUT ;
    USE SIGNAL ;
    PORT
      LAYER met2 ;
        RECT 2188.380000 0.000000 2188.520000 0.485000 ;
    END
  END la_oenb[89]
  PIN la_oenb[88]
    DIRECTION INPUT ;
    USE SIGNAL ;
    PORT
      LAYER met2 ;
        RECT 2170.900000 0.000000 2171.040000 0.485000 ;
    END
  END la_oenb[88]
  PIN la_oenb[87]
    DIRECTION INPUT ;
    USE SIGNAL ;
    PORT
      LAYER met2 ;
        RECT 2153.420000 0.000000 2153.560000 0.485000 ;
    END
  END la_oenb[87]
  PIN la_oenb[86]
    DIRECTION INPUT ;
    USE SIGNAL ;
    PORT
      LAYER met2 ;
        RECT 2135.940000 0.000000 2136.080000 0.485000 ;
    END
  END la_oenb[86]
  PIN la_oenb[85]
    DIRECTION INPUT ;
    USE SIGNAL ;
    PORT
      LAYER met2 ;
        RECT 2118.460000 0.000000 2118.600000 0.485000 ;
    END
  END la_oenb[85]
  PIN la_oenb[84]
    DIRECTION INPUT ;
    USE SIGNAL ;
    PORT
      LAYER met2 ;
        RECT 2100.980000 0.000000 2101.120000 0.485000 ;
    END
  END la_oenb[84]
  PIN la_oenb[83]
    DIRECTION INPUT ;
    USE SIGNAL ;
    PORT
      LAYER met2 ;
        RECT 2083.500000 0.000000 2083.640000 0.485000 ;
    END
  END la_oenb[83]
  PIN la_oenb[82]
    DIRECTION INPUT ;
    USE SIGNAL ;
    PORT
      LAYER met2 ;
        RECT 2065.560000 0.000000 2065.700000 0.485000 ;
    END
  END la_oenb[82]
  PIN la_oenb[81]
    DIRECTION INPUT ;
    USE SIGNAL ;
    PORT
      LAYER met2 ;
        RECT 2048.080000 0.000000 2048.220000 0.485000 ;
    END
  END la_oenb[81]
  PIN la_oenb[80]
    DIRECTION INPUT ;
    USE SIGNAL ;
    PORT
      LAYER met2 ;
        RECT 2030.600000 0.000000 2030.740000 0.485000 ;
    END
  END la_oenb[80]
  PIN la_oenb[79]
    DIRECTION INPUT ;
    USE SIGNAL ;
    PORT
      LAYER met2 ;
        RECT 2013.120000 0.000000 2013.260000 0.485000 ;
    END
  END la_oenb[79]
  PIN la_oenb[78]
    DIRECTION INPUT ;
    USE SIGNAL ;
    PORT
      LAYER met2 ;
        RECT 1995.640000 0.000000 1995.780000 0.485000 ;
    END
  END la_oenb[78]
  PIN la_oenb[77]
    DIRECTION INPUT ;
    USE SIGNAL ;
    PORT
      LAYER met2 ;
        RECT 1978.160000 0.000000 1978.300000 0.485000 ;
    END
  END la_oenb[77]
  PIN la_oenb[76]
    DIRECTION INPUT ;
    USE SIGNAL ;
    PORT
      LAYER met2 ;
        RECT 1960.680000 0.000000 1960.820000 0.485000 ;
    END
  END la_oenb[76]
  PIN la_oenb[75]
    DIRECTION INPUT ;
    USE SIGNAL ;
    PORT
      LAYER met2 ;
        RECT 1943.200000 0.000000 1943.340000 0.485000 ;
    END
  END la_oenb[75]
  PIN la_oenb[74]
    DIRECTION INPUT ;
    USE SIGNAL ;
    PORT
      LAYER met2 ;
        RECT 1925.720000 0.000000 1925.860000 0.485000 ;
    END
  END la_oenb[74]
  PIN la_oenb[73]
    DIRECTION INPUT ;
    USE SIGNAL ;
    PORT
      LAYER met2 ;
        RECT 1908.240000 0.000000 1908.380000 0.485000 ;
    END
  END la_oenb[73]
  PIN la_oenb[72]
    DIRECTION INPUT ;
    USE SIGNAL ;
    PORT
      LAYER met2 ;
        RECT 1890.760000 0.000000 1890.900000 0.485000 ;
    END
  END la_oenb[72]
  PIN la_oenb[71]
    DIRECTION INPUT ;
    USE SIGNAL ;
    PORT
      LAYER met2 ;
        RECT 1873.280000 0.000000 1873.420000 0.485000 ;
    END
  END la_oenb[71]
  PIN la_oenb[70]
    DIRECTION INPUT ;
    USE SIGNAL ;
    PORT
      LAYER met2 ;
        RECT 1855.800000 0.000000 1855.940000 0.485000 ;
    END
  END la_oenb[70]
  PIN la_oenb[69]
    DIRECTION INPUT ;
    USE SIGNAL ;
    PORT
      LAYER met2 ;
        RECT 1838.320000 0.000000 1838.460000 0.485000 ;
    END
  END la_oenb[69]
  PIN la_oenb[68]
    DIRECTION INPUT ;
    USE SIGNAL ;
    PORT
      LAYER met2 ;
        RECT 1820.840000 0.000000 1820.980000 0.485000 ;
    END
  END la_oenb[68]
  PIN la_oenb[67]
    DIRECTION INPUT ;
    USE SIGNAL ;
    PORT
      LAYER met2 ;
        RECT 1803.360000 0.000000 1803.500000 0.485000 ;
    END
  END la_oenb[67]
  PIN la_oenb[66]
    DIRECTION INPUT ;
    USE SIGNAL ;
    PORT
      LAYER met2 ;
        RECT 1785.880000 0.000000 1786.020000 0.485000 ;
    END
  END la_oenb[66]
  PIN la_oenb[65]
    DIRECTION INPUT ;
    USE SIGNAL ;
    PORT
      LAYER met2 ;
        RECT 1768.400000 0.000000 1768.540000 0.485000 ;
    END
  END la_oenb[65]
  PIN la_oenb[64]
    DIRECTION INPUT ;
    USE SIGNAL ;
    PORT
      LAYER met2 ;
        RECT 1750.920000 0.000000 1751.060000 0.485000 ;
    END
  END la_oenb[64]
  PIN la_oenb[63]
    DIRECTION INPUT ;
    USE SIGNAL ;
    PORT
      LAYER met2 ;
        RECT 1733.440000 0.000000 1733.580000 0.485000 ;
    END
  END la_oenb[63]
  PIN la_oenb[62]
    DIRECTION INPUT ;
    USE SIGNAL ;
    PORT
      LAYER met2 ;
        RECT 1715.500000 0.000000 1715.640000 0.485000 ;
    END
  END la_oenb[62]
  PIN la_oenb[61]
    DIRECTION INPUT ;
    USE SIGNAL ;
    PORT
      LAYER met2 ;
        RECT 1698.020000 0.000000 1698.160000 0.485000 ;
    END
  END la_oenb[61]
  PIN la_oenb[60]
    DIRECTION INPUT ;
    USE SIGNAL ;
    PORT
      LAYER met2 ;
        RECT 1680.540000 0.000000 1680.680000 0.485000 ;
    END
  END la_oenb[60]
  PIN la_oenb[59]
    DIRECTION INPUT ;
    USE SIGNAL ;
    PORT
      LAYER met2 ;
        RECT 1663.060000 0.000000 1663.200000 0.485000 ;
    END
  END la_oenb[59]
  PIN la_oenb[58]
    DIRECTION INPUT ;
    USE SIGNAL ;
    PORT
      LAYER met2 ;
        RECT 1645.580000 0.000000 1645.720000 0.485000 ;
    END
  END la_oenb[58]
  PIN la_oenb[57]
    DIRECTION INPUT ;
    USE SIGNAL ;
    PORT
      LAYER met2 ;
        RECT 1628.100000 0.000000 1628.240000 0.485000 ;
    END
  END la_oenb[57]
  PIN la_oenb[56]
    DIRECTION INPUT ;
    USE SIGNAL ;
    PORT
      LAYER met2 ;
        RECT 1610.620000 0.000000 1610.760000 0.485000 ;
    END
  END la_oenb[56]
  PIN la_oenb[55]
    DIRECTION INPUT ;
    USE SIGNAL ;
    PORT
      LAYER met2 ;
        RECT 1593.140000 0.000000 1593.280000 0.485000 ;
    END
  END la_oenb[55]
  PIN la_oenb[54]
    DIRECTION INPUT ;
    USE SIGNAL ;
    PORT
      LAYER met2 ;
        RECT 1575.660000 0.000000 1575.800000 0.485000 ;
    END
  END la_oenb[54]
  PIN la_oenb[53]
    DIRECTION INPUT ;
    USE SIGNAL ;
    PORT
      LAYER met2 ;
        RECT 1558.180000 0.000000 1558.320000 0.485000 ;
    END
  END la_oenb[53]
  PIN la_oenb[52]
    DIRECTION INPUT ;
    USE SIGNAL ;
    PORT
      LAYER met2 ;
        RECT 1540.700000 0.000000 1540.840000 0.485000 ;
    END
  END la_oenb[52]
  PIN la_oenb[51]
    DIRECTION INPUT ;
    USE SIGNAL ;
    PORT
      LAYER met2 ;
        RECT 1523.220000 0.000000 1523.360000 0.485000 ;
    END
  END la_oenb[51]
  PIN la_oenb[50]
    DIRECTION INPUT ;
    USE SIGNAL ;
    PORT
      LAYER met2 ;
        RECT 1505.740000 0.000000 1505.880000 0.485000 ;
    END
  END la_oenb[50]
  PIN la_oenb[49]
    DIRECTION INPUT ;
    USE SIGNAL ;
    PORT
      LAYER met2 ;
        RECT 1488.260000 0.000000 1488.400000 0.485000 ;
    END
  END la_oenb[49]
  PIN la_oenb[48]
    DIRECTION INPUT ;
    USE SIGNAL ;
    PORT
      LAYER met2 ;
        RECT 1470.780000 0.000000 1470.920000 0.485000 ;
    END
  END la_oenb[48]
  PIN la_oenb[47]
    DIRECTION INPUT ;
    USE SIGNAL ;
    PORT
      LAYER met2 ;
        RECT 1453.300000 0.000000 1453.440000 0.485000 ;
    END
  END la_oenb[47]
  PIN la_oenb[46]
    DIRECTION INPUT ;
    USE SIGNAL ;
    PORT
      LAYER met2 ;
        RECT 1435.820000 0.000000 1435.960000 0.485000 ;
    END
  END la_oenb[46]
  PIN la_oenb[45]
    DIRECTION INPUT ;
    USE SIGNAL ;
    PORT
      LAYER met2 ;
        RECT 1418.340000 0.000000 1418.480000 0.485000 ;
    END
  END la_oenb[45]
  PIN la_oenb[44]
    DIRECTION INPUT ;
    USE SIGNAL ;
    PORT
      LAYER met2 ;
        RECT 1400.860000 0.000000 1401.000000 0.485000 ;
    END
  END la_oenb[44]
  PIN la_oenb[43]
    DIRECTION INPUT ;
    USE SIGNAL ;
    PORT
      LAYER met2 ;
        RECT 1383.380000 0.000000 1383.520000 0.485000 ;
    END
  END la_oenb[43]
  PIN la_oenb[42]
    DIRECTION INPUT ;
    USE SIGNAL ;
    PORT
      LAYER met2 ;
        RECT 1365.440000 0.000000 1365.580000 0.485000 ;
    END
  END la_oenb[42]
  PIN la_oenb[41]
    DIRECTION INPUT ;
    USE SIGNAL ;
    PORT
      LAYER met2 ;
        RECT 1347.960000 0.000000 1348.100000 0.485000 ;
    END
  END la_oenb[41]
  PIN la_oenb[40]
    DIRECTION INPUT ;
    USE SIGNAL ;
    PORT
      LAYER met2 ;
        RECT 1330.480000 0.000000 1330.620000 0.485000 ;
    END
  END la_oenb[40]
  PIN la_oenb[39]
    DIRECTION INPUT ;
    USE SIGNAL ;
    PORT
      LAYER met2 ;
        RECT 1313.000000 0.000000 1313.140000 0.485000 ;
    END
  END la_oenb[39]
  PIN la_oenb[38]
    DIRECTION INPUT ;
    USE SIGNAL ;
    PORT
      LAYER met2 ;
        RECT 1295.520000 0.000000 1295.660000 0.485000 ;
    END
  END la_oenb[38]
  PIN la_oenb[37]
    DIRECTION INPUT ;
    USE SIGNAL ;
    PORT
      LAYER met2 ;
        RECT 1278.040000 0.000000 1278.180000 0.485000 ;
    END
  END la_oenb[37]
  PIN la_oenb[36]
    DIRECTION INPUT ;
    USE SIGNAL ;
    PORT
      LAYER met2 ;
        RECT 1260.560000 0.000000 1260.700000 0.485000 ;
    END
  END la_oenb[36]
  PIN la_oenb[35]
    DIRECTION INPUT ;
    USE SIGNAL ;
    PORT
      LAYER met2 ;
        RECT 1243.080000 0.000000 1243.220000 0.485000 ;
    END
  END la_oenb[35]
  PIN la_oenb[34]
    DIRECTION INPUT ;
    USE SIGNAL ;
    PORT
      LAYER met2 ;
        RECT 1225.600000 0.000000 1225.740000 0.485000 ;
    END
  END la_oenb[34]
  PIN la_oenb[33]
    DIRECTION INPUT ;
    USE SIGNAL ;
    PORT
      LAYER met2 ;
        RECT 1208.120000 0.000000 1208.260000 0.485000 ;
    END
  END la_oenb[33]
  PIN la_oenb[32]
    DIRECTION INPUT ;
    USE SIGNAL ;
    PORT
      LAYER met2 ;
        RECT 1190.640000 0.000000 1190.780000 0.485000 ;
    END
  END la_oenb[32]
  PIN la_oenb[31]
    DIRECTION INPUT ;
    USE SIGNAL ;
    PORT
      LAYER met2 ;
        RECT 1173.160000 0.000000 1173.300000 0.485000 ;
    END
  END la_oenb[31]
  PIN la_oenb[30]
    DIRECTION INPUT ;
    USE SIGNAL ;
    PORT
      LAYER met2 ;
        RECT 1155.680000 0.000000 1155.820000 0.485000 ;
    END
  END la_oenb[30]
  PIN la_oenb[29]
    DIRECTION INPUT ;
    USE SIGNAL ;
    PORT
      LAYER met2 ;
        RECT 1138.200000 0.000000 1138.340000 0.485000 ;
    END
  END la_oenb[29]
  PIN la_oenb[28]
    DIRECTION INPUT ;
    USE SIGNAL ;
    PORT
      LAYER met2 ;
        RECT 1120.720000 0.000000 1120.860000 0.485000 ;
    END
  END la_oenb[28]
  PIN la_oenb[27]
    DIRECTION INPUT ;
    USE SIGNAL ;
    PORT
      LAYER met2 ;
        RECT 1103.240000 0.000000 1103.380000 0.485000 ;
    END
  END la_oenb[27]
  PIN la_oenb[26]
    DIRECTION INPUT ;
    USE SIGNAL ;
    PORT
      LAYER met2 ;
        RECT 1085.760000 0.000000 1085.900000 0.485000 ;
    END
  END la_oenb[26]
  PIN la_oenb[25]
    DIRECTION INPUT ;
    USE SIGNAL ;
    PORT
      LAYER met2 ;
        RECT 1068.280000 0.000000 1068.420000 0.485000 ;
    END
  END la_oenb[25]
  PIN la_oenb[24]
    DIRECTION INPUT ;
    USE SIGNAL ;
    PORT
      LAYER met2 ;
        RECT 1050.800000 0.000000 1050.940000 0.485000 ;
    END
  END la_oenb[24]
  PIN la_oenb[23]
    DIRECTION INPUT ;
    USE SIGNAL ;
    PORT
      LAYER met2 ;
        RECT 1032.860000 0.000000 1033.000000 0.485000 ;
    END
  END la_oenb[23]
  PIN la_oenb[22]
    DIRECTION INPUT ;
    USE SIGNAL ;
    PORT
      LAYER met2 ;
        RECT 1015.380000 0.000000 1015.520000 0.485000 ;
    END
  END la_oenb[22]
  PIN la_oenb[21]
    DIRECTION INPUT ;
    USE SIGNAL ;
    PORT
      LAYER met2 ;
        RECT 997.900000 0.000000 998.040000 0.485000 ;
    END
  END la_oenb[21]
  PIN la_oenb[20]
    DIRECTION INPUT ;
    USE SIGNAL ;
    PORT
      LAYER met2 ;
        RECT 980.420000 0.000000 980.560000 0.485000 ;
    END
  END la_oenb[20]
  PIN la_oenb[19]
    DIRECTION INPUT ;
    USE SIGNAL ;
    PORT
      LAYER met2 ;
        RECT 962.940000 0.000000 963.080000 0.485000 ;
    END
  END la_oenb[19]
  PIN la_oenb[18]
    DIRECTION INPUT ;
    USE SIGNAL ;
    PORT
      LAYER met2 ;
        RECT 945.460000 0.000000 945.600000 0.485000 ;
    END
  END la_oenb[18]
  PIN la_oenb[17]
    DIRECTION INPUT ;
    USE SIGNAL ;
    PORT
      LAYER met2 ;
        RECT 927.980000 0.000000 928.120000 0.485000 ;
    END
  END la_oenb[17]
  PIN la_oenb[16]
    DIRECTION INPUT ;
    USE SIGNAL ;
    PORT
      LAYER met2 ;
        RECT 910.500000 0.000000 910.640000 0.485000 ;
    END
  END la_oenb[16]
  PIN la_oenb[15]
    DIRECTION INPUT ;
    USE SIGNAL ;
    PORT
      LAYER met2 ;
        RECT 893.020000 0.000000 893.160000 0.485000 ;
    END
  END la_oenb[15]
  PIN la_oenb[14]
    DIRECTION INPUT ;
    USE SIGNAL ;
    PORT
      LAYER met2 ;
        RECT 875.540000 0.000000 875.680000 0.485000 ;
    END
  END la_oenb[14]
  PIN la_oenb[13]
    DIRECTION INPUT ;
    USE SIGNAL ;
    PORT
      LAYER met2 ;
        RECT 858.060000 0.000000 858.200000 0.485000 ;
    END
  END la_oenb[13]
  PIN la_oenb[12]
    DIRECTION INPUT ;
    USE SIGNAL ;
    PORT
      LAYER met2 ;
        RECT 840.580000 0.000000 840.720000 0.485000 ;
    END
  END la_oenb[12]
  PIN la_oenb[11]
    DIRECTION INPUT ;
    USE SIGNAL ;
    PORT
      LAYER met2 ;
        RECT 823.100000 0.000000 823.240000 0.485000 ;
    END
  END la_oenb[11]
  PIN la_oenb[10]
    DIRECTION INPUT ;
    USE SIGNAL ;
    PORT
      LAYER met2 ;
        RECT 805.620000 0.000000 805.760000 0.485000 ;
    END
  END la_oenb[10]
  PIN la_oenb[9]
    DIRECTION INPUT ;
    USE SIGNAL ;
    PORT
      LAYER met2 ;
        RECT 788.140000 0.000000 788.280000 0.485000 ;
    END
  END la_oenb[9]
  PIN la_oenb[8]
    DIRECTION INPUT ;
    USE SIGNAL ;
    PORT
      LAYER met2 ;
        RECT 770.660000 0.000000 770.800000 0.485000 ;
    END
  END la_oenb[8]
  PIN la_oenb[7]
    DIRECTION INPUT ;
    USE SIGNAL ;
    PORT
      LAYER met2 ;
        RECT 753.180000 0.000000 753.320000 0.485000 ;
    END
  END la_oenb[7]
  PIN la_oenb[6]
    DIRECTION INPUT ;
    USE SIGNAL ;
    PORT
      LAYER met2 ;
        RECT 735.700000 0.000000 735.840000 0.485000 ;
    END
  END la_oenb[6]
  PIN la_oenb[5]
    DIRECTION INPUT ;
    USE SIGNAL ;
    PORT
      LAYER met2 ;
        RECT 718.220000 0.000000 718.360000 0.485000 ;
    END
  END la_oenb[5]
  PIN la_oenb[4]
    DIRECTION INPUT ;
    USE SIGNAL ;
    PORT
      LAYER met2 ;
        RECT 700.740000 0.000000 700.880000 0.485000 ;
    END
  END la_oenb[4]
  PIN la_oenb[3]
    DIRECTION INPUT ;
    USE SIGNAL ;
    PORT
      LAYER met2 ;
        RECT 682.800000 0.000000 682.940000 0.485000 ;
    END
  END la_oenb[3]
  PIN la_oenb[2]
    DIRECTION INPUT ;
    USE SIGNAL ;
    PORT
      LAYER met2 ;
        RECT 665.320000 0.000000 665.460000 0.485000 ;
    END
  END la_oenb[2]
  PIN la_oenb[1]
    DIRECTION INPUT ;
    USE SIGNAL ;
    PORT
      LAYER met2 ;
        RECT 647.840000 0.000000 647.980000 0.485000 ;
    END
  END la_oenb[1]
  PIN la_oenb[0]
    DIRECTION INPUT ;
    USE SIGNAL ;
    PORT
      LAYER met2 ;
        RECT 630.360000 0.000000 630.500000 0.485000 ;
    END
  END la_oenb[0]
  PIN io_in[37]
    DIRECTION INPUT ;
    USE SIGNAL ;
    PORT
      LAYER met3 ;
        RECT 0.000000 170.100000 0.800000 170.400000 ;
    END
  END io_in[37]
  PIN io_in[36]
    DIRECTION INPUT ;
    USE SIGNAL ;
    ANTENNAPARTIALMETALAREA 0.6354 LAYER met3  ;
    ANTENNAPARTIALMETALSIDEAREA 3.832 LAYER met3  ;
    ANTENNAPARTIALCUTAREA 0.04 LAYER via3  ;
    ANTENNAPARTIALMETALAREA 3.9618 LAYER met4  ;
    ANTENNAPARTIALMETALSIDEAREA 21.6 LAYER met4  ;
    ANTENNAMODEL OXIDE1 ;
    ANTENNAGATEAREA 0.126 LAYER met4  ;
    ANTENNAMAXAREACAR 43.8147 LAYER met4  ;
    ANTENNAMAXSIDEAREACAR 228.04 LAYER met4  ;
    ANTENNAMAXCUTCAR 1.04286 LAYER via4  ;
    PORT
      LAYER met3 ;
        RECT 0.000000 424.470000 0.800000 424.770000 ;
    END
  END io_in[36]
  PIN io_in[35]
    DIRECTION INPUT ;
    USE SIGNAL ;
    PORT
      LAYER met3 ;
        RECT 0.000000 678.840000 0.800000 679.140000 ;
    END
  END io_in[35]
  PIN io_in[34]
    DIRECTION INPUT ;
    USE SIGNAL ;
    ANTENNAPARTIALMETALAREA 3.7524 LAYER met3  ;
    ANTENNAPARTIALMETALSIDEAREA 20.008 LAYER met3  ;
    ANTENNAMODEL OXIDE1 ;
    ANTENNAGATEAREA 0.2475 LAYER met3  ;
    ANTENNAMAXAREACAR 35.0289 LAYER met3  ;
    ANTENNAMAXSIDEAREACAR 177.956 LAYER met3  ;
    ANTENNAMAXCUTCAR 0.369293 LAYER via3  ;
    PORT
      LAYER met3 ;
        RECT 0.000000 933.210000 0.800000 933.510000 ;
    END
  END io_in[34]
  PIN io_in[33]
    DIRECTION INPUT ;
    USE SIGNAL ;
    PORT
      LAYER met3 ;
        RECT 0.000000 1187.580000 0.800000 1187.880000 ;
    END
  END io_in[33]
  PIN io_in[32]
    DIRECTION INPUT ;
    USE SIGNAL ;
    PORT
      LAYER met3 ;
        RECT 0.000000 1441.950000 0.800000 1442.250000 ;
    END
  END io_in[32]
  PIN io_in[31]
    DIRECTION INPUT ;
    USE SIGNAL ;
    PORT
      LAYER met3 ;
        RECT 0.000000 1696.320000 0.800000 1696.620000 ;
    END
  END io_in[31]
  PIN io_in[30]
    DIRECTION INPUT ;
    USE SIGNAL ;
    PORT
      LAYER met3 ;
        RECT 0.000000 1950.690000 0.800000 1950.990000 ;
    END
  END io_in[30]
  PIN io_in[29]
    DIRECTION INPUT ;
    USE SIGNAL ;
    PORT
      LAYER met3 ;
        RECT 0.000000 2205.060000 0.800000 2205.360000 ;
    END
  END io_in[29]
  PIN io_in[28]
    DIRECTION INPUT ;
    USE SIGNAL ;
    PORT
      LAYER met3 ;
        RECT 0.000000 2459.430000 0.800000 2459.730000 ;
    END
  END io_in[28]
  PIN io_in[27]
    DIRECTION INPUT ;
    USE SIGNAL ;
    PORT
      LAYER met3 ;
        RECT 0.000000 2713.800000 0.800000 2714.100000 ;
    END
  END io_in[27]
  PIN io_in[26]
    DIRECTION INPUT ;
    USE SIGNAL ;
    PORT
      LAYER met3 ;
        RECT 0.000000 2968.170000 0.800000 2968.470000 ;
    END
  END io_in[26]
  PIN io_in[25]
    DIRECTION INPUT ;
    USE SIGNAL ;
    PORT
      LAYER met3 ;
        RECT 0.000000 3222.540000 0.800000 3222.840000 ;
    END
  END io_in[25]
  PIN io_in[24]
    DIRECTION INPUT ;
    USE SIGNAL ;
    PORT
      LAYER met3 ;
        RECT 0.000000 3476.300000 0.800000 3476.600000 ;
    END
  END io_in[24]
  PIN io_in[23]
    DIRECTION INPUT ;
    USE SIGNAL ;
    PORT
      LAYER met2 ;
        RECT 221.420000 3476.695000 221.560000 3477.180000 ;
    END
  END io_in[23]
  PIN io_in[22]
    DIRECTION INPUT ;
    USE SIGNAL ;
    PORT
      LAYER met2 ;
        RECT 553.080000 3476.695000 553.220000 3477.180000 ;
    END
  END io_in[22]
  PIN io_in[21]
    DIRECTION INPUT ;
    USE SIGNAL ;
    PORT
      LAYER met2 ;
        RECT 885.200000 3476.695000 885.340000 3477.180000 ;
    END
  END io_in[21]
  PIN io_in[20]
    DIRECTION INPUT ;
    USE SIGNAL ;
    PORT
      LAYER met2 ;
        RECT 1216.860000 3476.695000 1217.000000 3477.180000 ;
    END
  END io_in[20]
  PIN io_in[19]
    DIRECTION INPUT ;
    USE SIGNAL ;
    PORT
      LAYER met2 ;
        RECT 1548.980000 3476.695000 1549.120000 3477.180000 ;
    END
  END io_in[19]
  PIN io_in[18]
    DIRECTION INPUT ;
    USE SIGNAL ;
    PORT
      LAYER met2 ;
        RECT 1880.640000 3476.695000 1880.780000 3477.180000 ;
    END
  END io_in[18]
  PIN io_in[17]
    DIRECTION INPUT ;
    USE SIGNAL ;
    PORT
      LAYER met2 ;
        RECT 2212.760000 3476.695000 2212.900000 3477.180000 ;
    END
  END io_in[17]
  PIN io_in[16]
    DIRECTION INPUT ;
    USE SIGNAL ;
    PORT
      LAYER met2 ;
        RECT 2544.420000 3476.695000 2544.560000 3477.180000 ;
    END
  END io_in[16]
  PIN io_in[15]
    DIRECTION INPUT ;
    USE SIGNAL ;
    PORT
      LAYER met2 ;
        RECT 2876.540000 3476.695000 2876.680000 3477.180000 ;
    END
  END io_in[15]
  PIN io_in[14]
    DIRECTION INPUT ;
    USE SIGNAL ;
    PORT
      LAYER met3 ;
        RECT 2876.040000 3318.920000 2876.840000 3319.220000 ;
    END
  END io_in[14]
  PIN io_in[13]
    DIRECTION INPUT ;
    USE SIGNAL ;
    PORT
      LAYER met3 ;
        RECT 2876.040000 3082.240000 2876.840000 3082.540000 ;
    END
  END io_in[13]
  PIN io_in[12]
    DIRECTION INPUT ;
    USE SIGNAL ;
    PORT
      LAYER met3 ;
        RECT 2876.040000 2844.950000 2876.840000 2845.250000 ;
    END
  END io_in[12]
  PIN io_in[11]
    DIRECTION INPUT ;
    USE SIGNAL ;
    PORT
      LAYER met3 ;
        RECT 2876.040000 2608.270000 2876.840000 2608.570000 ;
    END
  END io_in[11]
  PIN io_in[10]
    DIRECTION INPUT ;
    USE SIGNAL ;
    PORT
      LAYER met3 ;
        RECT 2876.040000 2370.980000 2876.840000 2371.280000 ;
    END
  END io_in[10]
  PIN io_in[9]
    DIRECTION INPUT ;
    USE SIGNAL ;
    PORT
      LAYER met3 ;
        RECT 2876.040000 2134.300000 2876.840000 2134.600000 ;
    END
  END io_in[9]
  PIN io_in[8]
    DIRECTION INPUT ;
    USE SIGNAL ;
    PORT
      LAYER met3 ;
        RECT 2876.040000 1897.010000 2876.840000 1897.310000 ;
    END
  END io_in[8]
  PIN io_in[7]
    DIRECTION INPUT ;
    USE SIGNAL ;
    PORT
      LAYER met3 ;
        RECT 2876.040000 1659.720000 2876.840000 1660.020000 ;
    END
  END io_in[7]
  PIN io_in[6]
    DIRECTION INPUT ;
    USE SIGNAL ;
    PORT
      LAYER met3 ;
        RECT 2876.040000 1423.040000 2876.840000 1423.340000 ;
    END
  END io_in[6]
  PIN io_in[5]
    DIRECTION INPUT ;
    USE SIGNAL ;
    PORT
      LAYER met3 ;
        RECT 2876.040000 1185.750000 2876.840000 1186.050000 ;
    END
  END io_in[5]
  PIN io_in[4]
    DIRECTION INPUT ;
    USE SIGNAL ;
    PORT
      LAYER met3 ;
        RECT 2876.040000 949.070000 2876.840000 949.370000 ;
    END
  END io_in[4]
  PIN io_in[3]
    DIRECTION INPUT ;
    USE SIGNAL ;
    PORT
      LAYER met3 ;
        RECT 2876.040000 711.780000 2876.840000 712.080000 ;
    END
  END io_in[3]
  PIN io_in[2]
    DIRECTION INPUT ;
    USE SIGNAL ;
    PORT
      LAYER met3 ;
        RECT 2876.040000 475.100000 2876.840000 475.400000 ;
    END
  END io_in[2]
  PIN io_in[1]
    DIRECTION INPUT ;
    USE SIGNAL ;
    PORT
      LAYER met3 ;
        RECT 2876.040000 237.810000 2876.840000 238.110000 ;
    END
  END io_in[1]
  PIN io_in[0]
    DIRECTION INPUT ;
    USE SIGNAL ;
    PORT
      LAYER met3 ;
        RECT 2876.040000 0.520000 2876.840000 0.820000 ;
    END
  END io_in[0]
  PIN io_out[37]
    DIRECTION OUTPUT ;
    USE SIGNAL ;
    ANTENNADIFFAREA 0.3406 LAYER met3  ;
    ANTENNAPARTIALMETALAREA 0.5784 LAYER met3  ;
    ANTENNAPARTIALMETALSIDEAREA 3.08 LAYER met3  ;
    PORT
      LAYER met3 ;
        RECT 0.000000 85.310000 0.800000 85.610000 ;
    END
  END io_out[37]
  PIN io_out[36]
    DIRECTION OUTPUT ;
    USE SIGNAL ;
    ANTENNADIFFAREA 0.43675 LAYER met3  ;
    ANTENNAPARTIALMETALAREA 4.9944 LAYER met3  ;
    ANTENNAPARTIALMETALSIDEAREA 26.632 LAYER met3  ;
    PORT
      LAYER met3 ;
        RECT 0.000000 339.680000 0.800000 339.980000 ;
    END
  END io_out[36]
  PIN io_out[35]
    DIRECTION OUTPUT ;
    USE SIGNAL ;
    ANTENNADIFFAREA 0.3406 LAYER met3  ;
    ANTENNAPARTIALMETALAREA 0.3024 LAYER met3  ;
    ANTENNAPARTIALMETALSIDEAREA 1.608 LAYER met3  ;
    PORT
      LAYER met3 ;
        RECT 0.000000 594.050000 0.800000 594.350000 ;
    END
  END io_out[35]
  PIN io_out[34]
    DIRECTION OUTPUT ;
    USE SIGNAL ;
    ANTENNADIFFAREA 0.43675 LAYER met3  ;
    ANTENNAPARTIALMETALAREA 8.9964 LAYER met3  ;
    ANTENNAPARTIALMETALSIDEAREA 47.976 LAYER met3  ;
    PORT
      LAYER met3 ;
        RECT 0.000000 848.420000 0.800000 848.720000 ;
    END
  END io_out[34]
  PIN io_out[33]
    DIRECTION OUTPUT ;
    USE SIGNAL ;
    ANTENNADIFFAREA 0.43675 LAYER met3  ;
    ANTENNAPARTIALMETALAREA 0.1644 LAYER met3  ;
    ANTENNAPARTIALMETALSIDEAREA 0.872 LAYER met3  ;
    PORT
      LAYER met3 ;
        RECT 0.000000 1102.790000 0.800000 1103.090000 ;
    END
  END io_out[33]
  PIN io_out[32]
    DIRECTION OUTPUT ;
    USE SIGNAL ;
    ANTENNADIFFAREA 0.43675 LAYER met3  ;
    ANTENNAPARTIALMETALAREA 9.4104 LAYER met3  ;
    ANTENNAPARTIALMETALSIDEAREA 50.184 LAYER met3  ;
    PORT
      LAYER met3 ;
        RECT 0.000000 1357.160000 0.800000 1357.460000 ;
    END
  END io_out[32]
  PIN io_out[31]
    DIRECTION OUTPUT ;
    USE SIGNAL ;
    ANTENNADIFFAREA 0.43675 LAYER met3  ;
    ANTENNAPARTIALMETALAREA 8.7204 LAYER met3  ;
    ANTENNAPARTIALMETALSIDEAREA 46.504 LAYER met3  ;
    PORT
      LAYER met3 ;
        RECT 0.000000 1611.530000 0.800000 1611.830000 ;
    END
  END io_out[31]
  PIN io_out[30]
    DIRECTION OUTPUT ;
    USE SIGNAL ;
    ANTENNADIFFAREA 0.43675 LAYER met3  ;
    ANTENNAPARTIALMETALAREA 9.5484 LAYER met3  ;
    ANTENNAPARTIALMETALSIDEAREA 50.92 LAYER met3  ;
    PORT
      LAYER met3 ;
        RECT 0.000000 1865.900000 0.800000 1866.200000 ;
    END
  END io_out[30]
  PIN io_out[29]
    DIRECTION OUTPUT ;
    USE SIGNAL ;
    ANTENNADIFFAREA 0.43675 LAYER met3  ;
    ANTENNAPARTIALMETALAREA 1.2684 LAYER met3  ;
    ANTENNAPARTIALMETALSIDEAREA 6.76 LAYER met3  ;
    PORT
      LAYER met3 ;
        RECT 0.000000 2120.270000 0.800000 2120.570000 ;
    END
  END io_out[29]
  PIN io_out[28]
    DIRECTION OUTPUT ;
    USE SIGNAL ;
    ANTENNADIFFAREA 0.43675 LAYER met3  ;
    ANTENNAPARTIALMETALAREA 0.1644 LAYER met3  ;
    ANTENNAPARTIALMETALSIDEAREA 0.872 LAYER met3  ;
    PORT
      LAYER met3 ;
        RECT 0.000000 2374.640000 0.800000 2374.940000 ;
    END
  END io_out[28]
  PIN io_out[27]
    DIRECTION OUTPUT ;
    USE SIGNAL ;
    ANTENNADIFFAREA 0.43675 LAYER met3  ;
    ANTENNAPARTIALMETALAREA 0.1644 LAYER met3  ;
    ANTENNAPARTIALMETALSIDEAREA 0.872 LAYER met3  ;
    PORT
      LAYER met3 ;
        RECT 0.000000 2629.010000 0.800000 2629.310000 ;
    END
  END io_out[27]
  PIN io_out[26]
    DIRECTION OUTPUT ;
    USE SIGNAL ;
    ANTENNADIFFAREA 0.43675 LAYER met3  ;
    ANTENNAPARTIALMETALAREA 8.9964 LAYER met3  ;
    ANTENNAPARTIALMETALSIDEAREA 47.976 LAYER met3  ;
    PORT
      LAYER met3 ;
        RECT 0.000000 2883.380000 0.800000 2883.680000 ;
    END
  END io_out[26]
  PIN io_out[25]
    DIRECTION OUTPUT ;
    USE SIGNAL ;
    ANTENNADIFFAREA 0.43675 LAYER met3  ;
    ANTENNAPARTIALMETALAREA 8.1684 LAYER met3  ;
    ANTENNAPARTIALMETALSIDEAREA 43.56 LAYER met3  ;
    PORT
      LAYER met3 ;
        RECT 0.000000 3137.750000 0.800000 3138.050000 ;
    END
  END io_out[25]
  PIN io_out[24]
    DIRECTION OUTPUT ;
    USE SIGNAL ;
    ANTENNADIFFAREA 0.43675 LAYER met3  ;
    ANTENNAPARTIALMETALAREA 8.8584 LAYER met3  ;
    ANTENNAPARTIALMETALSIDEAREA 47.24 LAYER met3  ;
    PORT
      LAYER met3 ;
        RECT 0.000000 3392.120000 0.800000 3392.420000 ;
    END
  END io_out[24]
  PIN io_out[23]
    DIRECTION OUTPUT ;
    USE SIGNAL ;
    ANTENNADIFFAREA 0.43675 LAYER met2  ;
    ANTENNAPARTIALMETALAREA 4.8677 LAYER met2  ;
    ANTENNAPARTIALMETALSIDEAREA 24.2305 LAYER met2  ;
    PORT
      LAYER met2 ;
        RECT 110.560000 3476.695000 110.700000 3477.180000 ;
    END
  END io_out[23]
  PIN io_out[22]
    DIRECTION OUTPUT ;
    USE SIGNAL ;
    ANTENNADIFFAREA 0.43675 LAYER met2  ;
    ANTENNAPARTIALMETALAREA 4.5863 LAYER met2  ;
    ANTENNAPARTIALMETALSIDEAREA 22.8235 LAYER met2  ;
    PORT
      LAYER met2 ;
        RECT 442.680000 3476.695000 442.820000 3477.180000 ;
    END
  END io_out[22]
  PIN io_out[21]
    DIRECTION OUTPUT ;
    USE SIGNAL ;
    ANTENNADIFFAREA 0.43675 LAYER met2  ;
    ANTENNAPARTIALMETALAREA 4.5863 LAYER met2  ;
    ANTENNAPARTIALMETALSIDEAREA 22.8235 LAYER met2  ;
    PORT
      LAYER met2 ;
        RECT 774.340000 3476.695000 774.480000 3477.180000 ;
    END
  END io_out[21]
  PIN io_out[20]
    DIRECTION OUTPUT ;
    USE SIGNAL ;
    ANTENNADIFFAREA 0.43675 LAYER met2  ;
    ANTENNAPARTIALMETALAREA 4.5863 LAYER met2  ;
    ANTENNAPARTIALMETALSIDEAREA 22.8235 LAYER met2  ;
    PORT
      LAYER met2 ;
        RECT 1106.460000 3476.695000 1106.600000 3477.180000 ;
    END
  END io_out[20]
  PIN io_out[19]
    DIRECTION OUTPUT ;
    USE SIGNAL ;
    ANTENNADIFFAREA 0.43675 LAYER met2  ;
    ANTENNAPARTIALMETALAREA 4.5863 LAYER met2  ;
    ANTENNAPARTIALMETALSIDEAREA 22.8235 LAYER met2  ;
    PORT
      LAYER met2 ;
        RECT 1438.120000 3476.695000 1438.260000 3477.180000 ;
    END
  END io_out[19]
  PIN io_out[18]
    DIRECTION OUTPUT ;
    USE SIGNAL ;
    ANTENNADIFFAREA 0.43675 LAYER met2  ;
    ANTENNAPARTIALMETALAREA 4.7795 LAYER met2  ;
    ANTENNAPARTIALMETALSIDEAREA 23.7895 LAYER met2  ;
    PORT
      LAYER met2 ;
        RECT 1770.240000 3476.695000 1770.380000 3477.180000 ;
    END
  END io_out[18]
  PIN io_out[17]
    DIRECTION OUTPUT ;
    USE SIGNAL ;
    ANTENNADIFFAREA 0.43675 LAYER met2  ;
    ANTENNAPARTIALMETALAREA 4.5863 LAYER met2  ;
    ANTENNAPARTIALMETALSIDEAREA 22.8235 LAYER met2  ;
    PORT
      LAYER met2 ;
        RECT 2101.900000 3476.695000 2102.040000 3477.180000 ;
    END
  END io_out[17]
  PIN io_out[16]
    DIRECTION OUTPUT ;
    USE SIGNAL ;
    ANTENNADIFFAREA 0.43675 LAYER met2  ;
    ANTENNAPARTIALMETALAREA 4.5863 LAYER met2  ;
    ANTENNAPARTIALMETALSIDEAREA 22.8235 LAYER met2  ;
    PORT
      LAYER met2 ;
        RECT 2434.020000 3476.695000 2434.160000 3477.180000 ;
    END
  END io_out[16]
  PIN io_out[15]
    DIRECTION OUTPUT ;
    USE SIGNAL ;
    ANTENNADIFFAREA 0.43675 LAYER met2  ;
    ANTENNAPARTIALMETALAREA 4.5863 LAYER met2  ;
    ANTENNAPARTIALMETALSIDEAREA 22.8235 LAYER met2  ;
    PORT
      LAYER met2 ;
        RECT 2765.680000 3476.695000 2765.820000 3477.180000 ;
    END
  END io_out[15]
  PIN io_out[14]
    DIRECTION OUTPUT ;
    USE SIGNAL ;
    ANTENNADIFFAREA 0.43675 LAYER met3  ;
    ANTENNAPARTIALMETALAREA 0.1644 LAYER met3  ;
    ANTENNAPARTIALMETALSIDEAREA 0.872 LAYER met3  ;
    PORT
      LAYER met3 ;
        RECT 2876.040000 3398.220000 2876.840000 3398.520000 ;
    END
  END io_out[14]
  PIN io_out[13]
    DIRECTION OUTPUT ;
    USE SIGNAL ;
    ANTENNADIFFAREA 0.43675 LAYER met3  ;
    ANTENNAPARTIALMETALAREA 10.7904 LAYER met3  ;
    ANTENNAPARTIALMETALSIDEAREA 57.544 LAYER met3  ;
    PORT
      LAYER met3 ;
        RECT 2876.040000 3160.930000 2876.840000 3161.230000 ;
    END
  END io_out[13]
  PIN io_out[12]
    DIRECTION OUTPUT ;
    USE SIGNAL ;
    ANTENNADIFFAREA 0.43675 LAYER met3  ;
    ANTENNAPARTIALMETALAREA 0.1644 LAYER met3  ;
    ANTENNAPARTIALMETALSIDEAREA 0.872 LAYER met3  ;
    PORT
      LAYER met3 ;
        RECT 2876.040000 2924.250000 2876.840000 2924.550000 ;
    END
  END io_out[12]
  PIN io_out[11]
    DIRECTION OUTPUT ;
    USE SIGNAL ;
    ANTENNADIFFAREA 0.43675 LAYER met3  ;
    ANTENNAPARTIALMETALAREA 9.1344 LAYER met3  ;
    ANTENNAPARTIALMETALSIDEAREA 48.712 LAYER met3  ;
    PORT
      LAYER met3 ;
        RECT 2876.040000 2686.960000 2876.840000 2687.260000 ;
    END
  END io_out[11]
  PIN io_out[10]
    DIRECTION OUTPUT ;
    USE SIGNAL ;
    ANTENNADIFFAREA 0.43675 LAYER met3  ;
    ANTENNAPARTIALMETALAREA 0.1644 LAYER met3  ;
    ANTENNAPARTIALMETALSIDEAREA 0.872 LAYER met3  ;
    PORT
      LAYER met3 ;
        RECT 2876.040000 2450.280000 2876.840000 2450.580000 ;
    END
  END io_out[10]
  PIN io_out[9]
    DIRECTION OUTPUT ;
    USE SIGNAL ;
    ANTENNADIFFAREA 0.43675 LAYER met3  ;
    ANTENNAPARTIALMETALAREA 0.1644 LAYER met3  ;
    ANTENNAPARTIALMETALSIDEAREA 0.872 LAYER met3  ;
    PORT
      LAYER met3 ;
        RECT 2876.040000 2212.990000 2876.840000 2213.290000 ;
    END
  END io_out[9]
  PIN io_out[8]
    DIRECTION OUTPUT ;
    USE SIGNAL ;
    ANTENNADIFFAREA 0.43675 LAYER met3  ;
    ANTENNAPARTIALMETALAREA 8.9964 LAYER met3  ;
    ANTENNAPARTIALMETALSIDEAREA 47.976 LAYER met3  ;
    PORT
      LAYER met3 ;
        RECT 2876.040000 1976.310000 2876.840000 1976.610000 ;
    END
  END io_out[8]
  PIN io_out[7]
    DIRECTION OUTPUT ;
    USE SIGNAL ;
    ANTENNADIFFAREA 0.43675 LAYER met3  ;
    ANTENNAPARTIALMETALAREA 0.1644 LAYER met3  ;
    ANTENNAPARTIALMETALSIDEAREA 0.872 LAYER met3  ;
    PORT
      LAYER met3 ;
        RECT 2876.040000 1739.020000 2876.840000 1739.320000 ;
    END
  END io_out[7]
  PIN io_out[6]
    DIRECTION OUTPUT ;
    USE SIGNAL ;
    ANTENNADIFFAREA 0.43675 LAYER met3  ;
    ANTENNAPARTIALMETALAREA 8.9964 LAYER met3  ;
    ANTENNAPARTIALMETALSIDEAREA 47.976 LAYER met3  ;
    PORT
      LAYER met3 ;
        RECT 2876.040000 1501.730000 2876.840000 1502.030000 ;
    END
  END io_out[6]
  PIN io_out[5]
    DIRECTION OUTPUT ;
    USE SIGNAL ;
    ANTENNADIFFAREA 0.43675 LAYER met3  ;
    ANTENNAPARTIALMETALAREA 8.9964 LAYER met3  ;
    ANTENNAPARTIALMETALSIDEAREA 47.976 LAYER met3  ;
    PORT
      LAYER met3 ;
        RECT 2876.040000 1265.050000 2876.840000 1265.350000 ;
    END
  END io_out[5]
  PIN io_out[4]
    DIRECTION OUTPUT ;
    USE SIGNAL ;
    ANTENNADIFFAREA 0.43675 LAYER met3  ;
    ANTENNAPARTIALMETALAREA 0.1644 LAYER met3  ;
    ANTENNAPARTIALMETALSIDEAREA 0.872 LAYER met3  ;
    PORT
      LAYER met3 ;
        RECT 2876.040000 1027.760000 2876.840000 1028.060000 ;
    END
  END io_out[4]
  PIN io_out[3]
    DIRECTION OUTPUT ;
    USE SIGNAL ;
    ANTENNADIFFAREA 0.43675 LAYER met3  ;
    ANTENNAPARTIALMETALAREA 10.5144 LAYER met3  ;
    ANTENNAPARTIALMETALSIDEAREA 56.072 LAYER met3  ;
    PORT
      LAYER met3 ;
        RECT 2876.040000 791.080000 2876.840000 791.380000 ;
    END
  END io_out[3]
  PIN io_out[2]
    DIRECTION OUTPUT ;
    USE SIGNAL ;
    ANTENNADIFFAREA 0.43675 LAYER met3  ;
    ANTENNAPARTIALMETALAREA 9.1344 LAYER met3  ;
    ANTENNAPARTIALMETALSIDEAREA 48.712 LAYER met3  ;
    PORT
      LAYER met3 ;
        RECT 2876.040000 553.790000 2876.840000 554.090000 ;
    END
  END io_out[2]
  PIN io_out[1]
    DIRECTION OUTPUT ;
    USE SIGNAL ;
    ANTENNADIFFAREA 0.43675 LAYER met3  ;
    ANTENNAPARTIALMETALAREA 8.9964 LAYER met3  ;
    ANTENNAPARTIALMETALSIDEAREA 47.976 LAYER met3  ;
    PORT
      LAYER met3 ;
        RECT 2876.040000 317.110000 2876.840000 317.410000 ;
    END
  END io_out[1]
  PIN io_out[0]
    DIRECTION OUTPUT ;
    USE SIGNAL ;
    ANTENNADIFFAREA 0.43675 LAYER met3  ;
    ANTENNAPARTIALMETALAREA 10.6524 LAYER met3  ;
    ANTENNAPARTIALMETALSIDEAREA 56.808 LAYER met3  ;
    PORT
      LAYER met3 ;
        RECT 2876.040000 79.820000 2876.840000 80.120000 ;
    END
  END io_out[0]
  PIN io_oeb[37]
    DIRECTION OUTPUT ;
    USE SIGNAL ;
    ANTENNADIFFAREA 0.43675 LAYER met3  ;
    ANTENNAPARTIALMETALAREA 11.3424 LAYER met3  ;
    ANTENNAPARTIALMETALSIDEAREA 60.488 LAYER met3  ;
    PORT
      LAYER met3 ;
        RECT 0.000000 0.520000 0.800000 0.820000 ;
    END
  END io_oeb[37]
  PIN io_oeb[36]
    DIRECTION OUTPUT ;
    USE SIGNAL ;
    ANTENNADIFFAREA 0.43675 LAYER met3  ;
    ANTENNAPARTIALMETALAREA 9.5484 LAYER met3  ;
    ANTENNAPARTIALMETALSIDEAREA 50.92 LAYER met3  ;
    PORT
      LAYER met3 ;
        RECT 0.000000 254.890000 0.800000 255.190000 ;
    END
  END io_oeb[36]
  PIN io_oeb[35]
    DIRECTION OUTPUT ;
    USE SIGNAL ;
    ANTENNADIFFAREA 0.43675 LAYER met3  ;
    ANTENNAPARTIALMETALAREA 2.6484 LAYER met3  ;
    ANTENNAPARTIALMETALSIDEAREA 14.12 LAYER met3  ;
    PORT
      LAYER met3 ;
        RECT 0.000000 509.260000 0.800000 509.560000 ;
    END
  END io_oeb[35]
  PIN io_oeb[34]
    DIRECTION OUTPUT ;
    USE SIGNAL ;
    ANTENNADIFFAREA 0.43675 LAYER met3  ;
    ANTENNAPARTIALMETALAREA 0.1644 LAYER met3  ;
    ANTENNAPARTIALMETALSIDEAREA 0.872 LAYER met3  ;
    PORT
      LAYER met3 ;
        RECT 0.000000 763.630000 0.800000 763.930000 ;
    END
  END io_oeb[34]
  PIN io_oeb[33]
    DIRECTION OUTPUT ;
    USE SIGNAL ;
    ANTENNADIFFAREA 0.43675 LAYER met3  ;
    ANTENNAPARTIALMETALAREA 8.9964 LAYER met3  ;
    ANTENNAPARTIALMETALSIDEAREA 47.976 LAYER met3  ;
    PORT
      LAYER met3 ;
        RECT 0.000000 1018.000000 0.800000 1018.300000 ;
    END
  END io_oeb[33]
  PIN io_oeb[32]
    DIRECTION OUTPUT ;
    USE SIGNAL ;
    ANTENNADIFFAREA 0.43675 LAYER met3  ;
    ANTENNAPARTIALMETALAREA 8.9964 LAYER met3  ;
    ANTENNAPARTIALMETALSIDEAREA 47.976 LAYER met3  ;
    PORT
      LAYER met3 ;
        RECT 0.000000 1272.370000 0.800000 1272.670000 ;
    END
  END io_oeb[32]
  PIN io_oeb[31]
    DIRECTION OUTPUT ;
    USE SIGNAL ;
    ANTENNADIFFAREA 0.43675 LAYER met3  ;
    ANTENNAPARTIALMETALAREA 0.1644 LAYER met3  ;
    ANTENNAPARTIALMETALSIDEAREA 0.872 LAYER met3  ;
    PORT
      LAYER met3 ;
        RECT 0.000000 1526.740000 0.800000 1527.040000 ;
    END
  END io_oeb[31]
  PIN io_oeb[30]
    DIRECTION OUTPUT ;
    USE SIGNAL ;
    ANTENNADIFFAREA 0.43675 LAYER met3  ;
    ANTENNAPARTIALMETALAREA 9.4104 LAYER met3  ;
    ANTENNAPARTIALMETALSIDEAREA 50.184 LAYER met3  ;
    PORT
      LAYER met3 ;
        RECT 0.000000 1781.110000 0.800000 1781.410000 ;
    END
  END io_oeb[30]
  PIN io_oeb[29]
    DIRECTION OUTPUT ;
    USE SIGNAL ;
    ANTENNADIFFAREA 0.43675 LAYER met3  ;
    ANTENNAPARTIALMETALAREA 8.8584 LAYER met3  ;
    ANTENNAPARTIALMETALSIDEAREA 47.24 LAYER met3  ;
    PORT
      LAYER met3 ;
        RECT 0.000000 2035.480000 0.800000 2035.780000 ;
    END
  END io_oeb[29]
  PIN io_oeb[28]
    DIRECTION OUTPUT ;
    USE SIGNAL ;
    ANTENNADIFFAREA 0.43675 LAYER met3  ;
    ANTENNAPARTIALMETALAREA 9.4104 LAYER met3  ;
    ANTENNAPARTIALMETALSIDEAREA 50.184 LAYER met3  ;
    PORT
      LAYER met3 ;
        RECT 0.000000 2289.850000 0.800000 2290.150000 ;
    END
  END io_oeb[28]
  PIN io_oeb[27]
    DIRECTION OUTPUT ;
    USE SIGNAL ;
    ANTENNADIFFAREA 0.43675 LAYER met3  ;
    ANTENNAPARTIALMETALAREA 8.1684 LAYER met3  ;
    ANTENNAPARTIALMETALSIDEAREA 43.56 LAYER met3  ;
    PORT
      LAYER met3 ;
        RECT 0.000000 2544.220000 0.800000 2544.520000 ;
    END
  END io_oeb[27]
  PIN io_oeb[26]
    DIRECTION OUTPUT ;
    USE SIGNAL ;
    ANTENNADIFFAREA 0.43675 LAYER met3  ;
    ANTENNAPARTIALMETALAREA 8.8584 LAYER met3  ;
    ANTENNAPARTIALMETALSIDEAREA 47.24 LAYER met3  ;
    PORT
      LAYER met3 ;
        RECT 0.000000 2798.590000 0.800000 2798.890000 ;
    END
  END io_oeb[26]
  PIN io_oeb[25]
    DIRECTION OUTPUT ;
    USE SIGNAL ;
    ANTENNADIFFAREA 0.43675 LAYER met3  ;
    ANTENNAPARTIALMETALAREA 0.1644 LAYER met3  ;
    ANTENNAPARTIALMETALSIDEAREA 0.872 LAYER met3  ;
    PORT
      LAYER met3 ;
        RECT 0.000000 3052.960000 0.800000 3053.260000 ;
    END
  END io_oeb[25]
  PIN io_oeb[24]
    DIRECTION OUTPUT ;
    USE SIGNAL ;
    ANTENNADIFFAREA 0.43675 LAYER met3  ;
    ANTENNAPARTIALMETALAREA 9.4104 LAYER met3  ;
    ANTENNAPARTIALMETALSIDEAREA 50.184 LAYER met3  ;
    PORT
      LAYER met3 ;
        RECT 0.000000 3307.330000 0.800000 3307.630000 ;
    END
  END io_oeb[24]
  PIN io_oeb[23]
    DIRECTION OUTPUT ;
    USE SIGNAL ;
    ANTENNADIFFAREA 0.43675 LAYER met2  ;
    ANTENNAPARTIALMETALAREA 5.4431 LAYER met2  ;
    ANTENNAPARTIALMETALSIDEAREA 27.1075 LAYER met2  ;
    PORT
      LAYER met2 ;
        RECT 0.160000 3476.695000 0.300000 3477.180000 ;
    END
  END io_oeb[23]
  PIN io_oeb[22]
    DIRECTION OUTPUT ;
    USE SIGNAL ;
    ANTENNADIFFAREA 0.43675 LAYER met2  ;
    ANTENNAPARTIALMETALAREA 4.5863 LAYER met2  ;
    ANTENNAPARTIALMETALSIDEAREA 22.8235 LAYER met2  ;
    PORT
      LAYER met2 ;
        RECT 331.820000 3476.695000 331.960000 3477.180000 ;
    END
  END io_oeb[22]
  PIN io_oeb[21]
    DIRECTION OUTPUT ;
    USE SIGNAL ;
    ANTENNADIFFAREA 0.43675 LAYER met2  ;
    ANTENNAPARTIALMETALAREA 4.5863 LAYER met2  ;
    ANTENNAPARTIALMETALSIDEAREA 22.8235 LAYER met2  ;
    PORT
      LAYER met2 ;
        RECT 663.940000 3476.695000 664.080000 3477.180000 ;
    END
  END io_oeb[21]
  PIN io_oeb[20]
    DIRECTION OUTPUT ;
    USE SIGNAL ;
    ANTENNADIFFAREA 0.43675 LAYER met2  ;
    ANTENNAPARTIALMETALAREA 4.7151 LAYER met2  ;
    ANTENNAPARTIALMETALSIDEAREA 23.4675 LAYER met2  ;
    PORT
      LAYER met2 ;
        RECT 995.600000 3476.695000 995.740000 3477.180000 ;
    END
  END io_oeb[20]
  PIN io_oeb[19]
    DIRECTION OUTPUT ;
    USE SIGNAL ;
    ANTENNADIFFAREA 0.43675 LAYER met2  ;
    ANTENNAPARTIALMETALAREA 4.5863 LAYER met2  ;
    ANTENNAPARTIALMETALSIDEAREA 22.8235 LAYER met2  ;
    PORT
      LAYER met2 ;
        RECT 1327.720000 3476.695000 1327.860000 3477.180000 ;
    END
  END io_oeb[19]
  PIN io_oeb[18]
    DIRECTION OUTPUT ;
    USE SIGNAL ;
    ANTENNADIFFAREA 0.43675 LAYER met2  ;
    ANTENNAPARTIALMETALAREA 4.6507 LAYER met2  ;
    ANTENNAPARTIALMETALSIDEAREA 23.1455 LAYER met2  ;
    PORT
      LAYER met2 ;
        RECT 1659.380000 3476.695000 1659.520000 3477.180000 ;
    END
  END io_oeb[18]
  PIN io_oeb[17]
    DIRECTION OUTPUT ;
    USE SIGNAL ;
    ANTENNADIFFAREA 0.43675 LAYER met2  ;
    ANTENNAPARTIALMETALAREA 4.5863 LAYER met2  ;
    ANTENNAPARTIALMETALSIDEAREA 22.8235 LAYER met2  ;
    PORT
      LAYER met2 ;
        RECT 1991.500000 3476.695000 1991.640000 3477.180000 ;
    END
  END io_oeb[17]
  PIN io_oeb[16]
    DIRECTION OUTPUT ;
    USE SIGNAL ;
    ANTENNADIFFAREA 0.43675 LAYER met2  ;
    ANTENNAPARTIALMETALAREA 4.5863 LAYER met2  ;
    ANTENNAPARTIALMETALSIDEAREA 22.8235 LAYER met2  ;
    PORT
      LAYER met2 ;
        RECT 2323.160000 3476.695000 2323.300000 3477.180000 ;
    END
  END io_oeb[16]
  PIN io_oeb[15]
    DIRECTION OUTPUT ;
    USE SIGNAL ;
    ANTENNADIFFAREA 0.43675 LAYER met2  ;
    ANTENNAPARTIALMETALAREA 4.6507 LAYER met2  ;
    ANTENNAPARTIALMETALSIDEAREA 23.1455 LAYER met2  ;
    PORT
      LAYER met2 ;
        RECT 2655.280000 3476.695000 2655.420000 3477.180000 ;
    END
  END io_oeb[15]
  PIN io_oeb[14]
    DIRECTION OUTPUT ;
    USE SIGNAL ;
    ANTENNADIFFAREA 0.43675 LAYER met3  ;
    ANTENNAPARTIALMETALAREA 12.5844 LAYER met3  ;
    ANTENNAPARTIALMETALSIDEAREA 67.112 LAYER met3  ;
    PORT
      LAYER met3 ;
        RECT 2876.040000 3476.300000 2876.840000 3476.600000 ;
    END
  END io_oeb[14]
  PIN io_oeb[13]
    DIRECTION OUTPUT ;
    USE SIGNAL ;
    ANTENNADIFFAREA 0.43675 LAYER met3  ;
    ANTENNAPARTIALMETALAREA 0.1644 LAYER met3  ;
    ANTENNAPARTIALMETALSIDEAREA 0.872 LAYER met3  ;
    PORT
      LAYER met3 ;
        RECT 2876.040000 3240.230000 2876.840000 3240.530000 ;
    END
  END io_oeb[13]
  PIN io_oeb[12]
    DIRECTION OUTPUT ;
    USE SIGNAL ;
    ANTENNADIFFAREA 0.43675 LAYER met3  ;
    ANTENNAPARTIALMETALAREA 8.9964 LAYER met3  ;
    ANTENNAPARTIALMETALSIDEAREA 47.976 LAYER met3  ;
    PORT
      LAYER met3 ;
        RECT 2876.040000 3002.940000 2876.840000 3003.240000 ;
    END
  END io_oeb[12]
  PIN io_oeb[11]
    DIRECTION OUTPUT ;
    USE SIGNAL ;
    ANTENNADIFFAREA 0.43675 LAYER met3  ;
    ANTENNAPARTIALMETALAREA 6.0984 LAYER met3  ;
    ANTENNAPARTIALMETALSIDEAREA 32.52 LAYER met3  ;
    PORT
      LAYER met3 ;
        RECT 2876.040000 2766.260000 2876.840000 2766.560000 ;
    END
  END io_oeb[11]
  PIN io_oeb[10]
    DIRECTION OUTPUT ;
    USE SIGNAL ;
    ANTENNADIFFAREA 0.43675 LAYER met3  ;
    ANTENNAPARTIALMETALAREA 9.1344 LAYER met3  ;
    ANTENNAPARTIALMETALSIDEAREA 48.712 LAYER met3  ;
    PORT
      LAYER met3 ;
        RECT 2876.040000 2528.970000 2876.840000 2529.270000 ;
    END
  END io_oeb[10]
  PIN io_oeb[9]
    DIRECTION OUTPUT ;
    USE SIGNAL ;
    ANTENNADIFFAREA 0.43675 LAYER met3  ;
    ANTENNAPARTIALMETALAREA 8.9964 LAYER met3  ;
    ANTENNAPARTIALMETALSIDEAREA 47.976 LAYER met3  ;
    PORT
      LAYER met3 ;
        RECT 2876.040000 2292.290000 2876.840000 2292.590000 ;
    END
  END io_oeb[9]
  PIN io_oeb[8]
    DIRECTION OUTPUT ;
    USE SIGNAL ;
    ANTENNADIFFAREA 0.43675 LAYER met3  ;
    ANTENNAPARTIALMETALAREA 0.1644 LAYER met3  ;
    ANTENNAPARTIALMETALSIDEAREA 0.872 LAYER met3  ;
    PORT
      LAYER met3 ;
        RECT 2876.040000 2055.000000 2876.840000 2055.300000 ;
    END
  END io_oeb[8]
  PIN io_oeb[7]
    DIRECTION OUTPUT ;
    USE SIGNAL ;
    ANTENNADIFFAREA 0.43675 LAYER met3  ;
    ANTENNAPARTIALMETALAREA 8.8584 LAYER met3  ;
    ANTENNAPARTIALMETALSIDEAREA 47.24 LAYER met3  ;
    PORT
      LAYER met3 ;
        RECT 2876.040000 1818.320000 2876.840000 1818.620000 ;
    END
  END io_oeb[7]
  PIN io_oeb[6]
    DIRECTION OUTPUT ;
    USE SIGNAL ;
    ANTENNADIFFAREA 0.43675 LAYER met3  ;
    ANTENNAPARTIALMETALAREA 0.1644 LAYER met3  ;
    ANTENNAPARTIALMETALSIDEAREA 0.872 LAYER met3  ;
    PORT
      LAYER met3 ;
        RECT 2876.040000 1581.030000 2876.840000 1581.330000 ;
    END
  END io_oeb[6]
  PIN io_oeb[5]
    DIRECTION OUTPUT ;
    USE SIGNAL ;
    ANTENNADIFFAREA 0.43675 LAYER met3  ;
    ANTENNAPARTIALMETALAREA 8.9964 LAYER met3  ;
    ANTENNAPARTIALMETALSIDEAREA 47.976 LAYER met3  ;
    PORT
      LAYER met3 ;
        RECT 2876.040000 1343.740000 2876.840000 1344.040000 ;
    END
  END io_oeb[5]
  PIN io_oeb[4]
    DIRECTION OUTPUT ;
    USE SIGNAL ;
    ANTENNADIFFAREA 0.43675 LAYER met3  ;
    ANTENNAPARTIALMETALAREA 6.0984 LAYER met3  ;
    ANTENNAPARTIALMETALSIDEAREA 32.52 LAYER met3  ;
    PORT
      LAYER met3 ;
        RECT 2876.040000 1107.060000 2876.840000 1107.360000 ;
    END
  END io_oeb[4]
  PIN io_oeb[3]
    DIRECTION OUTPUT ;
    USE SIGNAL ;
    ANTENNADIFFAREA 0.43675 LAYER met3  ;
    ANTENNAPARTIALMETALAREA 9.2724 LAYER met3  ;
    ANTENNAPARTIALMETALSIDEAREA 49.448 LAYER met3  ;
    PORT
      LAYER met3 ;
        RECT 2876.040000 869.770000 2876.840000 870.070000 ;
    END
  END io_oeb[3]
  PIN io_oeb[2]
    DIRECTION OUTPUT ;
    USE SIGNAL ;
    ANTENNADIFFAREA 0.43675 LAYER met3  ;
    ANTENNAPARTIALMETALAREA 0.1644 LAYER met3  ;
    ANTENNAPARTIALMETALSIDEAREA 0.872 LAYER met3  ;
    PORT
      LAYER met3 ;
        RECT 2876.040000 633.090000 2876.840000 633.390000 ;
    END
  END io_oeb[2]
  PIN io_oeb[1]
    DIRECTION OUTPUT ;
    USE SIGNAL ;
    ANTENNADIFFAREA 0.43675 LAYER met3  ;
    ANTENNAPARTIALMETALAREA 0.1644 LAYER met3  ;
    ANTENNAPARTIALMETALSIDEAREA 0.872 LAYER met3  ;
    PORT
      LAYER met3 ;
        RECT 2876.040000 395.800000 2876.840000 396.100000 ;
    END
  END io_oeb[1]
  PIN io_oeb[0]
    DIRECTION OUTPUT ;
    USE SIGNAL ;
    ANTENNADIFFAREA 0.43675 LAYER met3  ;
    ANTENNAPARTIALMETALAREA 8.9964 LAYER met3  ;
    ANTENNAPARTIALMETALSIDEAREA 47.976 LAYER met3  ;
    PORT
      LAYER met3 ;
        RECT 2876.040000 159.120000 2876.840000 159.420000 ;
    END
  END io_oeb[0]
  PIN irq[2]
    DIRECTION OUTPUT ;
    USE SIGNAL ;
    ANTENNADIFFAREA 0.43675 LAYER met2  ;
    ANTENNAPARTIALMETALAREA 5.3003 LAYER met2  ;
    ANTENNAPARTIALMETALSIDEAREA 26.3935 LAYER met2  ;
    PORT
      LAYER met2 ;
        RECT 2876.540000 0.000000 2876.680000 0.485000 ;
    END
  END irq[2]
  PIN irq[1]
    DIRECTION OUTPUT ;
    USE SIGNAL ;
    ANTENNADIFFAREA 0.43675 LAYER met2  ;
    ANTENNAPARTIALMETALAREA 10.5363 LAYER met2  ;
    ANTENNAPARTIALMETALSIDEAREA 52.5735 LAYER met2  ;
    PORT
      LAYER met2 ;
        RECT 2871.020000 0.000000 2871.160000 0.485000 ;
    END
  END irq[1]
  PIN irq[0]
    DIRECTION OUTPUT ;
    USE SIGNAL ;
    ANTENNADIFFAREA 0.43675 LAYER met2  ;
    ANTENNAPARTIALMETALAREA 3.5867 LAYER met2  ;
    ANTENNAPARTIALMETALSIDEAREA 17.8255 LAYER met2  ;
    PORT
      LAYER met2 ;
        RECT 2865.040000 0.000000 2865.180000 0.485000 ;
    END
  END irq[0]
  PIN VSS
    DIRECTION INOUT ;
    USE GROUND ;
    PORT
      LAYER met5 ;
        RECT 2868.680000 3463.920000 2876.840000 3472.080000 ;
    END
    PORT
      LAYER met5 ;
        RECT 0.000000 3463.920000 8.160000 3472.080000 ;
    END
    PORT
      LAYER met5 ;
        RECT 2868.680000 4.080000 2876.840000 12.240000 ;
    END
    PORT
      LAYER met5 ;
        RECT 0.000000 4.080000 8.160000 12.240000 ;
    END
    PORT
      LAYER met4 ;
        RECT 2864.640000 3469.020000 2872.800000 3477.180000 ;
    END
    PORT
      LAYER met4 ;
        RECT 2864.640000 0.000000 2872.800000 8.160000 ;
    END
    PORT
      LAYER met4 ;
        RECT 4.040000 3469.020000 12.200000 3477.180000 ;
    END
    PORT
      LAYER met4 ;
        RECT 4.040000 0.000000 12.200000 8.160000 ;
    END

# P/G power stripe data as pin
    PORT
      LAYER met4 ;
        RECT 4.040000 0.000000 12.200000 3477.180000 ;
        RECT 40.800000 4.080000 44.160000 3472.080000 ;
        RECT 68.000000 4.080000 71.360000 3472.080000 ;
        RECT 95.200000 4.080000 98.560000 3472.080000 ;
        RECT 122.400000 4.080000 125.760000 3472.080000 ;
        RECT 340.000000 4.080000 343.360000 3472.080000 ;
        RECT 312.800000 4.080000 316.160000 3472.080000 ;
        RECT 285.600000 4.080000 288.960000 3472.080000 ;
        RECT 258.400000 4.080000 261.760000 3472.080000 ;
        RECT 231.200000 4.080000 234.560000 3472.080000 ;
        RECT 204.000000 4.080000 207.360000 3472.080000 ;
        RECT 176.800000 4.080000 180.160000 3472.080000 ;
        RECT 149.600000 4.080000 152.960000 3472.080000 ;
        RECT 557.600000 4.080000 560.960000 3472.080000 ;
        RECT 530.400000 4.080000 533.760000 3472.080000 ;
        RECT 503.200000 4.080000 506.560000 3472.080000 ;
        RECT 476.000000 4.080000 479.360000 3472.080000 ;
        RECT 448.800000 4.080000 452.160000 3472.080000 ;
        RECT 421.600000 4.080000 424.960000 3472.080000 ;
        RECT 394.400000 4.080000 397.760000 3472.080000 ;
        RECT 367.200000 4.080000 370.560000 3472.080000 ;
        RECT 775.200000 4.080000 778.560000 3472.080000 ;
        RECT 748.000000 4.080000 751.360000 3472.080000 ;
        RECT 720.800000 4.080000 724.160000 3472.080000 ;
        RECT 693.600000 4.080000 696.960000 3472.080000 ;
        RECT 666.400000 4.080000 669.760000 3472.080000 ;
        RECT 639.200000 4.080000 642.560000 3472.080000 ;
        RECT 612.000000 4.080000 615.360000 3472.080000 ;
        RECT 584.800000 4.080000 588.160000 3472.080000 ;
        RECT 992.800000 4.080000 996.160000 3472.080000 ;
        RECT 965.600000 4.080000 968.960000 3472.080000 ;
        RECT 938.400000 4.080000 941.760000 3472.080000 ;
        RECT 911.200000 4.080000 914.560000 3472.080000 ;
        RECT 884.000000 4.080000 887.360000 3472.080000 ;
        RECT 856.800000 4.080000 860.160000 3472.080000 ;
        RECT 829.600000 4.080000 832.960000 3472.080000 ;
        RECT 802.400000 4.080000 805.760000 3472.080000 ;
        RECT 1210.400000 4.080000 1213.760000 3472.080000 ;
        RECT 1183.200000 4.080000 1186.560000 3472.080000 ;
        RECT 1156.000000 4.080000 1159.360000 3472.080000 ;
        RECT 1128.800000 4.080000 1132.160000 3472.080000 ;
        RECT 1101.600000 4.080000 1104.960000 3472.080000 ;
        RECT 1074.400000 4.080000 1077.760000 3472.080000 ;
        RECT 1047.200000 4.080000 1050.560000 3472.080000 ;
        RECT 1020.000000 4.080000 1023.360000 3472.080000 ;
        RECT 1373.600000 4.080000 1376.960000 3472.080000 ;
        RECT 1346.400000 4.080000 1349.760000 3472.080000 ;
        RECT 1319.200000 4.080000 1322.560000 3472.080000 ;
        RECT 1292.000000 4.080000 1295.360000 3472.080000 ;
        RECT 1264.800000 4.080000 1268.160000 3472.080000 ;
        RECT 1237.600000 4.080000 1240.960000 3472.080000 ;
        RECT 1400.800000 4.080000 1404.160000 3472.080000 ;
        RECT 1428.000000 4.080000 1431.360000 3472.080000 ;
        RECT 1455.200000 4.080000 1458.560000 3472.080000 ;
        RECT 1482.400000 4.080000 1485.760000 3472.080000 ;
        RECT 1509.600000 4.080000 1512.960000 3472.080000 ;
        RECT 1536.800000 4.080000 1540.160000 3472.080000 ;
        RECT 1564.000000 4.080000 1567.360000 3472.080000 ;
        RECT 1591.200000 4.080000 1594.560000 3472.080000 ;
        RECT 1618.400000 4.080000 1621.760000 3472.080000 ;
        RECT 1645.600000 4.080000 1648.960000 3472.080000 ;
        RECT 1672.800000 4.080000 1676.160000 3472.080000 ;
        RECT 1700.000000 4.080000 1703.360000 3472.080000 ;
        RECT 1727.200000 4.080000 1730.560000 3472.080000 ;
        RECT 1754.400000 4.080000 1757.760000 3472.080000 ;
        RECT 1781.600000 4.080000 1784.960000 3472.080000 ;
        RECT 1808.800000 4.080000 1812.160000 3472.080000 ;
        RECT 1836.000000 4.080000 1839.360000 3472.080000 ;
        RECT 1863.200000 4.080000 1866.560000 3472.080000 ;
        RECT 1890.400000 4.080000 1893.760000 3472.080000 ;
        RECT 1917.600000 4.080000 1920.960000 3472.080000 ;
        RECT 1944.800000 4.080000 1948.160000 3472.080000 ;
        RECT 1972.000000 4.080000 1975.360000 3472.080000 ;
        RECT 1999.200000 4.080000 2002.560000 3472.080000 ;
        RECT 2026.400000 4.080000 2029.760000 3472.080000 ;
        RECT 2053.600000 4.080000 2056.960000 3472.080000 ;
        RECT 2080.800000 4.080000 2084.160000 3472.080000 ;
        RECT 2244.000000 4.080000 2247.360000 3472.080000 ;
        RECT 2108.000000 4.080000 2111.360000 3472.080000 ;
        RECT 2135.200000 4.080000 2138.560000 3472.080000 ;
        RECT 2162.400000 4.080000 2165.760000 3472.080000 ;
        RECT 2189.600000 4.080000 2192.960000 3472.080000 ;
        RECT 2216.800000 4.080000 2220.160000 3472.080000 ;
        RECT 2271.200000 4.080000 2274.560000 3472.080000 ;
        RECT 2298.400000 4.080000 2301.760000 3472.080000 ;
        RECT 2516.000000 4.080000 2519.360000 3472.080000 ;
        RECT 2488.800000 4.080000 2492.160000 3472.080000 ;
        RECT 2461.600000 4.080000 2464.960000 3472.080000 ;
        RECT 2434.400000 4.080000 2437.760000 3472.080000 ;
        RECT 2407.200000 4.080000 2410.560000 3472.080000 ;
        RECT 2380.000000 4.080000 2383.360000 3472.080000 ;
        RECT 2352.800000 4.080000 2356.160000 3472.080000 ;
        RECT 2325.600000 4.080000 2328.960000 3472.080000 ;
        RECT 2733.600000 4.080000 2736.960000 3472.080000 ;
        RECT 2706.400000 4.080000 2709.760000 3472.080000 ;
        RECT 2679.200000 4.080000 2682.560000 3472.080000 ;
        RECT 2652.000000 4.080000 2655.360000 3472.080000 ;
        RECT 2624.800000 4.080000 2628.160000 3472.080000 ;
        RECT 2597.600000 4.080000 2600.960000 3472.080000 ;
        RECT 2570.400000 4.080000 2573.760000 3472.080000 ;
        RECT 2543.200000 4.080000 2546.560000 3472.080000 ;
        RECT 2864.640000 0.000000 2872.800000 3477.180000 ;
        RECT 2760.800000 4.080000 2764.160000 3472.080000 ;
        RECT 2788.000000 4.080000 2791.360000 3472.080000 ;
        RECT 2815.200000 4.080000 2818.560000 3472.080000 ;
        RECT 2842.400000 4.080000 2845.760000 3472.080000 ;
      LAYER met5 ;
        RECT 4.040000 40.800000 2872.800000 44.160000 ;
        RECT 0.000000 4.080000 2876.840000 12.240000 ;
        RECT 4.040000 95.200000 2872.800000 98.560000 ;
        RECT 4.040000 68.000000 2872.800000 71.360000 ;
        RECT 4.040000 149.600000 2872.800000 152.960000 ;
        RECT 4.040000 122.400000 2872.800000 125.760000 ;
        RECT 4.040000 204.000000 2872.800000 207.360000 ;
        RECT 4.040000 176.800000 2872.800000 180.160000 ;
        RECT 4.040000 258.400000 2872.800000 261.760000 ;
        RECT 4.040000 231.200000 2872.800000 234.560000 ;
        RECT 4.040000 312.800000 2872.800000 316.160000 ;
        RECT 4.040000 285.600000 2872.800000 288.960000 ;
        RECT 4.040000 367.200000 2872.800000 370.560000 ;
        RECT 4.040000 340.000000 2872.800000 343.360000 ;
        RECT 4.040000 421.600000 2872.800000 424.960000 ;
        RECT 4.040000 394.400000 2872.800000 397.760000 ;
        RECT 4.040000 476.000000 2872.800000 479.360000 ;
        RECT 4.040000 448.800000 2872.800000 452.160000 ;
        RECT 4.040000 530.400000 2872.800000 533.760000 ;
        RECT 4.040000 503.200000 2872.800000 506.560000 ;
        RECT 4.040000 584.800000 2872.800000 588.160000 ;
        RECT 4.040000 557.600000 2872.800000 560.960000 ;
        RECT 4.040000 639.200000 2872.800000 642.560000 ;
        RECT 4.040000 612.000000 2872.800000 615.360000 ;
        RECT 4.040000 693.600000 2872.800000 696.960000 ;
        RECT 4.040000 666.400000 2872.800000 669.760000 ;
        RECT 4.040000 720.800000 2872.800000 724.160000 ;
        RECT 4.040000 748.000000 2872.800000 751.360000 ;
        RECT 4.040000 775.200000 2872.800000 778.560000 ;
        RECT 4.040000 802.400000 2872.800000 805.760000 ;
        RECT 4.040000 856.800000 2872.800000 860.160000 ;
        RECT 4.040000 829.600000 2872.800000 832.960000 ;
        RECT 4.040000 911.200000 2872.800000 914.560000 ;
        RECT 4.040000 884.000000 2872.800000 887.360000 ;
        RECT 4.040000 965.600000 2872.800000 968.960000 ;
        RECT 4.040000 938.400000 2872.800000 941.760000 ;
        RECT 4.040000 1020.000000 2872.800000 1023.360000 ;
        RECT 4.040000 992.800000 2872.800000 996.160000 ;
        RECT 4.040000 1074.400000 2872.800000 1077.760000 ;
        RECT 4.040000 1047.200000 2872.800000 1050.560000 ;
        RECT 4.040000 1128.800000 2872.800000 1132.160000 ;
        RECT 4.040000 1101.600000 2872.800000 1104.960000 ;
        RECT 4.040000 1183.200000 2872.800000 1186.560000 ;
        RECT 4.040000 1156.000000 2872.800000 1159.360000 ;
        RECT 4.040000 1237.600000 2872.800000 1240.960000 ;
        RECT 4.040000 1210.400000 2872.800000 1213.760000 ;
        RECT 4.040000 1292.000000 2872.800000 1295.360000 ;
        RECT 4.040000 1264.800000 2872.800000 1268.160000 ;
        RECT 4.040000 1346.400000 2872.800000 1349.760000 ;
        RECT 4.040000 1319.200000 2872.800000 1322.560000 ;
        RECT 4.040000 1400.800000 2872.800000 1404.160000 ;
        RECT 4.040000 1373.600000 2872.800000 1376.960000 ;
        RECT 4.040000 1455.200000 2872.800000 1458.560000 ;
        RECT 4.040000 1428.000000 2872.800000 1431.360000 ;
        RECT 4.040000 1509.600000 2872.800000 1512.960000 ;
        RECT 4.040000 1482.400000 2872.800000 1485.760000 ;
        RECT 4.040000 1564.000000 2872.800000 1567.360000 ;
        RECT 4.040000 1536.800000 2872.800000 1540.160000 ;
        RECT 4.040000 1618.400000 2872.800000 1621.760000 ;
        RECT 4.040000 1591.200000 2872.800000 1594.560000 ;
        RECT 4.040000 1672.800000 2872.800000 1676.160000 ;
        RECT 4.040000 1645.600000 2872.800000 1648.960000 ;
        RECT 4.040000 1700.000000 2872.800000 1703.360000 ;
        RECT 4.040000 1727.200000 2872.800000 1730.560000 ;
        RECT 4.040000 1754.400000 2872.800000 1757.760000 ;
        RECT 4.040000 1781.600000 2872.800000 1784.960000 ;
        RECT 4.040000 1808.800000 2872.800000 1812.160000 ;
        RECT 4.040000 1836.000000 2872.800000 1839.360000 ;
        RECT 4.040000 1863.200000 2872.800000 1866.560000 ;
        RECT 4.040000 1890.400000 2872.800000 1893.760000 ;
        RECT 4.040000 1917.600000 2872.800000 1920.960000 ;
        RECT 4.040000 1944.800000 2872.800000 1948.160000 ;
        RECT 4.040000 1972.000000 2872.800000 1975.360000 ;
        RECT 4.040000 1999.200000 2872.800000 2002.560000 ;
        RECT 4.040000 2026.400000 2872.800000 2029.760000 ;
        RECT 4.040000 2053.600000 2872.800000 2056.960000 ;
        RECT 4.040000 2080.800000 2872.800000 2084.160000 ;
        RECT 4.040000 2108.000000 2872.800000 2111.360000 ;
        RECT 4.040000 2135.200000 2872.800000 2138.560000 ;
        RECT 4.040000 2162.400000 2872.800000 2165.760000 ;
        RECT 4.040000 2189.600000 2872.800000 2192.960000 ;
        RECT 4.040000 2216.800000 2872.800000 2220.160000 ;
        RECT 4.040000 2244.000000 2872.800000 2247.360000 ;
        RECT 4.040000 2271.200000 2872.800000 2274.560000 ;
        RECT 4.040000 2298.400000 2872.800000 2301.760000 ;
        RECT 4.040000 2325.600000 2872.800000 2328.960000 ;
        RECT 4.040000 2352.800000 2872.800000 2356.160000 ;
        RECT 4.040000 2380.000000 2872.800000 2383.360000 ;
        RECT 4.040000 2407.200000 2872.800000 2410.560000 ;
        RECT 4.040000 2434.400000 2872.800000 2437.760000 ;
        RECT 4.040000 2461.600000 2872.800000 2464.960000 ;
        RECT 4.040000 2488.800000 2872.800000 2492.160000 ;
        RECT 4.040000 2516.000000 2872.800000 2519.360000 ;
        RECT 4.040000 2543.200000 2872.800000 2546.560000 ;
        RECT 4.040000 2570.400000 2872.800000 2573.760000 ;
        RECT 4.040000 2597.600000 2872.800000 2600.960000 ;
        RECT 4.040000 2652.000000 2872.800000 2655.360000 ;
        RECT 4.040000 2624.800000 2872.800000 2628.160000 ;
        RECT 4.040000 2706.400000 2872.800000 2709.760000 ;
        RECT 4.040000 2679.200000 2872.800000 2682.560000 ;
        RECT 4.040000 2760.800000 2872.800000 2764.160000 ;
        RECT 4.040000 2733.600000 2872.800000 2736.960000 ;
        RECT 4.040000 2815.200000 2872.800000 2818.560000 ;
        RECT 4.040000 2788.000000 2872.800000 2791.360000 ;
        RECT 4.040000 2869.600000 2872.800000 2872.960000 ;
        RECT 4.040000 2842.400000 2872.800000 2845.760000 ;
        RECT 4.040000 2924.000000 2872.800000 2927.360000 ;
        RECT 4.040000 2896.800000 2872.800000 2900.160000 ;
        RECT 4.040000 2978.400000 2872.800000 2981.760000 ;
        RECT 4.040000 2951.200000 2872.800000 2954.560000 ;
        RECT 4.040000 3032.800000 2872.800000 3036.160000 ;
        RECT 4.040000 3005.600000 2872.800000 3008.960000 ;
        RECT 4.040000 3087.200000 2872.800000 3090.560000 ;
        RECT 4.040000 3060.000000 2872.800000 3063.360000 ;
        RECT 4.040000 3141.600000 2872.800000 3144.960000 ;
        RECT 4.040000 3114.400000 2872.800000 3117.760000 ;
        RECT 4.040000 3196.000000 2872.800000 3199.360000 ;
        RECT 4.040000 3168.800000 2872.800000 3172.160000 ;
        RECT 4.040000 3250.400000 2872.800000 3253.760000 ;
        RECT 4.040000 3223.200000 2872.800000 3226.560000 ;
        RECT 4.040000 3304.800000 2872.800000 3308.160000 ;
        RECT 4.040000 3277.600000 2872.800000 3280.960000 ;
        RECT 4.040000 3359.200000 2872.800000 3362.560000 ;
        RECT 4.040000 3332.000000 2872.800000 3335.360000 ;
        RECT 4.040000 3386.400000 2872.800000 3389.760000 ;
        RECT 4.040000 3413.600000 2872.800000 3416.960000 ;
        RECT 0.000000 3463.920000 2876.840000 3472.080000 ;
        RECT 4.040000 3440.800000 2872.800000 3444.160000 ;
    END
# end of P/G power stripe data as pin

  END VSS
  PIN VDD
    DIRECTION INOUT ;
    USE POWER ;
    PORT
      LAYER met5 ;
        RECT 2868.680000 3451.680000 2876.840000 3459.840000 ;
    END
    PORT
      LAYER met5 ;
        RECT 0.000000 3451.680000 8.160000 3459.840000 ;
    END
    PORT
      LAYER met5 ;
        RECT 2868.680000 16.320000 2876.840000 24.480000 ;
    END
    PORT
      LAYER met5 ;
        RECT 0.000000 16.320000 8.160000 24.480000 ;
    END
    PORT
      LAYER met4 ;
        RECT 2852.400000 3469.020000 2860.560000 3477.180000 ;
    END
    PORT
      LAYER met4 ;
        RECT 2852.400000 0.000000 2860.560000 8.160000 ;
    END
    PORT
      LAYER met4 ;
        RECT 16.280000 3469.020000 24.440000 3477.180000 ;
    END
    PORT
      LAYER met4 ;
        RECT 16.280000 0.000000 24.440000 8.160000 ;
    END

# P/G power stripe data as pin
    PORT
      LAYER met4 ;
        RECT 16.280000 0.000000 24.440000 3477.180000 ;
        RECT 27.200000 16.320000 30.560000 3459.840000 ;
        RECT 54.400000 16.320000 57.760000 3459.840000 ;
        RECT 81.600000 16.320000 84.960000 3459.840000 ;
        RECT 108.800000 16.320000 112.160000 3459.840000 ;
        RECT 217.600000 16.320000 220.960000 3459.840000 ;
        RECT 190.400000 16.320000 193.760000 3459.840000 ;
        RECT 163.200000 16.320000 166.560000 3459.840000 ;
        RECT 136.000000 16.320000 139.360000 3459.840000 ;
        RECT 244.800000 16.320000 248.160000 3459.840000 ;
        RECT 272.000000 16.320000 275.360000 3459.840000 ;
        RECT 299.200000 16.320000 302.560000 3459.840000 ;
        RECT 326.400000 16.320000 329.760000 3459.840000 ;
        RECT 544.000000 16.320000 547.360000 3459.840000 ;
        RECT 516.800000 16.320000 520.160000 3459.840000 ;
        RECT 353.600000 16.320000 356.960000 3459.840000 ;
        RECT 380.800000 16.320000 384.160000 3459.840000 ;
        RECT 408.000000 16.320000 411.360000 3459.840000 ;
        RECT 435.200000 16.320000 438.560000 3459.840000 ;
        RECT 462.400000 16.320000 465.760000 3459.840000 ;
        RECT 489.600000 16.320000 492.960000 3459.840000 ;
        RECT 571.200000 16.320000 574.560000 3459.840000 ;
        RECT 598.400000 16.320000 601.760000 3459.840000 ;
        RECT 625.600000 16.320000 628.960000 3459.840000 ;
        RECT 652.800000 16.320000 656.160000 3459.840000 ;
        RECT 680.000000 16.320000 683.360000 3459.840000 ;
        RECT 707.200000 16.320000 710.560000 3459.840000 ;
        RECT 734.400000 16.320000 737.760000 3459.840000 ;
        RECT 761.600000 16.320000 764.960000 3459.840000 ;
        RECT 979.200000 16.320000 982.560000 3459.840000 ;
        RECT 952.000000 16.320000 955.360000 3459.840000 ;
        RECT 788.800000 16.320000 792.160000 3459.840000 ;
        RECT 816.000000 16.320000 819.360000 3459.840000 ;
        RECT 843.200000 16.320000 846.560000 3459.840000 ;
        RECT 870.400000 16.320000 873.760000 3459.840000 ;
        RECT 897.600000 16.320000 900.960000 3459.840000 ;
        RECT 924.800000 16.320000 928.160000 3459.840000 ;
        RECT 1006.400000 16.320000 1009.760000 3459.840000 ;
        RECT 1033.600000 16.320000 1036.960000 3459.840000 ;
        RECT 1060.800000 16.320000 1064.160000 3459.840000 ;
        RECT 1088.000000 16.320000 1091.360000 3459.840000 ;
        RECT 1115.200000 16.320000 1118.560000 3459.840000 ;
        RECT 1142.400000 16.320000 1145.760000 3459.840000 ;
        RECT 1169.600000 16.320000 1172.960000 3459.840000 ;
        RECT 1196.800000 16.320000 1200.160000 3459.840000 ;
        RECT 1414.400000 16.320000 1417.760000 3459.840000 ;
        RECT 1387.200000 16.320000 1390.560000 3459.840000 ;
        RECT 1224.000000 16.320000 1227.360000 3459.840000 ;
        RECT 1251.200000 16.320000 1254.560000 3459.840000 ;
        RECT 1278.400000 16.320000 1281.760000 3459.840000 ;
        RECT 1305.600000 16.320000 1308.960000 3459.840000 ;
        RECT 1332.800000 16.320000 1336.160000 3459.840000 ;
        RECT 1360.000000 16.320000 1363.360000 3459.840000 ;
        RECT 1441.600000 16.320000 1444.960000 3459.840000 ;
        RECT 1468.800000 16.320000 1472.160000 3459.840000 ;
        RECT 1496.000000 16.320000 1499.360000 3459.840000 ;
        RECT 1523.200000 16.320000 1526.560000 3459.840000 ;
        RECT 1550.400000 16.320000 1553.760000 3459.840000 ;
        RECT 1577.600000 16.320000 1580.960000 3459.840000 ;
        RECT 1604.800000 16.320000 1608.160000 3459.840000 ;
        RECT 1632.000000 16.320000 1635.360000 3459.840000 ;
        RECT 1849.600000 16.320000 1852.960000 3459.840000 ;
        RECT 1822.400000 16.320000 1825.760000 3459.840000 ;
        RECT 1659.200000 16.320000 1662.560000 3459.840000 ;
        RECT 1686.400000 16.320000 1689.760000 3459.840000 ;
        RECT 1713.600000 16.320000 1716.960000 3459.840000 ;
        RECT 1740.800000 16.320000 1744.160000 3459.840000 ;
        RECT 1768.000000 16.320000 1771.360000 3459.840000 ;
        RECT 1795.200000 16.320000 1798.560000 3459.840000 ;
        RECT 1876.800000 16.320000 1880.160000 3459.840000 ;
        RECT 1904.000000 16.320000 1907.360000 3459.840000 ;
        RECT 1931.200000 16.320000 1934.560000 3459.840000 ;
        RECT 1958.400000 16.320000 1961.760000 3459.840000 ;
        RECT 1985.600000 16.320000 1988.960000 3459.840000 ;
        RECT 2012.800000 16.320000 2016.160000 3459.840000 ;
        RECT 2040.000000 16.320000 2043.360000 3459.840000 ;
        RECT 2067.200000 16.320000 2070.560000 3459.840000 ;
        RECT 2284.800000 16.320000 2288.160000 3459.840000 ;
        RECT 2257.600000 16.320000 2260.960000 3459.840000 ;
        RECT 2094.400000 16.320000 2097.760000 3459.840000 ;
        RECT 2121.600000 16.320000 2124.960000 3459.840000 ;
        RECT 2148.800000 16.320000 2152.160000 3459.840000 ;
        RECT 2176.000000 16.320000 2179.360000 3459.840000 ;
        RECT 2203.200000 16.320000 2206.560000 3459.840000 ;
        RECT 2230.400000 16.320000 2233.760000 3459.840000 ;
        RECT 2502.400000 16.320000 2505.760000 3459.840000 ;
        RECT 2475.200000 16.320000 2478.560000 3459.840000 ;
        RECT 2448.000000 16.320000 2451.360000 3459.840000 ;
        RECT 2420.800000 16.320000 2424.160000 3459.840000 ;
        RECT 2393.600000 16.320000 2396.960000 3459.840000 ;
        RECT 2366.400000 16.320000 2369.760000 3459.840000 ;
        RECT 2339.200000 16.320000 2342.560000 3459.840000 ;
        RECT 2312.000000 16.320000 2315.360000 3459.840000 ;
        RECT 2720.000000 16.320000 2723.360000 3459.840000 ;
        RECT 2692.800000 16.320000 2696.160000 3459.840000 ;
        RECT 2529.600000 16.320000 2532.960000 3459.840000 ;
        RECT 2556.800000 16.320000 2560.160000 3459.840000 ;
        RECT 2584.000000 16.320000 2587.360000 3459.840000 ;
        RECT 2611.200000 16.320000 2614.560000 3459.840000 ;
        RECT 2638.400000 16.320000 2641.760000 3459.840000 ;
        RECT 2665.600000 16.320000 2668.960000 3459.840000 ;
        RECT 2828.800000 16.320000 2832.160000 3459.840000 ;
        RECT 2801.600000 16.320000 2804.960000 3459.840000 ;
        RECT 2774.400000 16.320000 2777.760000 3459.840000 ;
        RECT 2747.200000 16.320000 2750.560000 3459.840000 ;
        RECT 2852.400000 0.000000 2860.560000 3477.180000 ;
      LAYER met5 ;
        RECT 0.000000 16.320000 2876.840000 24.480000 ;
        RECT 16.280000 27.200000 2860.560000 30.560000 ;
        RECT 16.280000 54.400000 2860.560000 57.760000 ;
        RECT 16.280000 81.600000 2860.560000 84.960000 ;
        RECT 16.280000 108.800000 2860.560000 112.160000 ;
        RECT 16.280000 136.000000 2860.560000 139.360000 ;
        RECT 16.280000 163.200000 2860.560000 166.560000 ;
        RECT 16.280000 190.400000 2860.560000 193.760000 ;
        RECT 16.280000 217.600000 2860.560000 220.960000 ;
        RECT 16.280000 244.800000 2860.560000 248.160000 ;
        RECT 16.280000 272.000000 2860.560000 275.360000 ;
        RECT 16.280000 299.200000 2860.560000 302.560000 ;
        RECT 16.280000 326.400000 2860.560000 329.760000 ;
        RECT 16.280000 353.600000 2860.560000 356.960000 ;
        RECT 16.280000 380.800000 2860.560000 384.160000 ;
        RECT 16.280000 408.000000 2860.560000 411.360000 ;
        RECT 16.280000 435.200000 2860.560000 438.560000 ;
        RECT 16.280000 462.400000 2860.560000 465.760000 ;
        RECT 16.280000 489.600000 2860.560000 492.960000 ;
        RECT 16.280000 516.800000 2860.560000 520.160000 ;
        RECT 16.280000 544.000000 2860.560000 547.360000 ;
        RECT 16.280000 571.200000 2860.560000 574.560000 ;
        RECT 16.280000 598.400000 2860.560000 601.760000 ;
        RECT 16.280000 625.600000 2860.560000 628.960000 ;
        RECT 16.280000 652.800000 2860.560000 656.160000 ;
        RECT 16.280000 680.000000 2860.560000 683.360000 ;
        RECT 16.280000 707.200000 2860.560000 710.560000 ;
        RECT 16.280000 734.400000 2860.560000 737.760000 ;
        RECT 16.280000 761.600000 2860.560000 764.960000 ;
        RECT 16.280000 788.800000 2860.560000 792.160000 ;
        RECT 16.280000 816.000000 2860.560000 819.360000 ;
        RECT 16.280000 843.200000 2860.560000 846.560000 ;
        RECT 16.280000 870.400000 2860.560000 873.760000 ;
        RECT 16.280000 897.600000 2860.560000 900.960000 ;
        RECT 16.280000 924.800000 2860.560000 928.160000 ;
        RECT 16.280000 952.000000 2860.560000 955.360000 ;
        RECT 16.280000 979.200000 2860.560000 982.560000 ;
        RECT 16.280000 1006.400000 2860.560000 1009.760000 ;
        RECT 16.280000 1033.600000 2860.560000 1036.960000 ;
        RECT 16.280000 1060.800000 2860.560000 1064.160000 ;
        RECT 16.280000 1088.000000 2860.560000 1091.360000 ;
        RECT 16.280000 1115.200000 2860.560000 1118.560000 ;
        RECT 16.280000 1142.400000 2860.560000 1145.760000 ;
        RECT 16.280000 1169.600000 2860.560000 1172.960000 ;
        RECT 16.280000 1196.800000 2860.560000 1200.160000 ;
        RECT 16.280000 1224.000000 2860.560000 1227.360000 ;
        RECT 16.280000 1251.200000 2860.560000 1254.560000 ;
        RECT 16.280000 1278.400000 2860.560000 1281.760000 ;
        RECT 16.280000 1305.600000 2860.560000 1308.960000 ;
        RECT 16.280000 1332.800000 2860.560000 1336.160000 ;
        RECT 16.280000 1360.000000 2860.560000 1363.360000 ;
        RECT 16.280000 1387.200000 2860.560000 1390.560000 ;
        RECT 16.280000 1414.400000 2860.560000 1417.760000 ;
        RECT 16.280000 1441.600000 2860.560000 1444.960000 ;
        RECT 16.280000 1468.800000 2860.560000 1472.160000 ;
        RECT 16.280000 1496.000000 2860.560000 1499.360000 ;
        RECT 16.280000 1523.200000 2860.560000 1526.560000 ;
        RECT 16.280000 1550.400000 2860.560000 1553.760000 ;
        RECT 16.280000 1577.600000 2860.560000 1580.960000 ;
        RECT 16.280000 1604.800000 2860.560000 1608.160000 ;
        RECT 16.280000 1632.000000 2860.560000 1635.360000 ;
        RECT 16.280000 1659.200000 2860.560000 1662.560000 ;
        RECT 16.280000 1686.400000 2860.560000 1689.760000 ;
        RECT 16.280000 1713.600000 2860.560000 1716.960000 ;
        RECT 16.280000 1740.800000 2860.560000 1744.160000 ;
        RECT 16.280000 1768.000000 2860.560000 1771.360000 ;
        RECT 16.280000 1795.200000 2860.560000 1798.560000 ;
        RECT 16.280000 1822.400000 2860.560000 1825.760000 ;
        RECT 16.280000 1849.600000 2860.560000 1852.960000 ;
        RECT 16.280000 1876.800000 2860.560000 1880.160000 ;
        RECT 16.280000 1904.000000 2860.560000 1907.360000 ;
        RECT 16.280000 1931.200000 2860.560000 1934.560000 ;
        RECT 16.280000 1958.400000 2860.560000 1961.760000 ;
        RECT 16.280000 1985.600000 2860.560000 1988.960000 ;
        RECT 16.280000 2012.800000 2860.560000 2016.160000 ;
        RECT 16.280000 2040.000000 2860.560000 2043.360000 ;
        RECT 16.280000 2067.200000 2860.560000 2070.560000 ;
        RECT 16.280000 2094.400000 2860.560000 2097.760000 ;
        RECT 16.280000 2121.600000 2860.560000 2124.960000 ;
        RECT 16.280000 2148.800000 2860.560000 2152.160000 ;
        RECT 16.280000 2176.000000 2860.560000 2179.360000 ;
        RECT 16.280000 2203.200000 2860.560000 2206.560000 ;
        RECT 16.280000 2230.400000 2860.560000 2233.760000 ;
        RECT 16.280000 2257.600000 2860.560000 2260.960000 ;
        RECT 16.280000 2284.800000 2860.560000 2288.160000 ;
        RECT 16.280000 2312.000000 2860.560000 2315.360000 ;
        RECT 16.280000 2339.200000 2860.560000 2342.560000 ;
        RECT 16.280000 2366.400000 2860.560000 2369.760000 ;
        RECT 16.280000 2393.600000 2860.560000 2396.960000 ;
        RECT 16.280000 2420.800000 2860.560000 2424.160000 ;
        RECT 16.280000 2448.000000 2860.560000 2451.360000 ;
        RECT 16.280000 2475.200000 2860.560000 2478.560000 ;
        RECT 16.280000 2502.400000 2860.560000 2505.760000 ;
        RECT 16.280000 2529.600000 2860.560000 2532.960000 ;
        RECT 16.280000 2556.800000 2860.560000 2560.160000 ;
        RECT 16.280000 2584.000000 2860.560000 2587.360000 ;
        RECT 16.280000 2611.200000 2860.560000 2614.560000 ;
        RECT 16.280000 2638.400000 2860.560000 2641.760000 ;
        RECT 16.280000 2665.600000 2860.560000 2668.960000 ;
        RECT 16.280000 2692.800000 2860.560000 2696.160000 ;
        RECT 16.280000 2720.000000 2860.560000 2723.360000 ;
        RECT 16.280000 2747.200000 2860.560000 2750.560000 ;
        RECT 16.280000 2774.400000 2860.560000 2777.760000 ;
        RECT 16.280000 2801.600000 2860.560000 2804.960000 ;
        RECT 16.280000 2828.800000 2860.560000 2832.160000 ;
        RECT 16.280000 2856.000000 2860.560000 2859.360000 ;
        RECT 16.280000 2883.200000 2860.560000 2886.560000 ;
        RECT 16.280000 2910.400000 2860.560000 2913.760000 ;
        RECT 16.280000 2937.600000 2860.560000 2940.960000 ;
        RECT 16.280000 2964.800000 2860.560000 2968.160000 ;
        RECT 16.280000 2992.000000 2860.560000 2995.360000 ;
        RECT 16.280000 3019.200000 2860.560000 3022.560000 ;
        RECT 16.280000 3046.400000 2860.560000 3049.760000 ;
        RECT 16.280000 3073.600000 2860.560000 3076.960000 ;
        RECT 16.280000 3100.800000 2860.560000 3104.160000 ;
        RECT 16.280000 3128.000000 2860.560000 3131.360000 ;
        RECT 16.280000 3155.200000 2860.560000 3158.560000 ;
        RECT 16.280000 3182.400000 2860.560000 3185.760000 ;
        RECT 16.280000 3209.600000 2860.560000 3212.960000 ;
        RECT 16.280000 3236.800000 2860.560000 3240.160000 ;
        RECT 16.280000 3264.000000 2860.560000 3267.360000 ;
        RECT 16.280000 3291.200000 2860.560000 3294.560000 ;
        RECT 16.280000 3318.400000 2860.560000 3321.760000 ;
        RECT 16.280000 3345.600000 2860.560000 3348.960000 ;
        RECT 16.280000 3372.800000 2860.560000 3376.160000 ;
        RECT 16.280000 3400.000000 2860.560000 3403.360000 ;
        RECT 0.000000 3451.680000 2876.840000 3459.840000 ;
        RECT 16.280000 3427.200000 2860.560000 3430.560000 ;
    END
# end of P/G power stripe data as pin

  END VDD
  OBS
    LAYER li1 ;
      RECT 0.000000 0.000000 2876.840000 3477.180000 ;
    LAYER met1 ;
      RECT 0.000000 0.000000 2876.840000 3477.180000 ;
    LAYER met2 ;
      RECT 0.000000 0.000000 2876.840000 3477.180000 ;
    LAYER met3 ;
      RECT 0.000000 0.000000 2876.840000 3477.180000 ;
    LAYER met4 ;
      RECT 0.000000 0.000000 2876.840000 3477.180000 ;
    LAYER met5 ;
      RECT 0.000000 0.000000 2876.840000 3477.180000 ;
  END
END user_proj_example

END LIBRARY
